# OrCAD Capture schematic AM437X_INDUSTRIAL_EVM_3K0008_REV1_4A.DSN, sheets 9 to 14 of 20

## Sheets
9 Pg03: Processor Power: size C
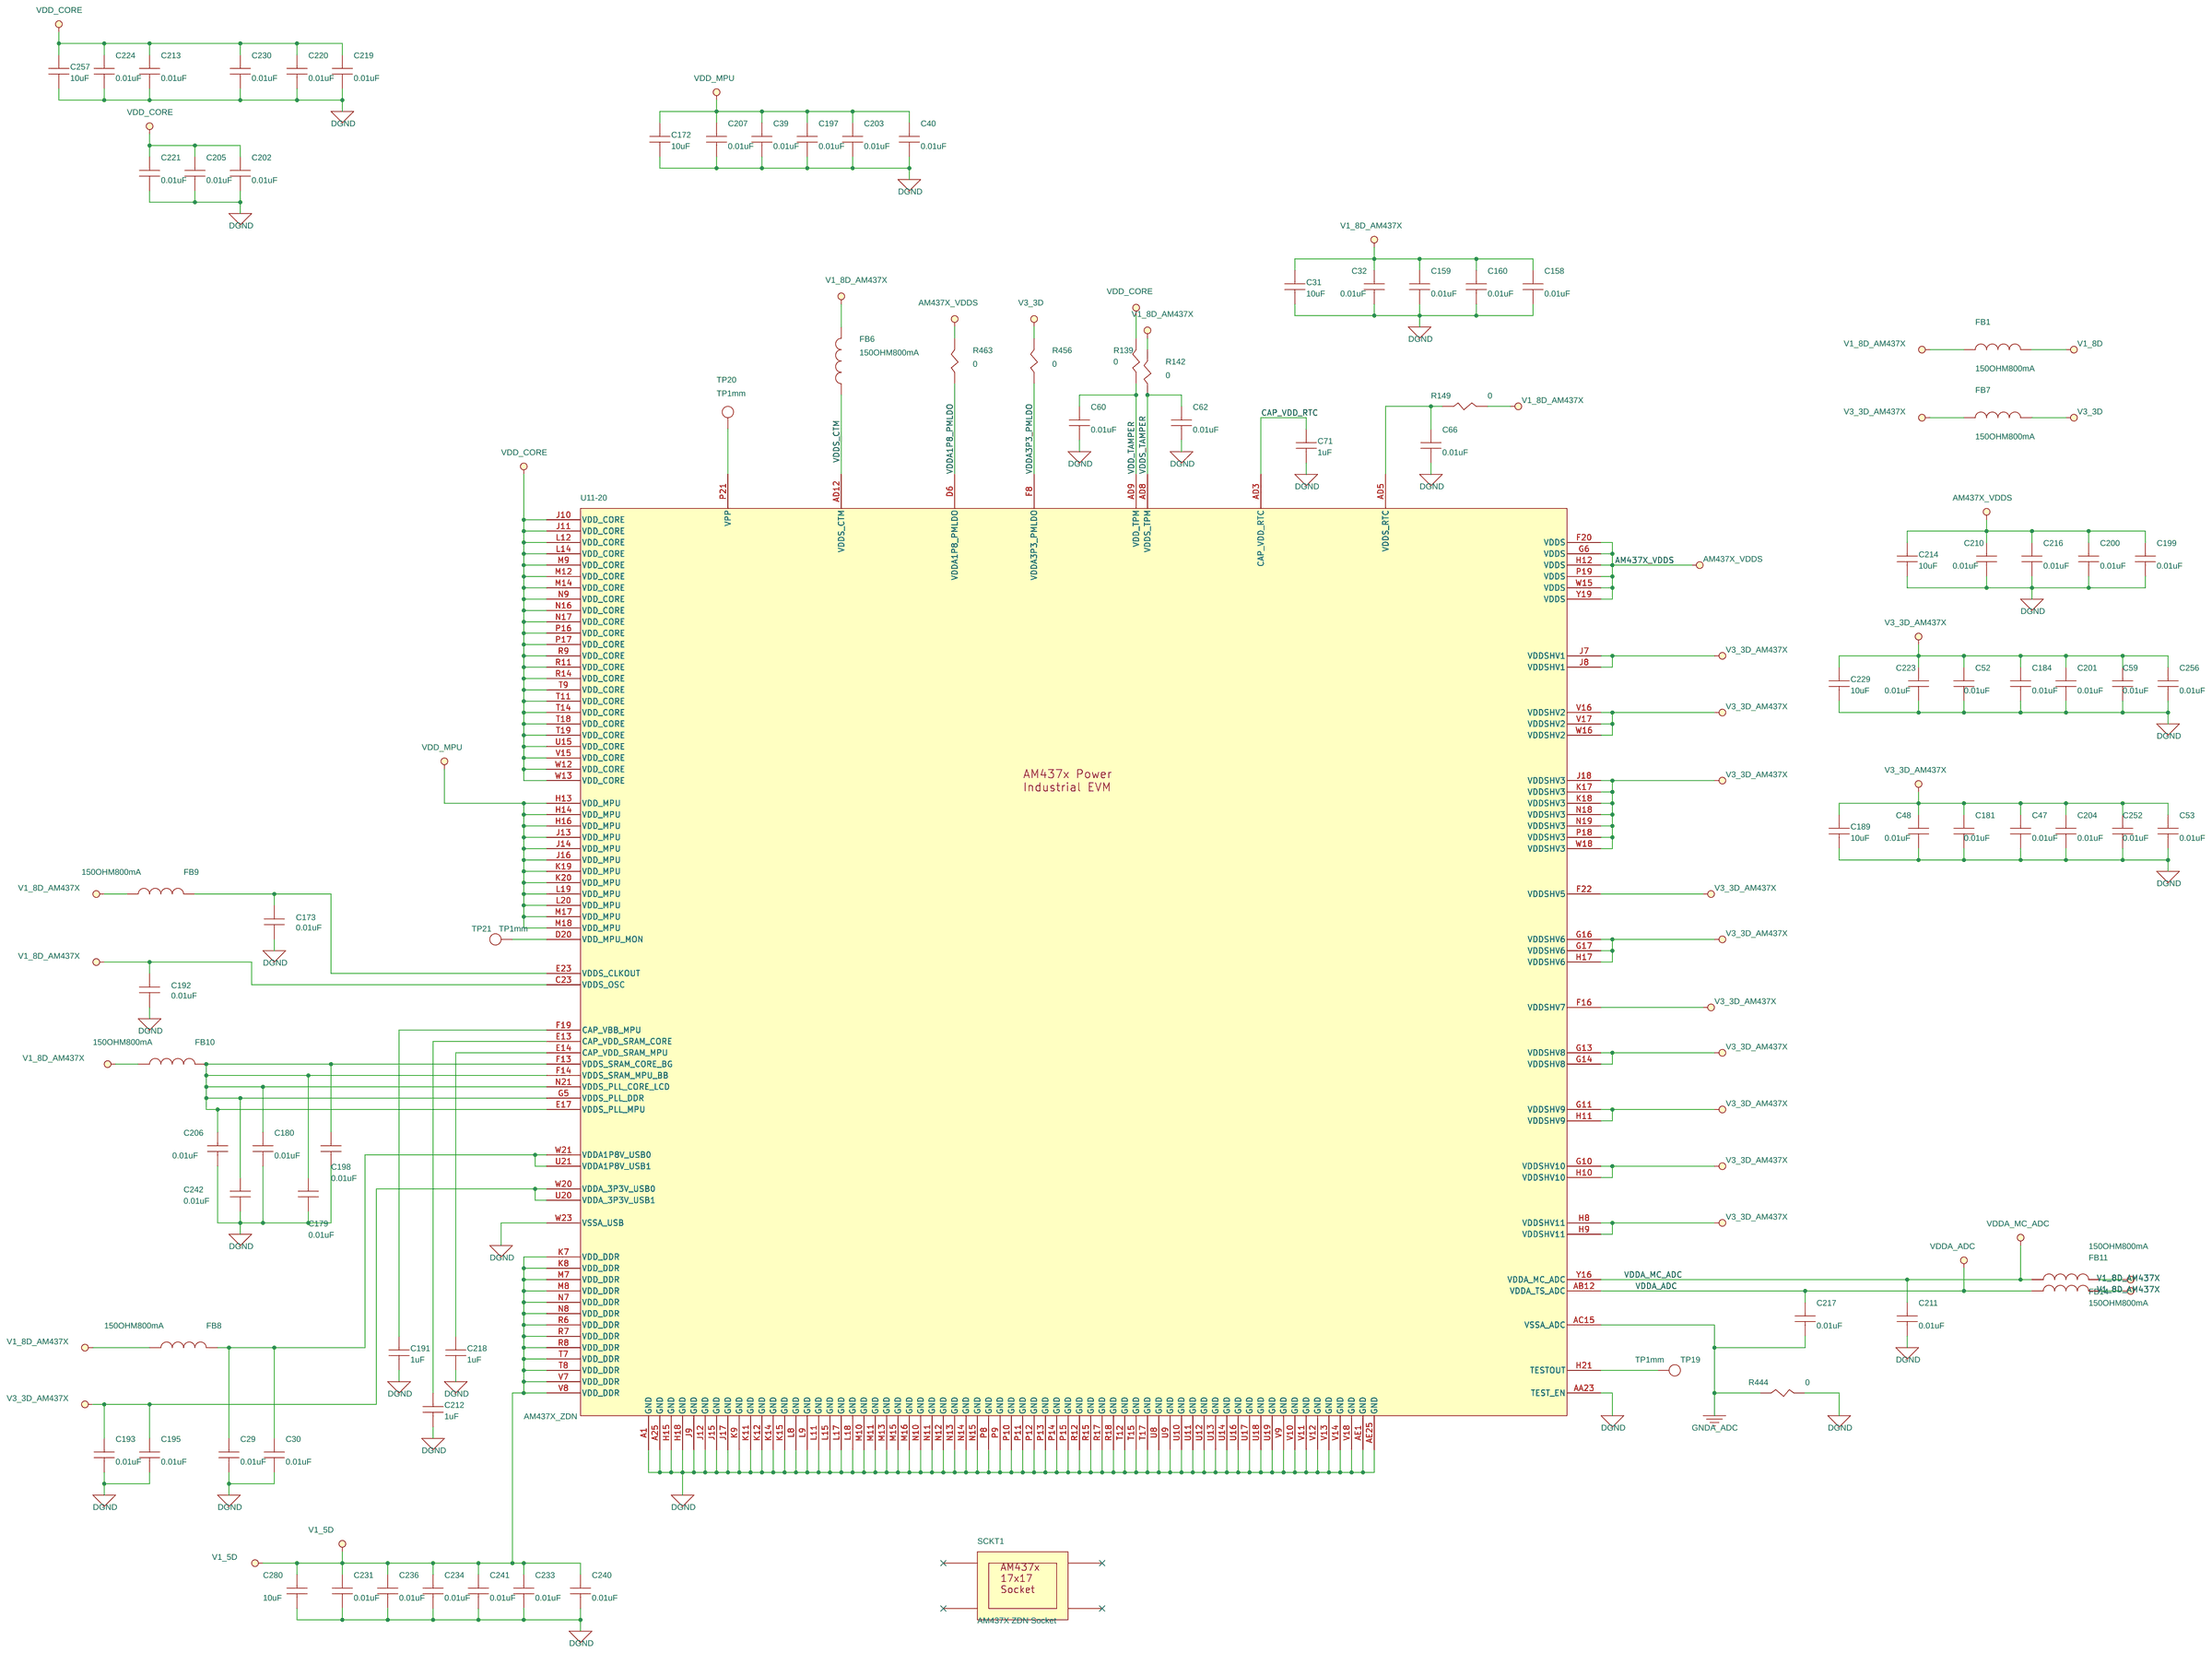
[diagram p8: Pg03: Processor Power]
10 Pg14: Motor Driver: size C
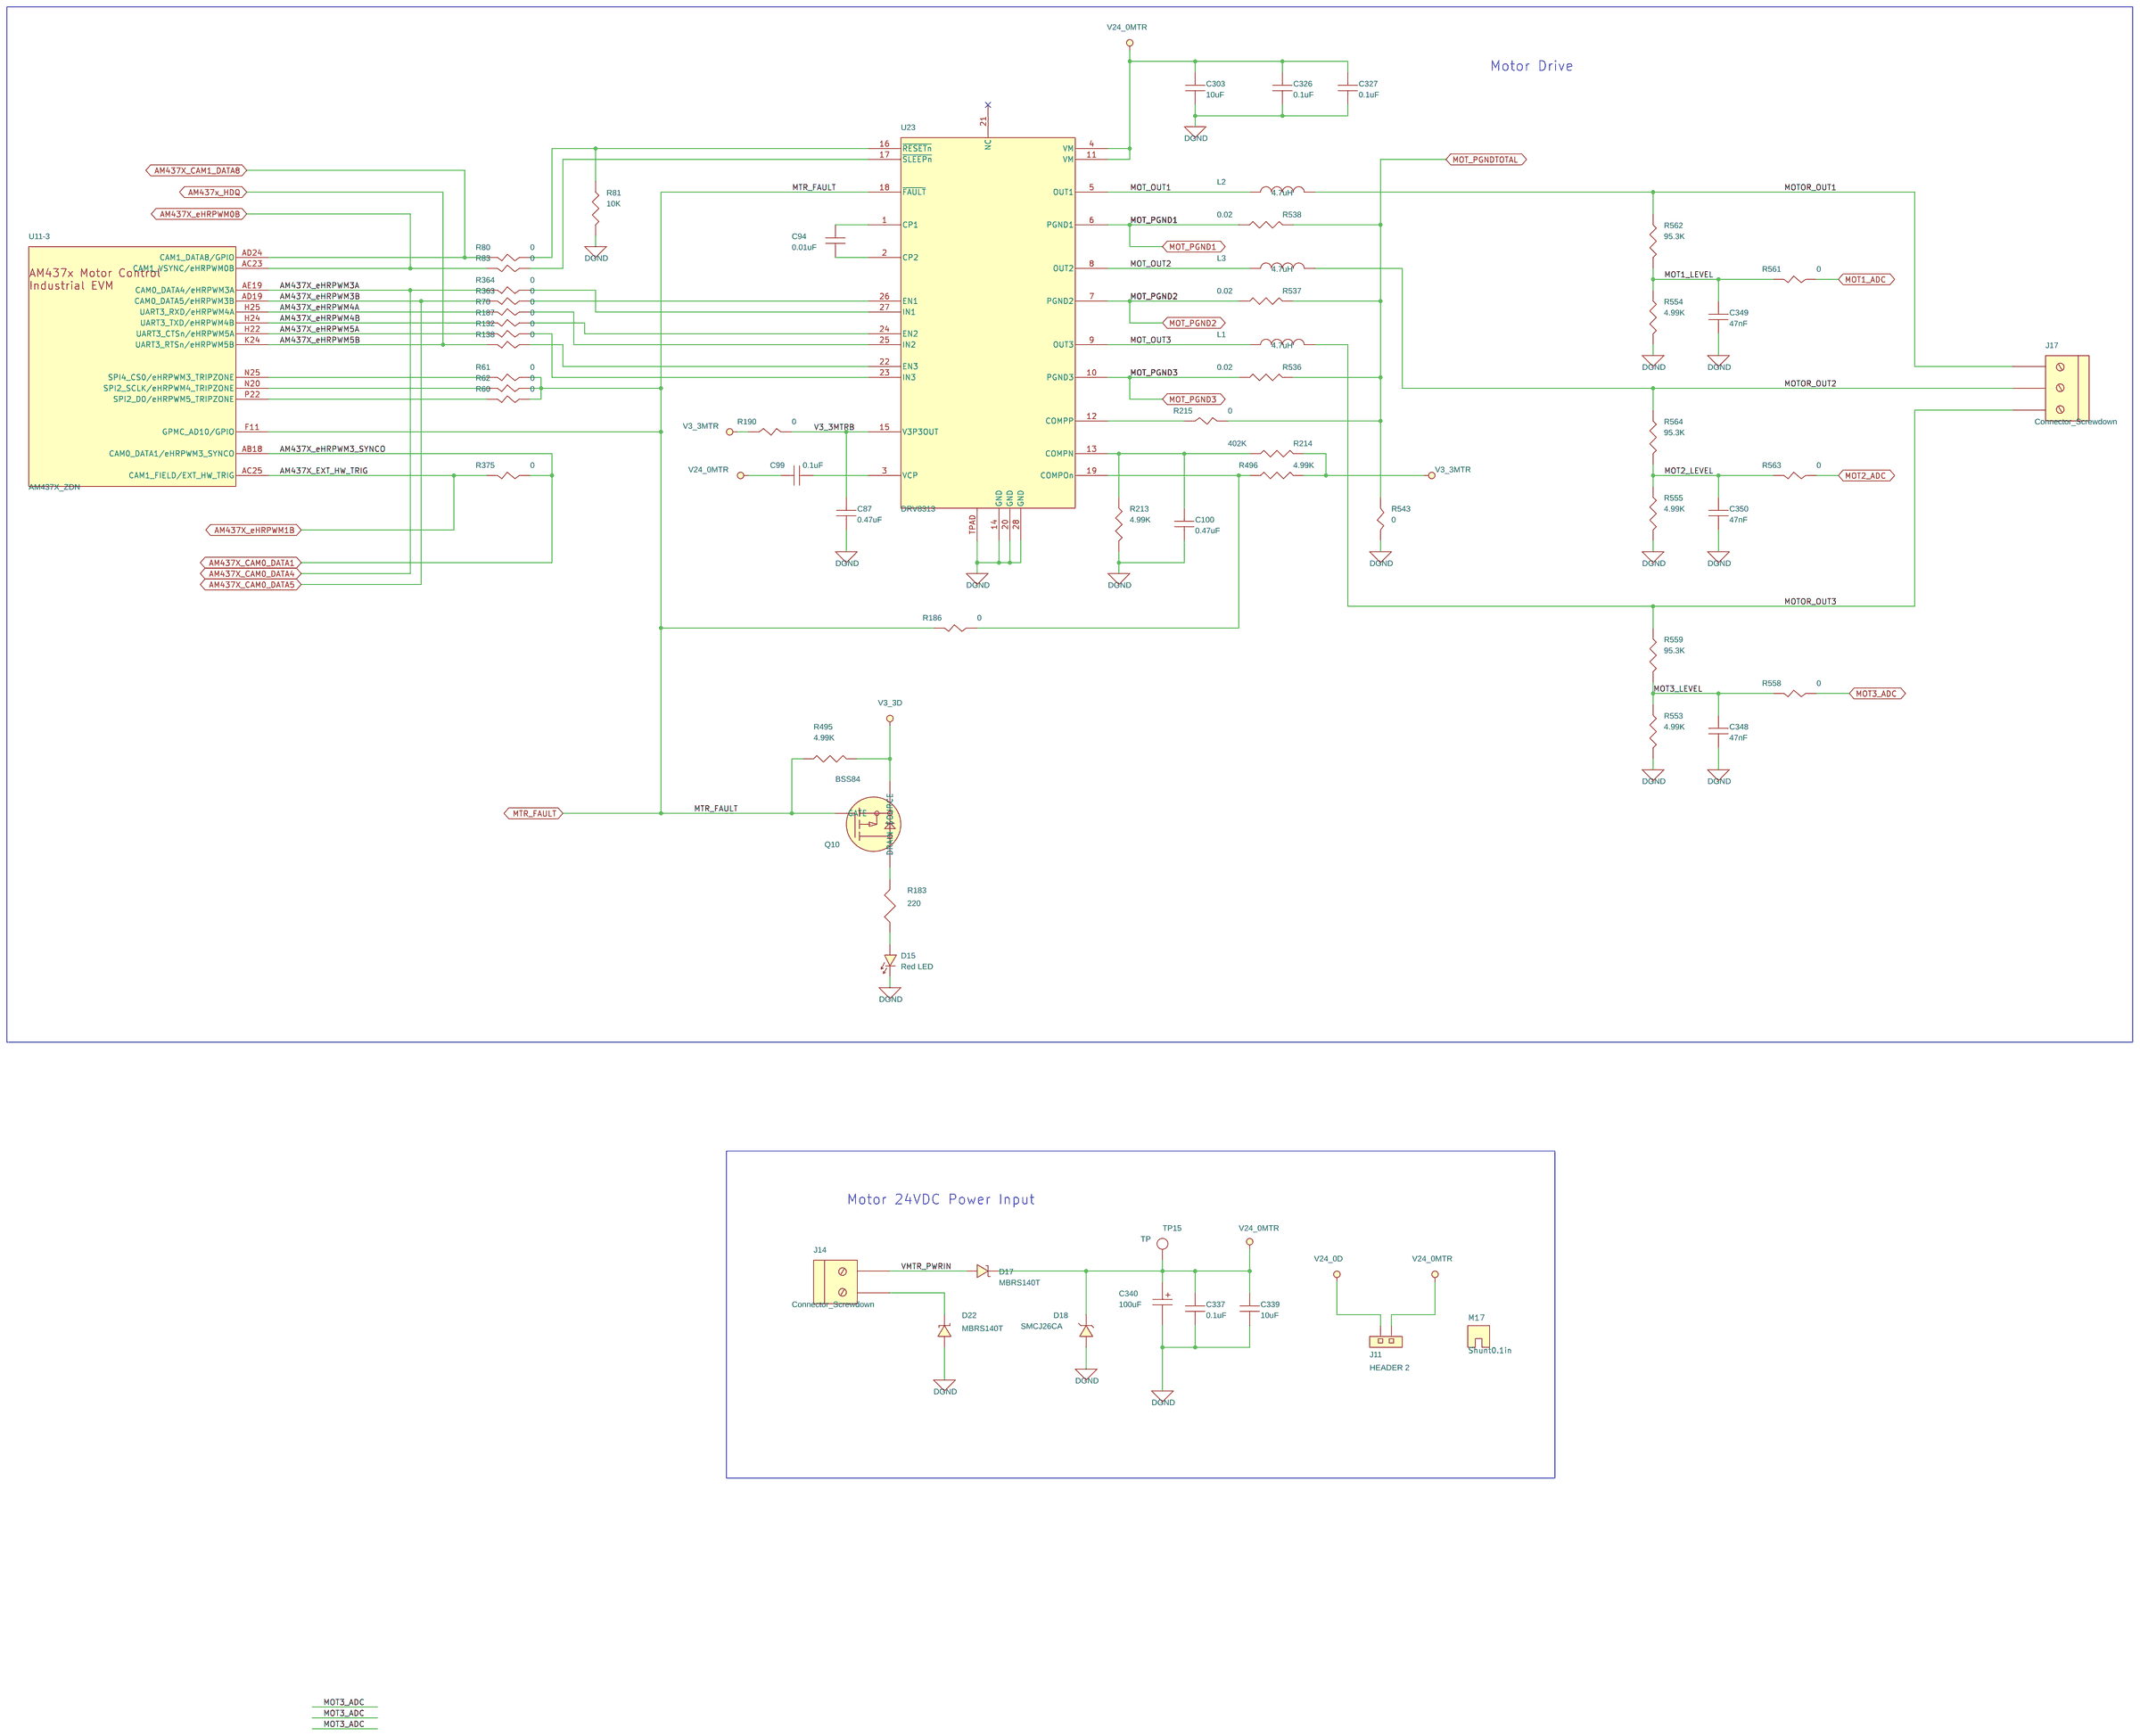
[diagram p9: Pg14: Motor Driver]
11 Pg04: Power Supply: size C
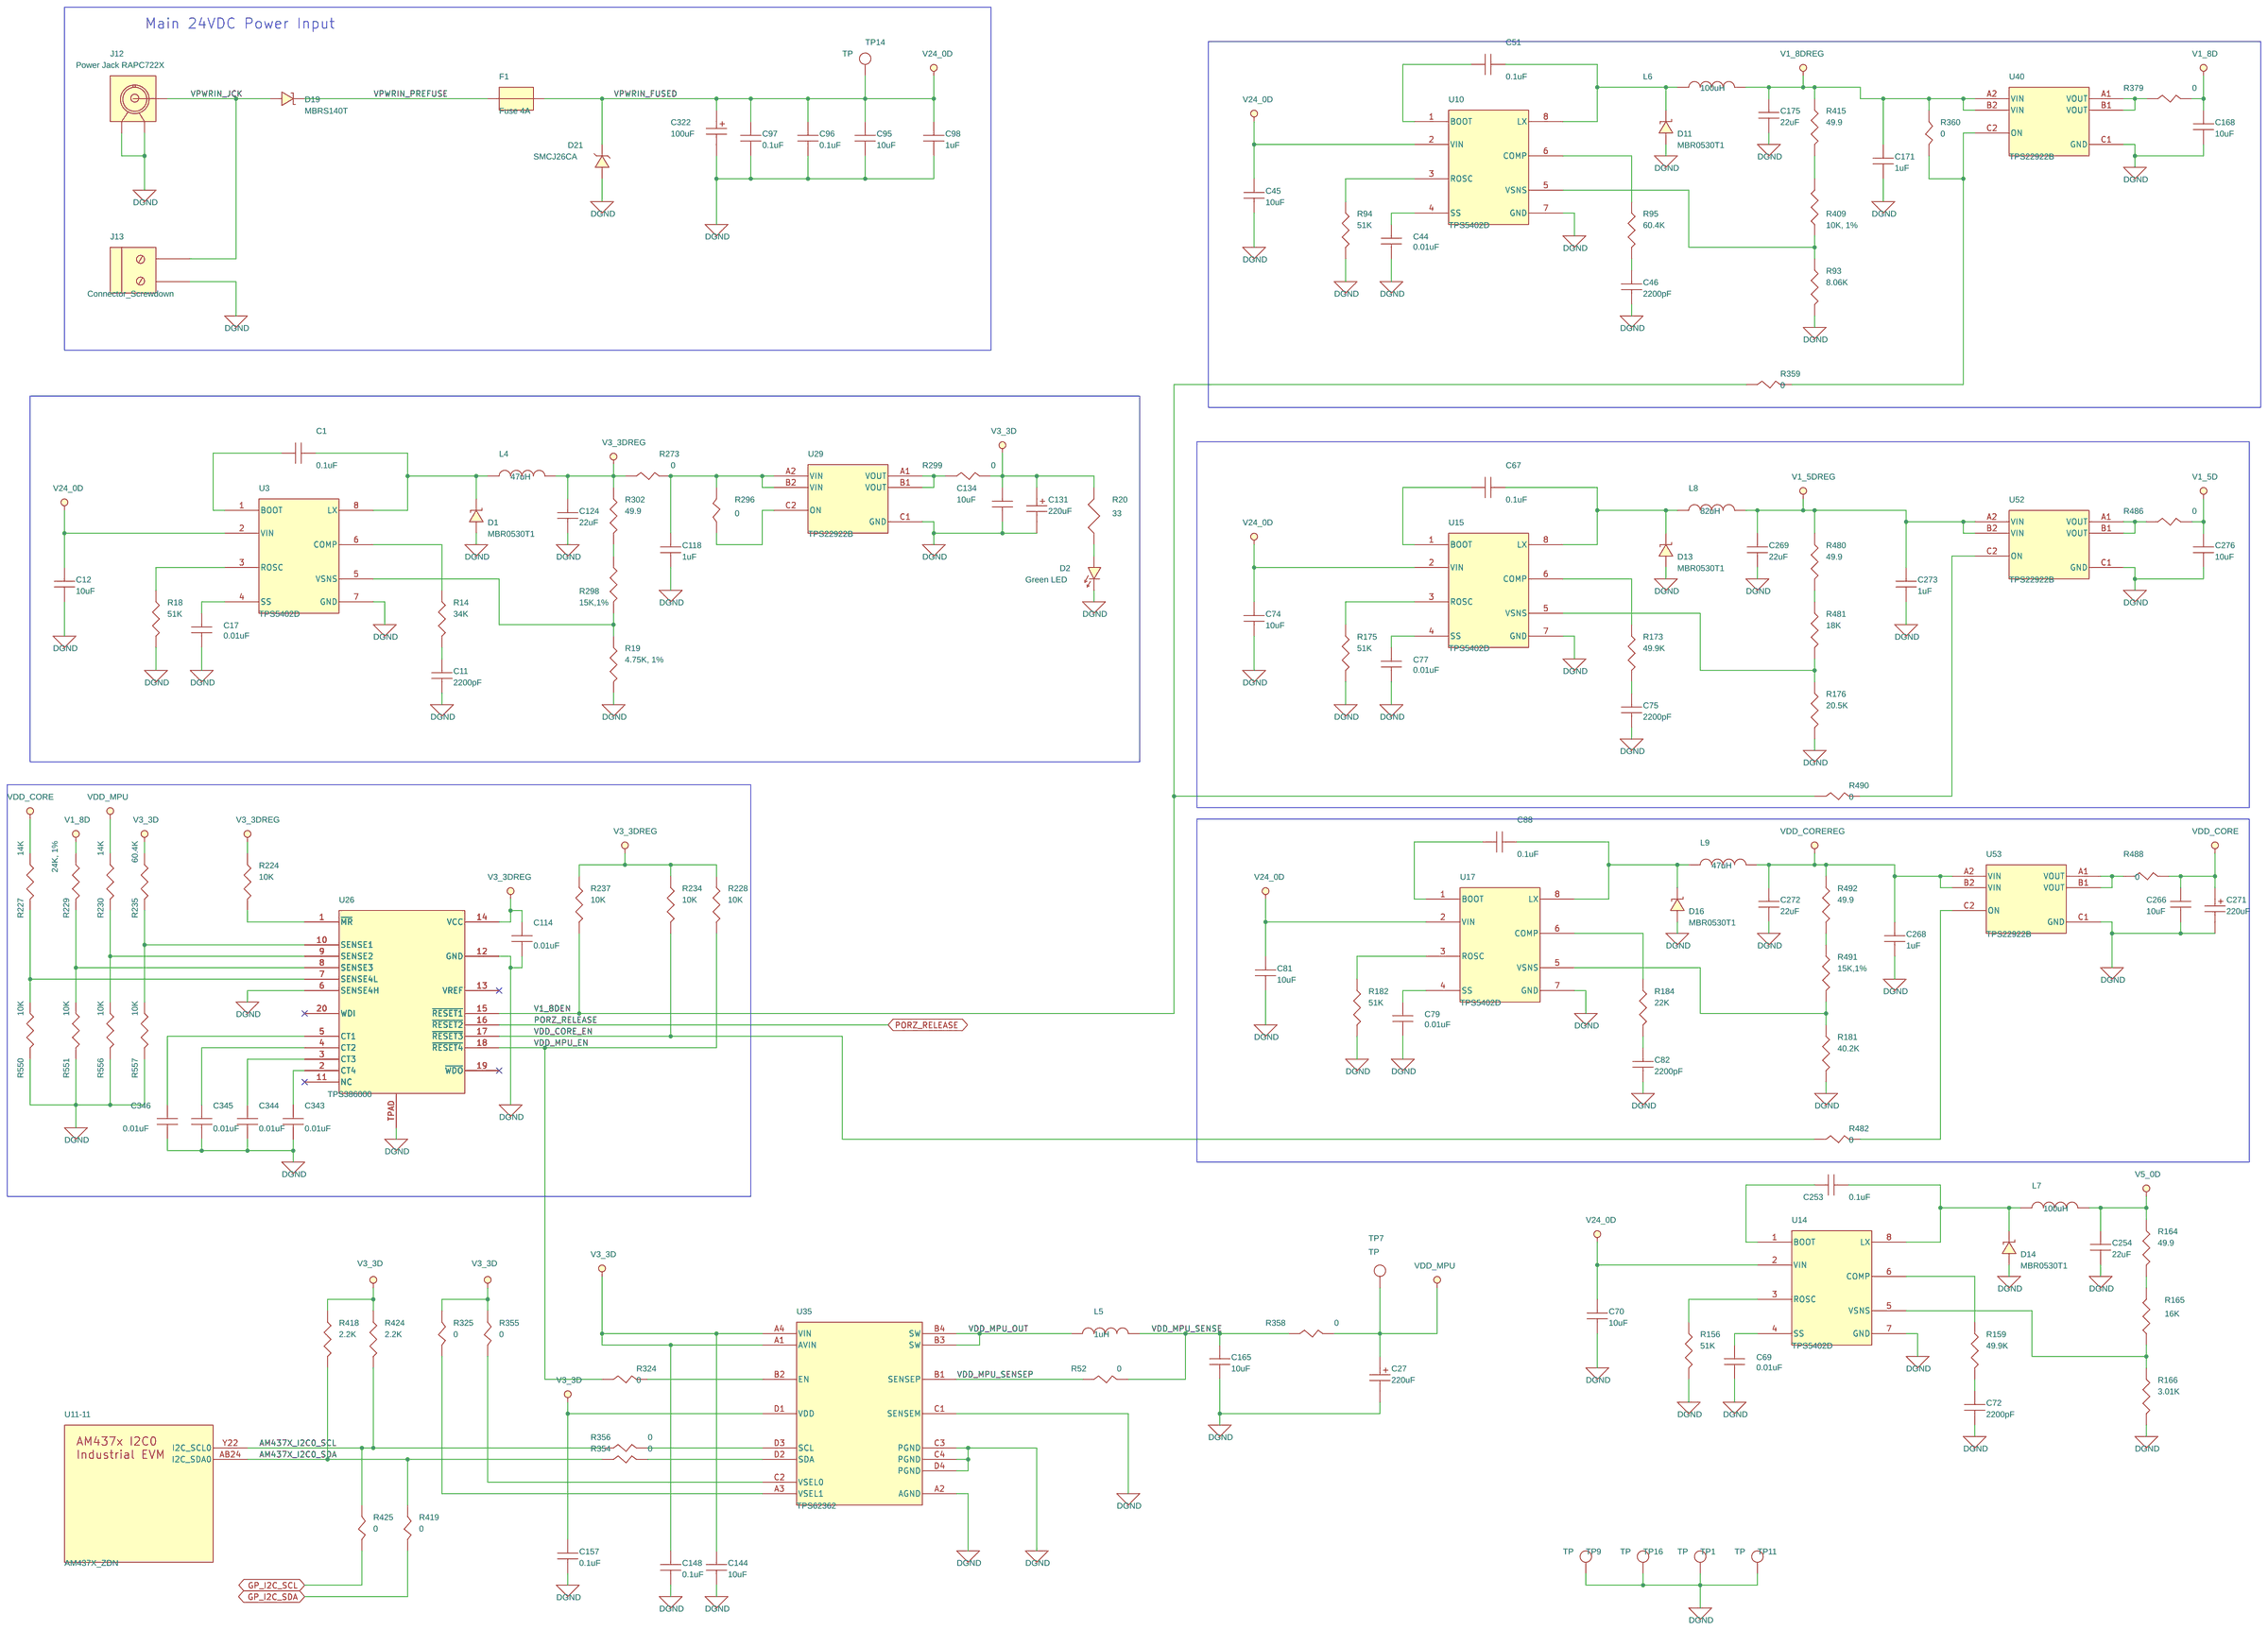
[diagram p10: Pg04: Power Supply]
12 Pg13: Industrial I/O: size C
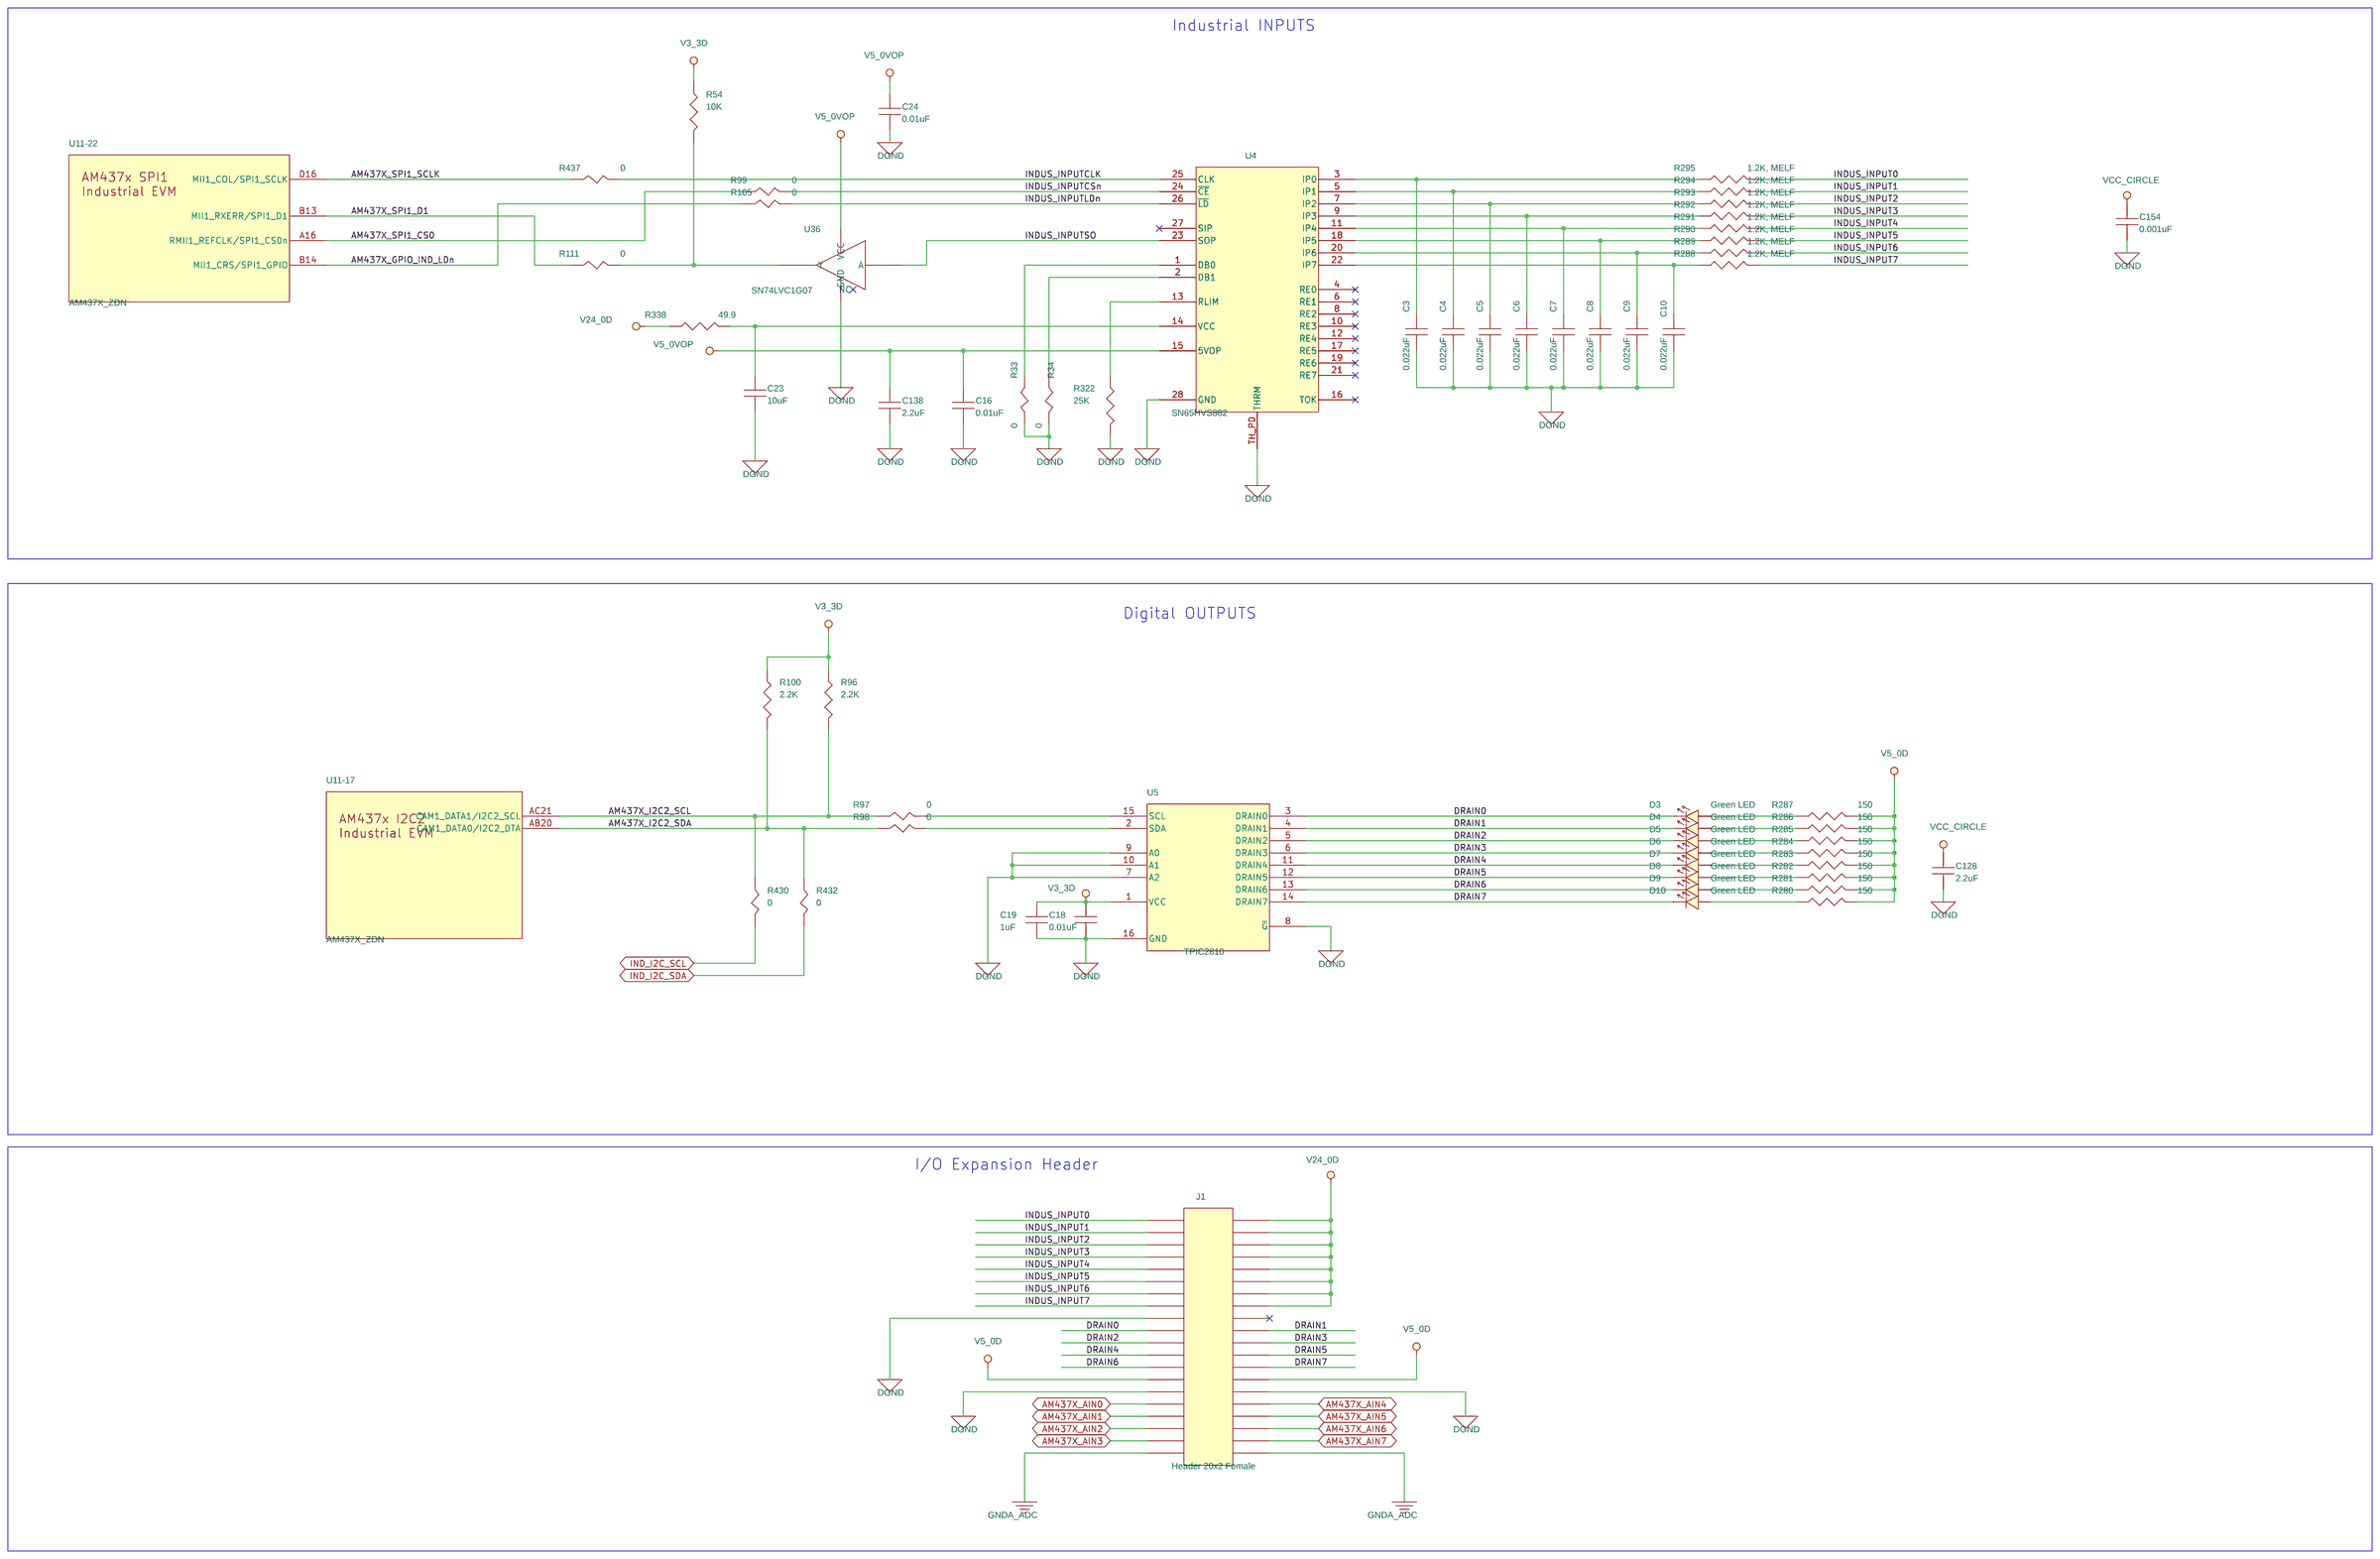
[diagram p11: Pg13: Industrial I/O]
13 Pg11: Gbit Ethernet #1: size C
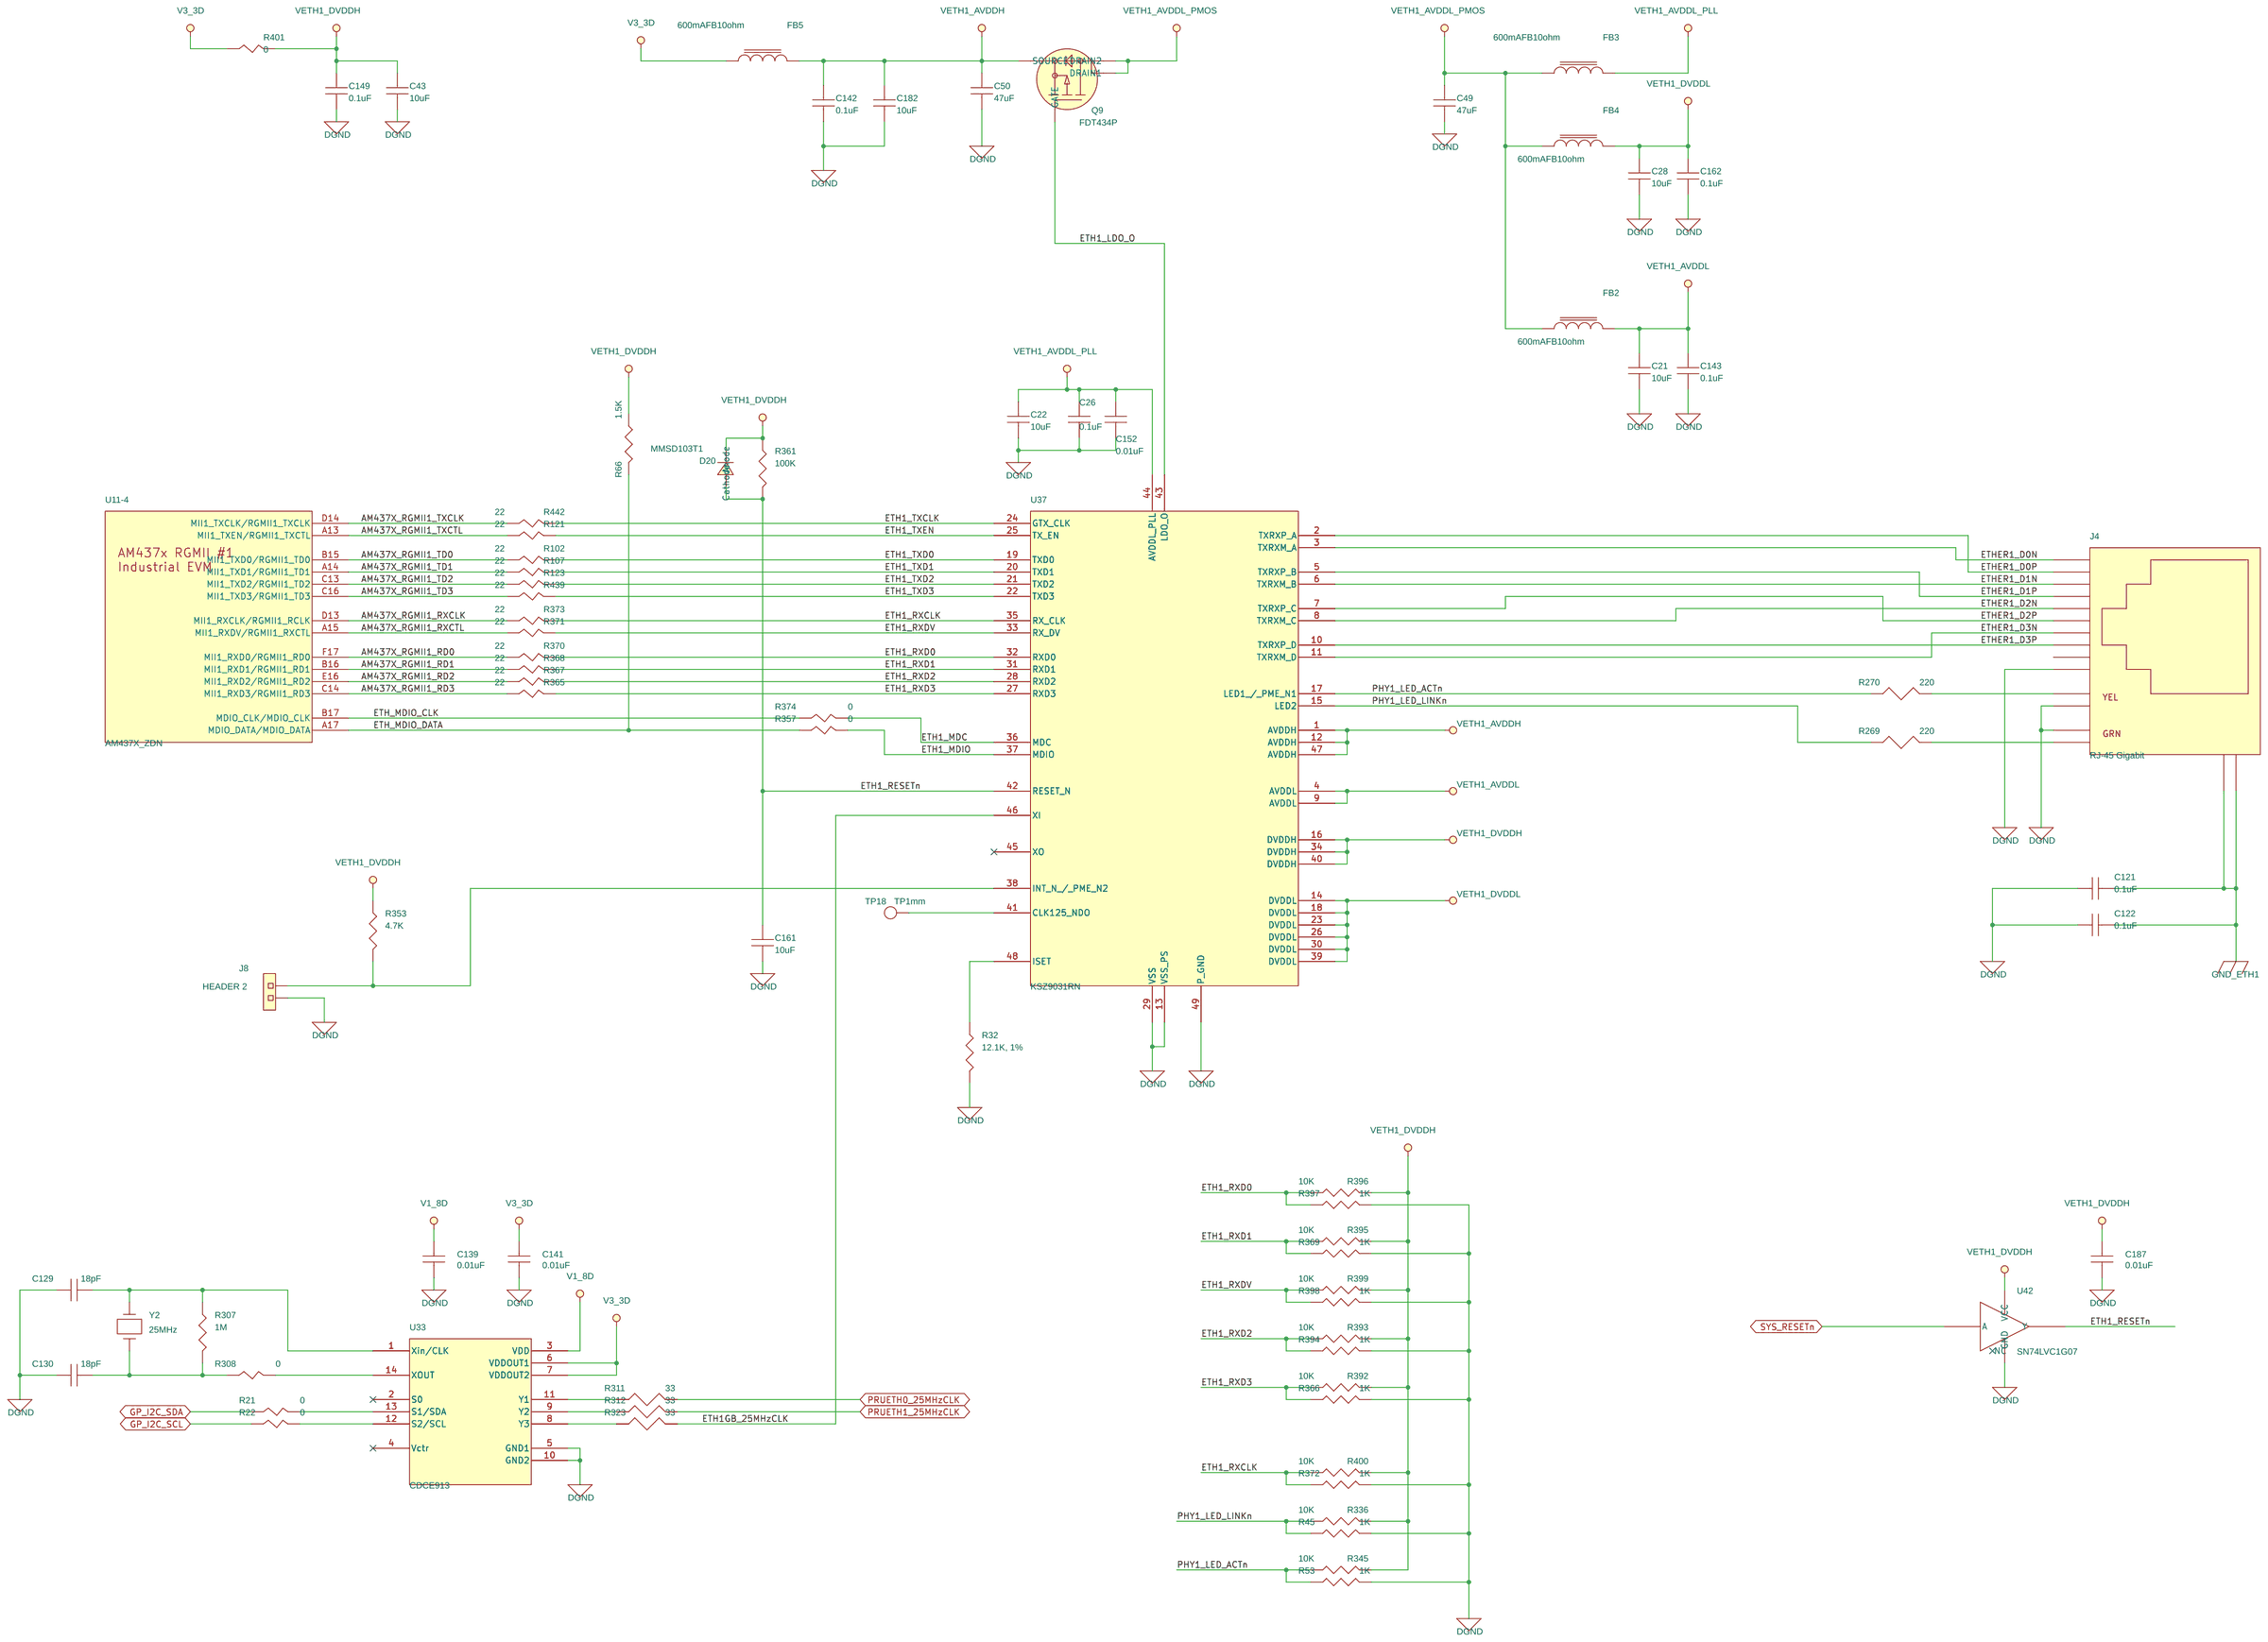
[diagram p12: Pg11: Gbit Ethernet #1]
14 Pg08: ICSS Ethernet 1: size C; note: ARM MPU

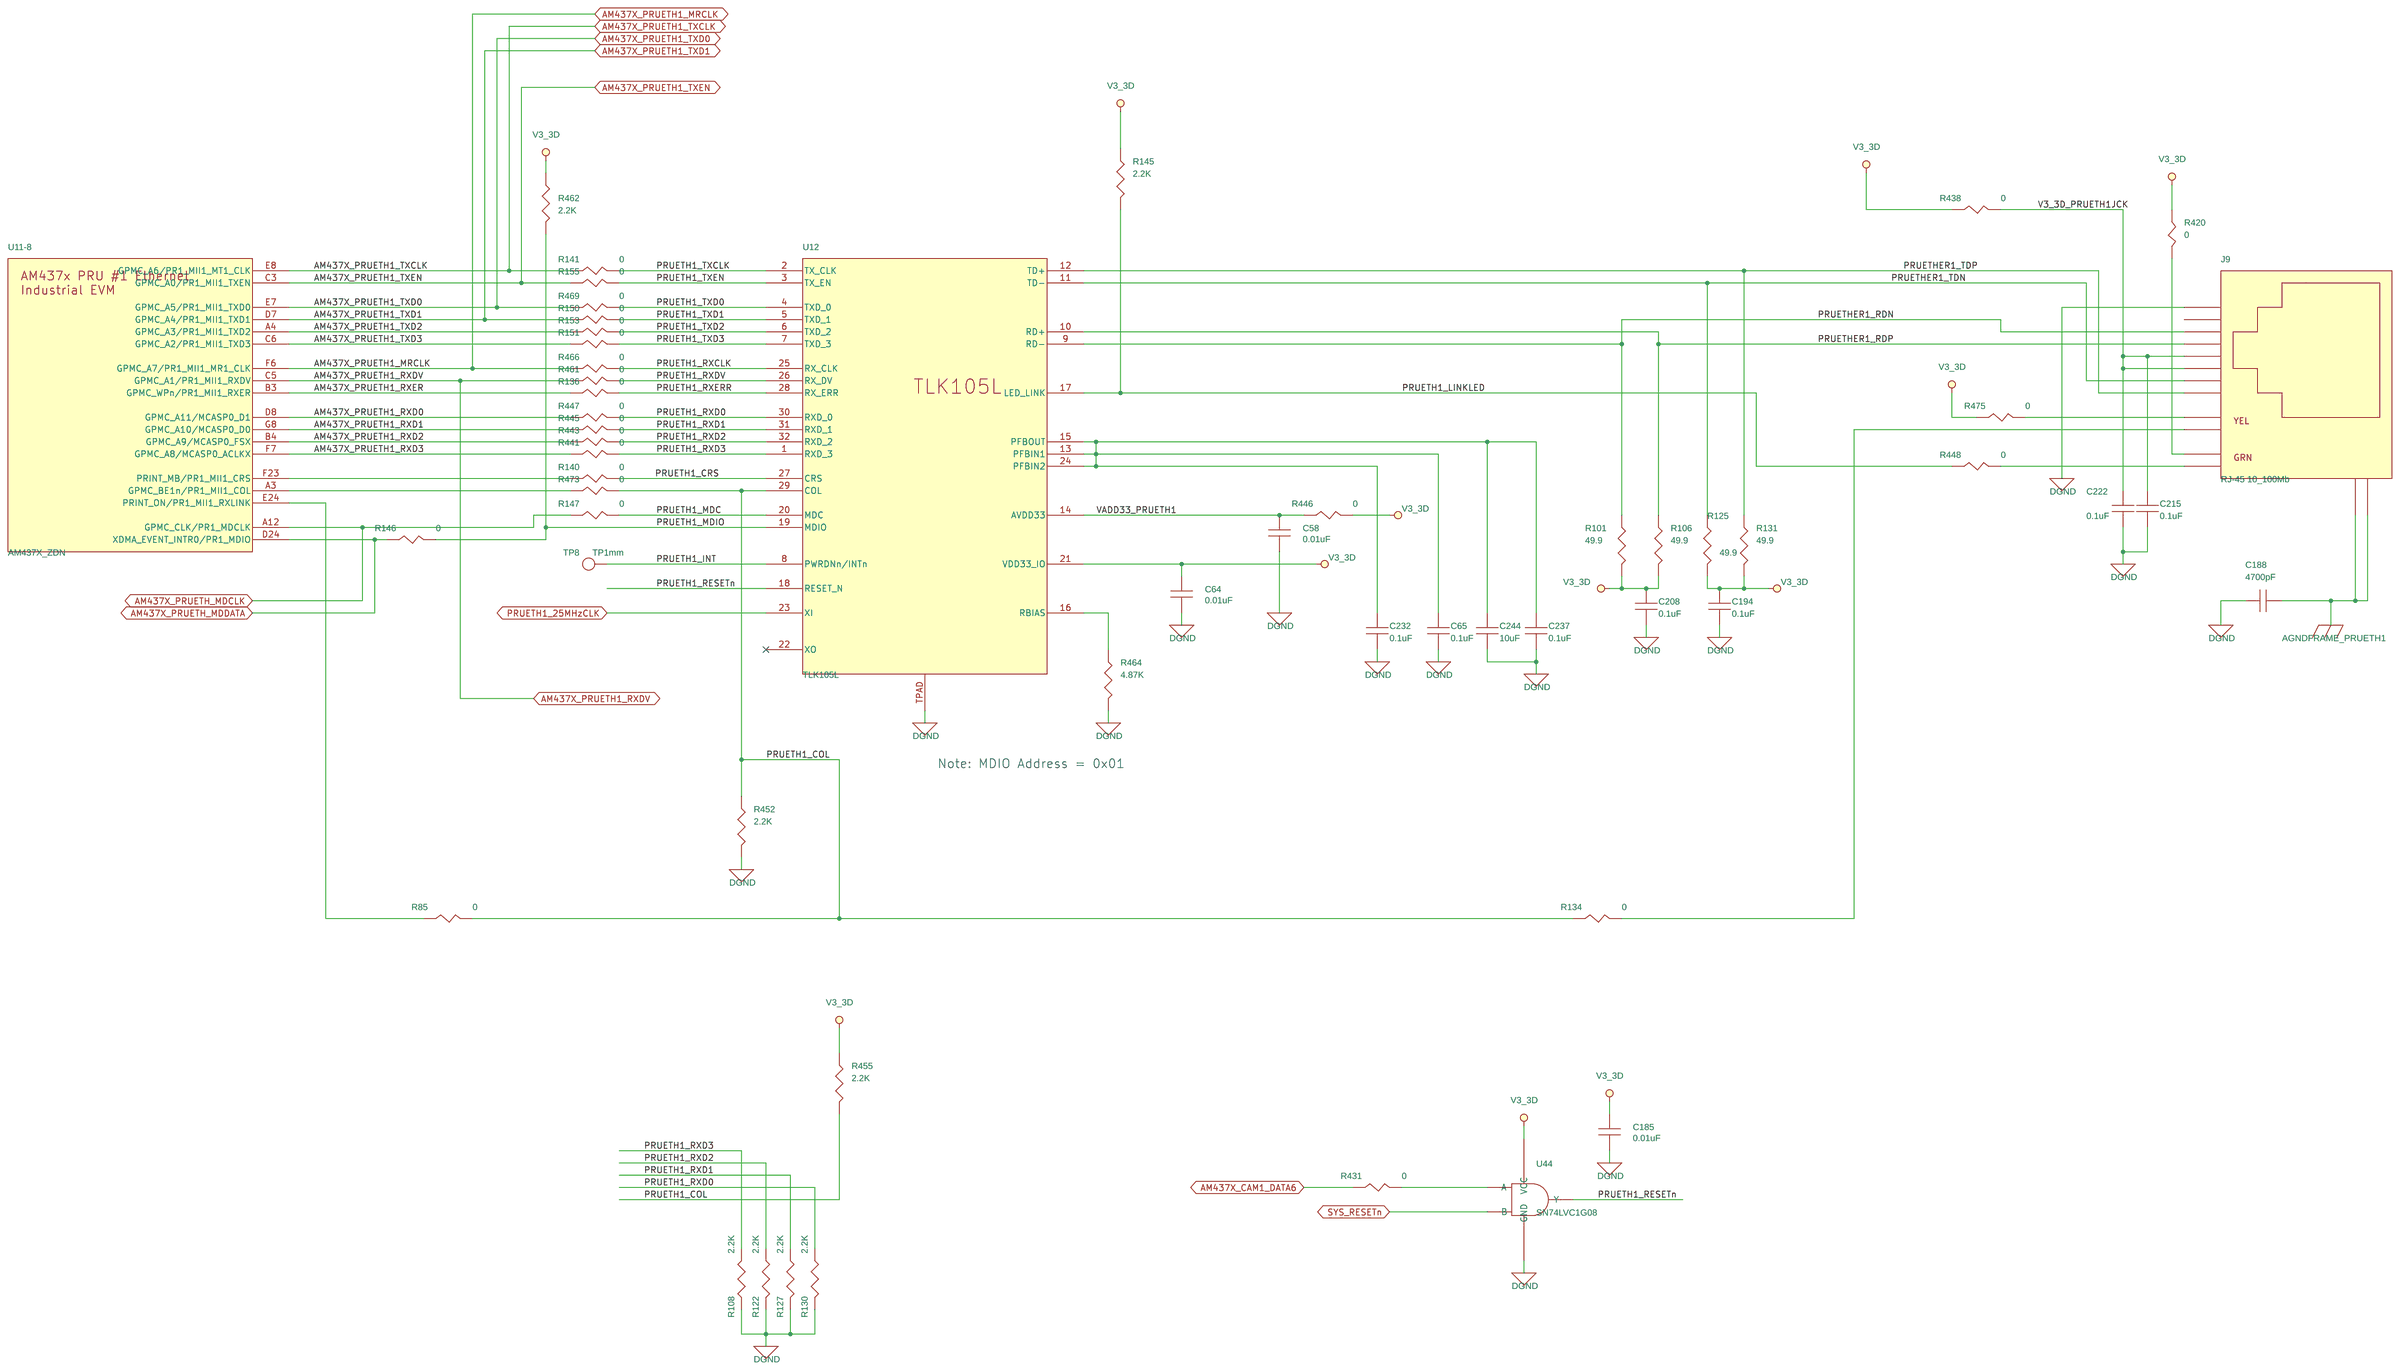
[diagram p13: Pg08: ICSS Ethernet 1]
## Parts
sheet Pg03: Processor Power
C29  0.01uF  [SM-7351-CAP-0402]
C30  0.01uF  [SM-7351-CAP-0402]
C31  10uF  [SM-7351-CAP-0805]
C32  0.01uF  [SM-7351-CAP-0402]
C39  0.01uF  [SM-7351-CAP-0402]
C40  0.01uF  [SM-7351-CAP-0402]
C47  0.01uF  [SM-7351-CAP-0402]
C48  0.01uF  [SM-7351-CAP-0402]
C52  0.01uF  [SM-7351-CAP-0402]
C53  0.01uF  [SM-7351-CAP-0402]
C59  0.01uF  [SM-7351-CAP-0402]
C60  0.01uF  [SM-7351-CAP-0402]
C62  0.01uF  [SM-7351-CAP-0402]
C66  0.01uF  [SM-7351-CAP-0402]
C71  1uF  [SM-7351-CAP-0402]
C158  0.01uF  [SM-7351-CAP-0402]
C159  0.01uF  [SM-7351-CAP-0402]
C160  0.01uF  [SM-7351-CAP-0402]
C172  10uF  [SM-7351-CAP-0805]
C173  0.01uF  [SM-7351-CAP-0402]
C179  0.01uF  [SM-7351-CAP-0402]
C180  0.01uF  [SM-7351-CAP-0402]
C181  0.01uF  [SM-7351-CAP-0402]
C184  0.01uF  [SM-7351-CAP-0402]
C189  10uF  [SM-7351-CAP-0805]
C191  1uF  [SM-7351-CAP-0402]
C192  0.01uF  [SM-7351-CAP-0402]
C193  0.01uF  [SM-7351-CAP-0402]
C195  0.01uF  [SM-7351-CAP-0402]
C197  0.01uF  [SM-7351-CAP-0402]
C198  0.01uF  [SM-7351-CAP-0402]
C199  0.01uF  [SM-7351-CAP-0402]
C200  0.01uF  [SM-7351-CAP-0402]
C201  0.01uF  [SM-7351-CAP-0402]
C202  0.01uF  [SM-7351-CAP-0402]
C203  0.01uF  [SM-7351-CAP-0402]
C204  0.01uF  [SM-7351-CAP-0402]
C205  0.01uF  [SM-7351-CAP-0402]
C206  0.01uF  [SM-7351-CAP-0402]
C207  0.01uF  [SM-7351-CAP-0402]
C210  0.01uF  [SM-7351-CAP-0402]
C211  0.01uF  [SM-7351-CAP-0402]
C212  1uF  [SM-7351-CAP-0402]
C213  0.01uF  [SM-7351-CAP-0402]
C214  10uF  [SM-7351-CAP-0805]
C216  0.01uF  [SM-7351-CAP-0402]
C217  0.01uF  [SM-7351-CAP-0402]
C218  1uF  [SM-7351-CAP-0402]
C219  0.01uF  [SM-7351-CAP-0402]
C220  0.01uF  [SM-7351-CAP-0402]
C221  0.01uF  [SM-7351-CAP-0402]
C223  0.01uF  [SM-7351-CAP-0402]
C224  0.01uF  [SM-7351-CAP-0402]
C229  10uF  [SM-7351-CAP-0805]
C230  0.01uF  [SM-7351-CAP-0402]
C231  0.01uF  [SM-7351-CAP-0402]
C233  0.01uF  [SM-7351-CAP-0402]
C234  0.01uF  [SM-7351-CAP-0402]
C236  0.01uF  [SM-7351-CAP-0402]
C240  0.01uF  [SM-7351-CAP-0402]
C241  0.01uF  [SM-7351-CAP-0402]
C242  0.01uF  [SM-7351-CAP-0402]
C252  0.01uF  [SM-7351-CAP-0402]
C256  0.01uF  [SM-7351-CAP-0402]
C257  10uF  [SM-7351-CAP-0805]
C280  10uF  [SM-7351-CAP-0805]
FB1  150OHM800mA  [sm-7351-ind-0805]
FB6  150OHM800mA  [sm-7351-ind-0805]
FB7  150OHM800mA  [sm-7351-ind-0805]
FB8  150OHM800mA  [sm-7351-ind-0805]
FB9  150OHM800mA  [sm-7351-ind-0805]
FB10  150OHM800mA  [sm-7351-ind-0805]
FB11  150OHM800mA  [sm-7351-ind-0805]
FB14  150OHM800mA  [sm-7351-ind-0805]
R139  0  [SM-7351-RES-0603]
R142  0  [SM-7351-RES-0603]
R149  0  [SM-7351-RES-0603]
R444  0  [SM-7351-RES-0402]
R456  0  [SM-7351-RES-0603]
R463  0  [SM-7351-RES-0603]
SCKT1  AM437X ZDN Socket  [SCKBGA625]
TP19  TP1mm  [tp_smd1mmcircle]
TP20  TP1mm  [tp_smd1mmcircle]
TP21  TP1mm  [tp_smd1mmcircle]
sheet Pg04: Power Supply
C1  0.1uF  [SM-7351-CAP-0402]
C11  2200pF  [SM-7351-CAP-0402]
C12  10uF  [SM-7351-CAP-0805]
C17  0.01uF  [SM-7351-CAP-0402]
C27  220uF  [smd7343-122m]
C44  0.01uF  [SM-7351-CAP-0402]
C45  10uF  [SM-7351-CAP-0805]
C46  2200pF  [SM-7351-CAP-0402]
C51  0.1uF  [SM-7351-CAP-0402]
C67  0.1uF  [SM-7351-CAP-0402]
C69  0.01uF  [SM-7351-CAP-0402]
C70  10uF  [SM-7351-CAP-0805]
C72  2200pF  [SM-7351-CAP-0402]
C74  10uF  [SM-7351-CAP-0805]
C75  2200pF  [SM-7351-CAP-0402]
C77  0.01uF  [SM-7351-CAP-0402]
C79  0.01uF  [SM-7351-CAP-0402]
C81  10uF  [SM-7351-CAP-0805]
C82  2200pF  [SM-7351-CAP-0402]
C88  0.1uF  [SM-7351-CAP-0402]
C95  10uF  [SM-7351-CAP-0805]
C96  0.1uF  [SM-7351-CAP-0402]
C97  0.1uF  [SM-7351-CAP-0402]
C98  1uF  [SM-7351-CAP-0402]
C114  0.01uF  [SM-7351-CAP-0402]
C118  1uF  [SM-7351-CAP-0603]
C124  22uF  [SM-7351-CAP-0805]
C131  220uF  [smd7343-122m]
C134  10uF  [SM-7351-CAP-0805]
C144  10uF  [SM-7351-CAP-0603]
C148  0.1uF  [SM-7351-CAP-0402]
C157  0.1uF  [SM-7351-CAP-0402]
C165  10uF  [SM-7351-CAP-0603]
C168  10uF  [SM-7351-CAP-0805]
C171  1uF  [SM-7351-CAP-0603]
C175  22uF  [SM-7351-CAP-0805]
C253  0.1uF  [SM-7351-CAP-0402]
C254  22uF  [SM-7351-CAP-0805]
C266  10uF  [SM-7351-CAP-0805]
C268  1uF  [SM-7351-CAP-0603]
C269  22uF  [SM-7351-CAP-0805]
C271  220uF  [smd7343-122m]
C272  22uF  [SM-7351-CAP-0805]
C273  1uF  [SM-7351-CAP-0603]
C276  10uF  [SM-7351-CAP-0805]
C322  100uF  [CAP-ALUM-D6XL7]
C343  0.01uF  [SM-7351-CAP-0402]
C344  0.01uF  [SM-7351-CAP-0402]
C345  0.01uF  [SM-7351-CAP-0402]
C346  0.01uF  [SM-7351-CAP-0402]
D1  MBR0530T1  [sod-123]
D2  Green LED  [sm_led_0805]
D11  MBR0530T1  [sod-123]
D13  MBR0530T1  [sod-123]
D14  MBR0530T1  [sod-123]
D16  MBR0530T1  [sod-123]
D19  MBRS140T  [mbrs140t]
D21  SMCJ26CA  [SMCJ26CA]
F1  Fuse 4A  [smdfuseblk]
J12  Power Jack RAPC722X  [RAPC712]
J13  Connector_Screwdown  [conn_osttc02]
L4  47uH  [indmss1038]
L5  1uH  [IND4X4-83M]
L6  100uH  [indmss6132]
L7  100uH  [indmss1038]
L8  82uH  [indmss6122]
L9  47uH  [indmss6132]
R14  34K  [sm-7351-res-0402]
R18  51K  [SM-7351-RES-0402]
R19  4.75K, 1%  [SM-7351-RES-0402]
R20  33  [SM-7351-RES-0402]
R52  0  [SM-7351-RES-0402]
R93  8.06K  [SM-7351-RES-0402]
R94  51K  [SM-7351-RES-0402]
R95  60.4K  [SM-7351-RES-0402]
R156  51K  [SM-7351-RES-0402]
R159  49.9K  [SM-7351-RES-0402]
R164  49.9  [SM-7351-RES-0402]
R165  16K  [SM-7351-RES-0402]
R166  3.01K  [SM-7351-RES-0402]
R173  49.9K  [SM-7351-RES-0402]
R175  51K  [SM-7351-RES-0402]
R176  20.5K  [SM-7351-RES-0402]
R181  40.2K  [SM-7351-RES-0402]
R182  51K  [SM-7351-RES-0402]
R184  22K  [SM-7351-RES-0402]
R224  10K  [SM-7351-RES-0402]
R227  14K  [SM-7351-RES-0402]
R228  10K  [SM-7351-RES-0402]
R229  24K, 1%  [SM-7351-RES-0402]
R230  14K  [SM-7351-RES-0402]
R234  10K  [SM-7351-RES-0402]
R235  60.4K  [SM-7351-RES-0402]
R237  10K  [SM-7351-RES-0402]
R273  0  [SM-7351-RES-0603]
R296  0  [SM-7351-RES-0402]
R298  15K,1%  [SM-7351-RES-0402]
R299  0  [SM-7351-RES-0603]
R302  49.9  [SM-7351-RES-0402]
R324  0  [SM-7351-RES-0402]
R325  0  [SM-7351-RES-0402]
R354  0  [SM-7351-RES-0402]
R355  0  [SM-7351-RES-0402]
R356  0  [SM-7351-RES-0402]
R358  0  [SM-7351-RES-0603]
R359  0  [SM-7351-RES-0402]
R360  0  [SM-7351-RES-0402]
R379  0  [SM-7351-RES-0603]
R409  10K, 1%  [SM-7351-RES-0402]
R415  49.9  [SM-7351-RES-0402]
R418  2.2K  [sm-7351-res-0402]
R419  0  [SM-7351-RES-0402]
R424  2.2K  [sm-7351-res-0402]
R425  0  [SM-7351-RES-0402]
R480  49.9  [SM-7351-RES-0402]
R481  18K  [SM-7351-RES-0402]
R482  0  [SM-7351-RES-0402]
R486  0  [SM-7351-RES-0603]
R488  0  [SM-7351-RES-0603]
R490  0  [SM-7351-RES-0402]
R491  15K,1%  [SM-7351-RES-0402]
R492  49.9  [SM-7351-RES-0402]
R550  10K  [SM-7351-RES-0402]
R551  10K  [SM-7351-RES-0402]
R556  10K  [SM-7351-RES-0402]
R557  10K  [SM-7351-RES-0402]
TP1  TP  [TH_TP_5002]
TP7  TP  [TH_TP_5002]
TP9  TP  [TH_TP_5002]
TP11  TP  [TH_TP_5002]
TP14  TP  [TH_TP_5002]
TP16  TP  [TH_TP_5002]
U3  TPS5402D  [SOIC-8]
U10  TPS5402D  [SOIC-8]
U14  TPS5402D  [SOIC-8]
U15  TPS5402D  [SOIC-8]
U17  TPS5402D  [SOIC-8]
U26  TPS386000  [qfn4x4-20-39m]
U29  TPS22922B  [wcsp1x1-6-20m]
U35  TPS62362  [BGA2x2-16]
U40  TPS22922B  [wcsp1x1-6-20m]
U52  TPS22922B  [wcsp1x1-6-20m]
U53  TPS22922B  [wcsp1x1-6-20m]
sheet Pg08: ICSS Ethernet 1
C58  0.01uF  [SM-7351-CAP-0402]
C64  0.01uF  [SM-7351-CAP-0402]
C65  0.1uF  [SM-7351-CAP-0402]
C185  0.01uF  [SM-7351-CAP-0402]
C188  4700pF  [SM-7351-CAP-0402]
C194  0.1uF  [SM-7351-CAP-0402]
C208  0.1uF  [SM-7351-CAP-0402]
C215  0.1uF  [SM-7351-CAP-0402]
C222  0.1uF  [SM-7351-CAP-0402]
C232  0.1uF  [SM-7351-CAP-0402]
C237  0.1uF  [SM-7351-CAP-0402]
C244  10uF  [SM-7351-CAP-0805]
J9  RJ-45 10_100Mb  [CNRJ45-1X1WLED]
R85  0  [SM-7351-RES-0402]
R101  49.9  [SM-7351-RES-0402]
R106  49.9  [SM-7351-RES-0402]
R108  2.2K  [sm-7351-res-0402]
R122  2.2K  [sm-7351-res-0402]
R125  49.9  [SM-7351-RES-0402]
R127  2.2K  [sm-7351-res-0402]
R130  2.2K  [sm-7351-res-0402]
R131  49.9  [SM-7351-RES-0402]
R134  0  [SM-7351-RES-0402]
R136  0  [SM-7351-RES-0402]
R140  0  [SM-7351-RES-0402]
R141  0  [SM-7351-RES-0402]
R145  2.2K  [sm-7351-res-0402]
R146  0  [SM-7351-RES-0402]
R147  0  [SM-7351-RES-0402]
R150  0  [SM-7351-RES-0402]
R151  0  [SM-7351-RES-0402]
R153  0  [SM-7351-RES-0402]
R155  0  [SM-7351-RES-0402]
R420  0  [SM-7351-RES-0402]
R431  0  [SM-7351-RES-0402]
R438  0  [SM-7351-RES-0402]
R441  0  [SM-7351-RES-0402]
R443  0  [SM-7351-RES-0402]
R445  0  [SM-7351-RES-0402]
R446  0  [SM-7351-RES-0603]
R447  0  [SM-7351-RES-0402]
R448  0  [SM-7351-RES-0603]
R452  2.2K  [sm-7351-res-0402]
R455  2.2K  [sm-7351-res-0402]
R461  0  [SM-7351-RES-0402]
R462  2.2K  [sm-7351-res-0402]
R464  4.87K  [SM-7351-RES-0402]
R466  0  [SM-7351-RES-0402]
R469  0  [SM-7351-RES-0402]
R473  0  [SM-7351-RES-0402]
R475  0  [SM-7351-RES-0402]
TP8  TP1mm  [tp_smd1mmcircle]
U12  TLK105L  [qfn5x5-32-39m]
U44  SN74LVC1G08  [sm-so-sc70-5]
sheet Pg11: Gbit Ethernet #1
C21  10uF  [SM-7351-CAP-0805]
C22  10uF  [SM-7351-CAP-0805]
C26  0.1uF  [SM-7351-CAP-0402]
C28  10uF  [SM-7351-CAP-0805]
C43  10uF  [SM-7351-CAP-0805]
C49  47uF  [SM-7351-CAP-1206]
C50  47uF  [SM-7351-CAP-1206]
C121  0.1uF  [SM-7351-CAP-0402]
C122  0.1uF  [SM-7351-CAP-0402]
C129  18pF  [SM-7351-CAP-0402]
C130  18pF  [SM-7351-CAP-0402]
C139  0.01uF  [SM-7351-CAP-0402]
C141  0.01uF  [SM-7351-CAP-0402]
C142  0.1uF  [SM-7351-CAP-0402]
C143  0.1uF  [SM-7351-CAP-0402]
C149  0.1uF  [SM-7351-CAP-0402]
C152  0.01uF  [SM-7351-CAP-0402]
C161  10uF  [SM-7351-CAP-0805]
C162  0.1uF  [SM-7351-CAP-0402]
C182  10uF  [SM-7351-CAP-0805]
C187  0.01uF  [SM-7351-CAP-0402]
D20  MMSD103T1  [sod-123]
FB2  600mAFB10ohm  [HF70ACB201209]
FB3  600mAFB10ohm  [HF70ACB201209]
FB4  600mAFB10ohm  [HF70ACB201209]
FB5  600mAFB10ohm  [HF70ACB201209]
J4  RJ-45 Gigabit  [CNRJ45-1X1WLED-598M]
J8  HEADER 2  [header_2x1]
Q9  FDT434P  [SOT223-4]
R21  0  [SM-7351-RES-0402]
R22  0  [SM-7351-RES-0402]
R32  12.1K, 1%  [SM-7351-RES-0402]
R45  1K  [SM-7351-RES-0402]
R53  1K  [SM-7351-RES-0402]
R66  1.5K  [SM-7351-RES-0402]
R102  22  [SM-7351-RES-0402]
R107  22  [SM-7351-RES-0402]
R121  22  [SM-7351-RES-0402]
R123  22  [SM-7351-RES-0402]
R269  220  [SM-7351-RES-0402]
R270  220  [SM-7351-RES-0402]
R307  1M  [SM-7351-RES-0402]
R308  0  [SM-7351-RES-0402]
R311  33  [SM-7351-RES-0402]
R312  33  [SM-7351-RES-0402]
R323  33  [SM-7351-RES-0402]
R336  10K  [SM-7351-RES-0402]
R345  10K  [SM-7351-RES-0402]
R353  4.7K  [SM-7351-RES-0402]
R357  0  [SM-7351-RES-0402]
R361  100K  [SM-7351-RES-0402]
R365  22  [SM-7351-RES-0402]
R366  1K  [SM-7351-RES-0402]
R367  22  [SM-7351-RES-0402]
R368  22  [SM-7351-RES-0402]
R369  1K  [SM-7351-RES-0402]
R370  22  [SM-7351-RES-0402]
R371  22  [SM-7351-RES-0402]
R372  1K  [SM-7351-RES-0402]
R373  22  [SM-7351-RES-0402]
R374  0  [SM-7351-RES-0402]
R392  10K  [SM-7351-RES-0402]
R393  10K  [SM-7351-RES-0402]
R394  1K  [SM-7351-RES-0402]
R395  10K  [SM-7351-RES-0402]
R396  10K  [SM-7351-RES-0402]
R397  1K  [SM-7351-RES-0402]
R398  1K  [SM-7351-RES-0402]
R399  10K  [SM-7351-RES-0402]
R400  10K  [SM-7351-RES-0402]
R401  0  [SM-7351-RES-0603]
R439  22  [SM-7351-RES-0402]
R442  22  [SM-7351-RES-0402]
TP18  TP1mm  [tp_smd1mmcircle]
U33  CDCE913  [TSSOP5X4-14-47M]
U37  KSZ9031RN  [qfn7x7-48]
U42  SN74LVC1G07  [u_5_dck]
Y2  25MHz  [SM_OSC_ABM3]
sheet Pg13: Industrial I/O
C3  0.022uF  [SM-7351-CAP-0402]
C4  0.022uF  [SM-7351-CAP-0402]
C5  0.022uF  [SM-7351-CAP-0402]
C6  0.022uF  [SM-7351-CAP-0402]
C7  0.022uF  [SM-7351-CAP-0402]
C8  0.022uF  [SM-7351-CAP-0402]
C9  0.022uF  [SM-7351-CAP-0402]
C10  0.022uF  [SM-7351-CAP-0402]
C16  0.01uF  [SM-7351-CAP-0402]
C18  0.01uF  [SM-7351-CAP-0402]
C19  1uF  [SM-7351-CAP-0402]
C23  10uF  [SM-7351-CAP-1206]
C24  0.01uF  [SM-7351-CAP-0402]
C128  2.2uF  [SM-7351-CAP-0805]
C138  2.2uF  [SM-7351-CAP-0805]
C154  0.001uF  [SM-7351-CAP-0402]
D3  Green LED  [sm_led_0805]
D4  Green LED  [sm_led_0805]
D5  Green LED  [sm_led_0805]
D6  Green LED  [sm_led_0805]
D7  Green LED  [sm_led_0805]
D8  Green LED  [sm_led_0805]
D9  Green LED  [sm_led_0805]
D10  Green LED  [sm_led_0805]
J1  Header 20x2 Female  [HDR2X20-335M]
R33  0  [SM-7351-RES-0402]
R34  0  [SM-7351-RES-0402]
R54  10K  [SM-7351-RES-0402]
R96  2.2K  [sm-7351-res-0402]
R97  0  [SM-7351-RES-0402]
R98  0  [SM-7351-RES-0402]
R99  0  [SM-7351-RES-0402]
R100  2.2K  [sm-7351-res-0402]
R105  0  [SM-7351-RES-0402]
R111  0  [SM-7351-RES-0402]
R280  150  [SM-7351-RES-0402]
R281  150  [SM-7351-RES-0402]
R282  150  [SM-7351-RES-0402]
R283  150  [SM-7351-RES-0402]
R284  150  [SM-7351-RES-0402]
R285  150  [SM-7351-RES-0402]
R286  150  [SM-7351-RES-0402]
R287  150  [SM-7351-RES-0402]
R288  1.2K, MELF  [smd_melf0102]
R289  1.2K, MELF  [smd_melf0102]
R290  1.2K, MELF  [smd_melf0102]
R291  1.2K, MELF  [smd_melf0102]
R292  1.2K, MELF  [smd_melf0102]
R293  1.2K, MELF  [smd_melf0102]
R294  1.2K, MELF  [smd_melf0102]
R295  1.2K, MELF  [smd_melf0102]
R322  25K  [SM-7351-RES-0603]
R338  49.9  [smd_melf0102]
R430  0  [SM-7351-RES-0402]
R432  0  [SM-7351-RES-0402]
R437  0  [SM-7351-RES-0402]
U4  SN65HVS882  [u_28_pwp]
U5  TPIC2810  [u_16_d]
U36  SN74LVC1G07  [u_5_dck]
sheet Pg14: Motor Driver
C87  0.47uF  [SM-7351-CAP-0402]
C94  0.01uF  [SM-7351-CAP-0402]
C99  0.1uF  [SM-7351-CAP-0402]
C100  0.47uF  [SM-7351-CAP-0402]
C303  10uF  [SM-7351-CAP-1206]
C326  0.1uF  [SM-7351-CAP-0402]
C327  0.1uF  [SM-7351-CAP-0402]
C337  0.1uF  [SM-7351-CAP-0402]
C339  10uF  [SM-7351-CAP-0805]
C340  100uF  [CAP-ALUM-D6XL7]
C348  47nF  [SM-7351-CAP-0402]
C349  47nF  [SM-7351-CAP-0402]
C350  47nF  [SM-7351-CAP-0402]
D15  Red LED  [sm_led_0805]
D17  MBRS140T  [mbrs140t]
D18  SMCJ26CA  [SMCJ26CA]
D22  MBRS140T  [mbrs140t]
J11  HEADER 2  [header_2x1]
J14  Connector_Screwdown  [conn_osttc02]
J17  Connector_Screwdown  [CNOSTTC03]
L1  4.7uH  [smd_slf7055t]
L2  4.7uH  [smd_slf7055t]
L3  4.7uH  [smd_slf7055t]
M17  Shunt0.1in  [DNP]
Q10  BSS84  [SOT23-3]
R60  0  [SM-7351-RES-0402]
R61  0  [SM-7351-RES-0402]
R62  0  [SM-7351-RES-0402]
R70  0  [SM-7351-RES-0402]
R80  0  [SM-7351-RES-0402]
R81  10K  [SM-7351-RES-0402]
R83  0  [SM-7351-RES-0402]
R132  0  [SM-7351-RES-0402]
R138  0  [SM-7351-RES-0402]
R183  220  [SM-7351-RES-0402]
R186  0  [SM-7351-RES-0402]
R187  0  [SM-7351-RES-0402]
R190  0  [SM-7351-RES-0603]
R213  4.99K  [SM-7351-RES-0402]
R214  402K  [SM-7351-RES-0402]
R215  0  [SM-7351-RES-0603]
R363  0  [SM-7351-RES-0402]
R364  0  [SM-7351-RES-0402]
R375  0  [SM-7351-RES-0402]
R495  4.99K  [SM-7351-RES-0402]
R496  4.99K  [SM-7351-RES-0402]
R536  0.02  [SM-7351-RES-1206]
R537  0.02  [SM-7351-RES-1206]
R538  0.02  [SM-7351-RES-1206]
R543  0  [SM-7351-RES-1210]
R553  4.99K  [SM-7351-RES-0402]
R554  4.99K  [SM-7351-RES-0402]
R555  4.99K  [SM-7351-RES-0402]
R558  0  [SM-7351-RES-0402]
R559  95.3K  [SM-7351-RES-0402]
R561  0  [SM-7351-RES-0402]
R562  95.3K  [SM-7351-RES-0402]
R563  0  [SM-7351-RES-0402]
R564  95.3K  [SM-7351-RES-0402]
TP15  TP  [TH_TP_5002]
U23  DRV8313  [htssop-28p-47m]
sheet Pg19: Expansion Connector
U11  AM437X_ZDN  [AM437X_ZDN]  (sections -1,-10,-11,-12,-13,-14,-15,-16,-17,-18,-19,-2,-20,-21,-22,-23,-24,-25,-3,-4,-5,-6,-7,-8,-9)

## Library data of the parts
C16-C18 C24 C29 C30 C32 C39 C40 C44 C47 C48 C52 C53 C58-C60 C62 C64 C66 C69 C77 C79 C94 C114 C139 C141 C152 C158-C160 C173 C179-C181 C184 C185 C187 C192 C193 C195 C197-C207 C210 C211 C213 C216 C217 C219-C221 C223 C224 C230 C231 C233 C234 C236 C240-C242 C252 C256 C343-C346 = 1C_0.01uFCapacitor16V10%0402
C21 C22 C28 C31 C43 C134 C161 C168 C172 C182 C189 C214 C229 C244 C257 C266 C276 C280 = 1C_10uFCapacitor16V10%0805
C19 C71 C191 C212 C218 = 1C_1uFCapacitor10V10%0402
FB1 FB6-FB11 FB14 = 1L_FerBead_180ohm200mA
R139 R142 R149 R190 R215 R273 R299 R358 R379 R401 R446 R448 R456 R463 R486 R488 = 1R_ZeroOhmResistor1_16W0603
R21 R22 R52 R60-R62 R70 R80 R83 R85 R97-R99 R105 R111 R132 R134 R136 R138 R140 R141 R146 R147 R150 R151 R153 R155 R186 R187 R296 R308 R324 R325 R354-R357 R359 R360 R363 R364 R374 R375 R419 R420 R425 R430-R432 R437 R438 R441 R443-R445 R447 R461 R466 R469 R473 R475 R482 R490 R558 R561 R563 = 1R_ZeroOhmResistor1_16W0402
SCKT1 = AM437X_ZDN_Processor_Socket
TP8 TP18-TP21 = 2H_Testpoint_SMD1mmCircle
C1 C51 C67 C88 C96 C97 C99 C121 C122 C253 C326 C327 C337 = 1C_0.1uFCapacitor50V10%0402
C11 C46 C72 C75 C82 = 1C_2200pFCapacitor50V10%SMD0402
C12 C45 C70 C74 C81 C95 C339 = 1C_10uFCapacitor35V10%0805
C27 C131 C271 = 1C_220uFCapacitor16V10%Tantalum
C98 C118 C171 C268 C273 = 1C_1uFCapacitor50V10%0603
C124 C175 C254 C269 C272 = 1C_22uFCapacitor16V10%0805
C144 C165 = 1C_10uFCapacitor6.3V20%0603
C26 C65 C142 C143 C148 C149 C157 C162 C194 C208 C215 C222 C232 C237 = 1C_0.1uFCapacitor16V10%0402
C322 C340 = 1C_100uFCapacitor35V20%ElecPoly
D1 D11 D13 D14 D16 = 1E_Diode_500mA30V
D2-D10 = 1F_LED_Green
D17 D19 D22 = 1E_Diode_MBRS140T3
D18 D21 = 1E_Diode_SMCJ26CA
F1 = 1P_Fuse_4A
J12 = 2J_Conn_PwrJack_RAPC722
J13 J14 = 2C_Conn_LeadScrewDown_2pin
L4 = 1L_47uHInductor20%1.6Asmd
L5 = 1L_1uHInductor20%4.5Asmd
L6 = 1L_100uHInductor20%450mAsmd
L7 = 1L_100uHInductor20%1.02Asmd
L8 = 1L_82uHInductor20%370mAsmd
L9 = 1L_47uHInductor20%720mAsmd
R14 = 1R_34KOhmResistor1_10W1%0402
R18 R94 R156 R175 R182 = 1R_51Kohm1_16W1%smd0402
R19 = 1R_4.75KohmResistor1_16W1%0402
R20 R311 R312 R323 = 1R_33ohmResistor1_16W5%0402
R93 = 1R_8.06Kohm1_16W1%smd0402
R95 R235 = 1R_60.4Kohm1_16W1%smd0402
R159 R173 = 1R_49.9KOhmResistor1_16W0402
R101 R106 R125 R131 R164 R302 R415 R480 R492 = 1R_49.9OhmResistor1_16W0402
R165 = 1R_16KOhmResistor1_16W1%0402
R166 = 1R_3.01KohmResistor1_16W1%0402
R176 = 1R_20.5Kohm1_16W1%smd0402
R181 = 1R_40.2Kohm1_16W1%smd0402
R184 = 1R_22Kohm1_16W1%SMD0402
R54 R81 R224 R228 R234 R237 R336 R345 R392 R393 R395 R396 R399 R400 R550 R551 R556 R557 = 1R_10KOhmResistor1_16W0402
R227 R230 = 1R_14KOhmResistor1_16W0402
R229 = 1R_24Kohm1_16W1%smd0402
R298 R491 = 1R_15Kohm1_16W1%smd0402
R409 = 1R_10KOhmResistor1_10W1%0402
R96 R100 R108 R122 R127 R130 R145 R418 R424 R452 R455 R462 = 1R_2.2KOhmResistor1_16W0402
R481 = 1R_18KohmResistor1_10W1%smd0402
TP1 TP7 TP9 TP11 TP14-TP16 = 2H_TestPointThroughHole
U3 U10 U14 U15 U17 = 1A_TPS5402
U26 = 1A_TPS386000
U29 U40 U52 U53 = 1A_TPS22922B
U35 = 1A_TPS62362
C188 = 1C_4700pFCapacitor50V10%0402
J9 = 2J_ConnectorRJ45_10_100MbAMDIX
R464 = 1R_4.87Kohm1_16W1%smd0402
U12 = 1A_TLK105L
U44 = SN74LVC1G08DCKT_SC70
C49 C50 = 1C_47uFCapacitor16V20%1206
C129 C130 = 1C_18pFCapacitor16V10%0402
D20 = Diode200mA250V
FB2-FB5 = 1L_FerriteBead_600mA10ohm
J4 = 2J_ConnectorRJ45_Gigabit
J8 J11 = 2H_Header_2x1
Q9 = 1Q_MOSFET_PChan_FDT434P
R32 = 1R_12.1KohmResistor1_16W1%0402
R45 R53 R366 R369 R372 R394 R397 R398 = 1R_1KOhmResistor1_16W0402
R66 = 1R_1.5KohmResistor1_16W5%0402
R102 R107 R121 R123 R365 R367 R368 R370 R371 R373 R439 R442 = 1R_22OhmResistor1_16W1%0402
R183 R269 R270 = 1R_220ohm1_10W1%smd0402
R307 = 1MOhmResistor1_16W0402
R353 = 1R_4.7KOhmResistor1_16W0402
R361 = 1R_100KOhmResistor1_16W0402
U33 = 1A_CDCE913
U37 = 1A_KSZ9031RNX
U36 U42 = 1A_SN74LVC1G07
Y2 = 1Y_Crystal25MHzABM3
C3-C10 = 1C_0.022uFCapacitor35Vsmd0402
C23 C303 = 1C_10uFCapacitor50V10%1206
C128 C138 = 1C_2.2uF16V10%SMD0805
C154 = 1C_0.001uFCapacitor50V5%0402
J1 = Header20x2_0.1in_Female
R33 R34 = ZeroOhmResistor1_16W0402
R280-R287 = 1R_150ohm1_16W1%SMD0402
R288-R295 = 1R_1.2Kohm1_3W1%SMDMELF0102
R322 = 1R_25Kohm1_10W0.1%smd0603
R338 = 49.9ohm1_3W1%SMDMELF0102
U4 = SN65HVS882
U5 = TPIC2810
C87 C100 = 1C_0.47uFCapacitor16V10%0402
C348-C350 = 1C_47nFCapacitor25V10%smd0402
D15 = 1F_LED_Red
J17 = 2C_Conn_LeadScrewDown_3pin
L1-L3 = 1L_4.7uHInductor30%3.1Asmd
M17 = 2H_Shunt0.1in
Q10 = 1Q_MOSFET_PChan_BSS84
R213 R495 R496 R553-R555 = 1R_4.99KOhmResistor1_16W0402
R214 = 1R_402Kohm1_16W1%smd0402
R536-R538 = 1R_0.02ohm1W1%smd1206
R543 = 1R_ZeroOhmResistor1_2W1210
R559 R562 R564 = 95.3KOhmResistor1_16W0402
U23 = 1A_DRV8313
U11 = am437x_ZDN_Industrial_EVM

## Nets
AGNDFRAME_PRUETH1: C188.2 J9.SHLD1 J9.SHLD2
DGND: C3.2 C4.2 C5.2 C6.2 C7.2 C8.2 C9.2 C10.2 C11.2 C12.2 C16.2 C17.2 C18.2 C19.2 C21.2 C22.2 C23.2 C24.2 C26.2 C27.2(NEG) C28.2 C29.2 C30.2 C31.2 C32.2 C39.2 C40.2 C43.2 C44.2 C45.2 C46.2 C47.2 C48.2 C49.2 C50.2 C52.2 C53.2 C58.2 C59.2 C60.2 C62.2 C64.2 C65.2 C66.2 C69.2 C70.2 C71.2 C72.2 C74.2 C75.2 C77.2 C79.2 C81.2 C82.2 C87.2 C95.2 C96.2 C97.2 C98.2 C100.2 C114.2 C118.2 C121.1 C122.1 C124.2 C128.2 C129.1 C130.1 C131.2(NEG) C134.2 C138.2 C139.2 C141.2 C142.2 C143.2 C144.2 C148.2 C149.2 C152.2 C154.2 C157.2 C158.2 C159.2 C160.2 C161.2 C162.2 C165.2 C168.2 C171.2 C172.2 C173.2 C175.2 C179.2 C180.2 C181.2 C182.2 C184.2 C185.2 C187.2 C188.1 C189.2 C191.2 C192.2 C193.2 C194.2 C195.2 C197.2 C198.2 C199.2 C200.2 C201.2 C202.2 C203.2 C204.2 C205.2 C206.2 C207.2 C208.2 C210.2 C211.2 C212.2 C213.2 C214.2 C215.2 C216.2 C218.2 C219.2 C220.2 C221.2 C222.2 C223.2 C224.2 C229.2 C230.2 C231.2 C232.2 C233.2 C234.2 C236.2 C237.2 C240.2 C241.2 C242.2 C244.2 C252.2 C254.2 C256.2 C257.2 C266.2 C268.2 C269.2 C271.2(NEG) C272.2 C273.2 C276.2 C280.2 C303.2 C322.2(NEG) C326.2 C327.2 C337.2 C339.2 C340.2(NEG) C343.2 C344.2 C345.2 C346.2 C348.2 C349.2 C350.2 D1.2(ANODE) D2.1(Cathode) D11.2(ANODE) D13.2(ANODE) D14.2(ANODE) D15.1(Cathode) D16.2(ANODE) D18.2(ANODE) D21.2(ANODE) D22.2(ANODE) J1.17 J1.29 J1.30 J4.1 J4.12 J4.13 J8.2 J9.8 J12.2 J12.3 J13.2 R18.1(P1) R19.2 R32.2 R33.1(P1) R34.1(P1) R45.1(P1) R53.1(P1) R81.1(P1) R93.2 R94.1(P1) R108.1(P1) R122.1(P1) R127.1(P1) R130.1(P1) R156.1(P1) R166.1(P1) R175.1(P1) R176.1(P1) R181.1(P1) R182.1(P1) R213.1(P1) R322.1(P1) R366.1(P1) R369.1(P1) R372.1(P1) R394.1(P1) R397.1(P1) R398.1(P1) R444.1(P1) R452.1(P1) R464.1(P1) R543.1(P1) R550.1(P1) R551.1(P1) R553.1(P1) R554.1(P1) R555.1(P1) R556.1(P1) R557.1(P1) TP1.1 TP9.1 TP11.1 TP16.1 U3.7(GND) U4.28(GND) U4.TH_PD(THRM) U5.7(A2) U5.8(~{G}) U5.9(A0) U5.10(A1) U5.16(GND) U10.7(GND) U11.A1(GND) U11.A25(GND) U11.AA23(TEST_EN) U11.AE1(GND) U11.AE25(GND) U11.H15(GND) U11.H18(GND) U11.J9(GND) U11.J12(GND) U11.J15(GND) U11.J17(GND) U11.K9(GND) U11.K11(GND) U11.K12(GND) U11.K14(GND) U11.K15(GND) U11.L8(GND) U11.L9(GND) U11.L11(GND) U11.L15(GND) U11.L17(GND) U11.L18(GND) U11.M10(GND) U11.M11(GND) U11.M13(GND) U11.M15(GND) U11.M16(GND) U11.N10(GND) U11.N11(GND) U11.N12(GND) U11.N13(GND) U11.N14(GND) U11.N15(GND) U11.P8(GND) U11.P9(GND) U11.P10(GND) U11.P11(GND) U11.P12(GND) U11.P13(GND) U11.P14(GND) U11.P15(GND) U11.R12(GND) U11.R15(GND) U11.R17(GND) U11.R18(GND) U11.T12(GND) U11.T15(GND) U11.T17(GND) U11.U8(GND) U11.U9(GND) U11.U10(GND) U11.U11(GND) U11.U12(GND) U11.U13(GND) U11.U14(GND) U11.U16(GND) U11.U17(GND) U11.U18(GND) U11.U19(GND) U11.V9(GND) U11.V10(GND) U11.V11(GND) U11.V12(GND) U11.V13(GND) U11.V14(GND) U11.V18(GND) U11.W23(VSSA_USB) U12.TPAD U14.7(GND) U15.7(GND) U17.7(GND) U23.14(GND) U23.20(GND) U23.28(GND) U23.TPAD U26.6(SENSE4H) U26.12(GND) U26.TPAD U29.C1(GND) U33.5(GND1) U33.10(GND2) U35.A2(AGND) U35.C1(SENSEM) U35.C3(PGND) U35.C4(PGND) U35.D4(PGND) U36.3(GND) U37.13(VSS_PS) U37.29(VSS) U37.49(P_GND) U40.C1(GND) U42.3(GND) U44.3(GND) U52.C1(GND) U53.C1(GND) ; also on sheet 1 2 3 4 5 6 8 15 16 17 18 19 20
GND_ETH1: C121.2 C122.2 J4.SHLD1 J4.SHLD2
GNDA_ADC: C217.2 J1.39 J1.40 R444.2(P2) U11.AC15(VSSA_ADC) ; also on sheet 1
V1_5D: C231.1 C233.1 C234.1 C236.1 C240.1 C241.1 C276.1 C280.1 R486.1(P1) U11.K7(VDD_DDR) U11.K8(VDD_DDR) U11.M7(VDD_DDR) U11.M8(VDD_DDR) U11.N7(VDD_DDR) U11.N8(VDD_DDR) U11.R6(VDD_DDR) U11.R7(VDD_DDR) U11.R8(VDD_DDR) U11.T7(VDD_DDR) U11.T8(VDD_DDR) U11.V7(VDD_DDR) U11.V8(VDD_DDR) ; also on sheet 8
V1_5DREG: C269.1 C273.1 L8.2 R480.2(P2) U52.A2(VIN) U52.B2(VIN)
V1_8D: C139.1 C168.1 FB1.2 R229.2(P2) R379.1(P1) U33.3(VDD) ; also on sheet 1 2 4
V1_8D_AM437X: C31.1 C32.1 C158.1 C159.1 C160.1 C192.1 FB1.1 FB6.2 FB8.1 FB9.1 FB10.1 FB11.2 FB14.2 R142.2(P2) R149.2(P2) U11.C23(VDDS_OSC)
V1_8DEN: R237.1(P1) R359.2(P2) R490.2(P2) U26.15(~{RESET1})
V1_8DREG: C171.1 C175.1 L6.2 R360.2(P2) R415.2(P2) U40.A2(VIN) U40.B2(VIN)
V3_3D: C18.1 C19.1 C64.1 C131.1(POS) C134.1 C141.1 C144.1 C148.1 C157.1 C185.1 C194.1 C208.1 FB5.1 FB7.2 Q10.S(SOURCE) R20.2 R54.2(P2) R96.2(P2) R100.2(P2) R101.1(P1) R106.1(P1) R125.1(P1) R131.1(P1) R145.2(P2) R235.1 R299.1(P1) R325.2(P2) R355.2(P2) R401.2(P2) R418.2(P2) R420.2(P2) R424.2(P2) R438.2(P2) R446.1(P1) R455.2(P2) R456.2(P2) R462.2(P2) R475.2(P2) R495.1(P1) U5.1(VCC) U12.21(VDD33_IO) U33.6(VDDOUT1) U33.7(VDDOUT2) U35.A1(AVIN) U35.A4(VIN) U35.D1(VDD) U44.5(VCC) ; also on sheet 2 3 4 5 6 8 15 16 17 18 19 20
V3_3D_AM437X: C47.1 C48.1 C52.1 C53.1 C59.1 C181.1 C184.1 C189.1 C193.1 C195.1 C201.1 C204.1 C223.1 C229.1 C252.1 C256.1 FB7.1 U11.F16(VDDSHV7) U11.F22(VDDSHV5) U11.G10(VDDSHV10) U11.G11(VDDSHV9) U11.G13(VDDSHV8) U11.G14(VDDSHV8) U11.G16(VDDSHV6) U11.G17(VDDSHV6) U11.H8(VDDSHV11) U11.H9(VDDSHV11) U11.H10(VDDSHV10) U11.H11(VDDSHV9) U11.H17(VDDSHV6) U11.J7(VDDSHV1) U11.J8(VDDSHV1) U11.J18(VDDSHV3) U11.K17(VDDSHV3) U11.K18(VDDSHV3) U11.N18(VDDSHV3) U11.N19(VDDSHV3) U11.P18(VDDSHV3) U11.U20(VDDA_3P3V_USB1) U11.V16(VDDSHV2) U11.V17(VDDSHV2) U11.W16(VDDSHV2) U11.W18(VDDSHV3) U11.W20(VDDA_3P3V_USB0)
V3_3D_PRUETH1JCK: C215.1 C222.1 J9.3 J9.4 R438.1(P1)
V3_3DREG: C114.1 C124.1 L4.2 R224.2(P2) R228.2(P2) R234.2(P2) R237.2(P2) R273.2(P2) R302.2(P2) U26.14(VCC) ; also on sheet 18
V3_3MTR: R190.2(P2) R214.2 R496.1(P1) ; also on sheet 1
V3_3MTRB: C87.1 R190.1(P1) U23.15(V3P3OUT)
V5_0D: C128.1 C254.1 J1.27 J1.28 L7.2 R164.2(P2) R280.1(P1) R281.1(P1) R282.1(P1) R283.1(P1) R284.1(P1) R285.1(P1) R286.1(P1) R287.1(P1) ; also on sheet 1 17 20
V5_0VOP: C16.1 C24.1 C138.1 U4.15(5VOP) U36.5(VCC)
V24_0D: C12.1 C45.1 C70.1 C74.1 C81.1 C95.1 C96.1 C97.1 C98.1 C154.1 C322.1(POS) D21.1(CATHODE) F1.2 J1.2 J1.4 J1.6 J1.8 J1.10 J1.12 J1.14 J1.16 J11.1 R338.2(P2) TP14.1 U3.2(VIN) U10.2(VIN) U14.2(VIN) U15.2(VIN) U17.2(VIN)
V24_0MTR: C99.1 C303.1 C326.1 C327.1 C337.1 C339.1 C340.1(POS) D17.1(CATHODE) D18.1(CATHODE) J11.2 TP15.1 U23.4(VM) U23.11(VM) ; also on sheet 1 20
VDD_CORE: C202.1 C205.1 C213.1 C219.1 C220.1 C221.1 C224.1 C230.1 C257.1 C266.1 C271.1(POS) R139.2(P2) R227.2(P2) R488.1(P1) U11.J10(VDD_CORE) U11.J11(VDD_CORE) U11.L12(VDD_CORE) U11.L14(VDD_CORE) U11.M9(VDD_CORE) U11.M12(VDD_CORE) U11.M14(VDD_CORE) U11.N9(VDD_CORE) U11.N16(VDD_CORE) U11.N17(VDD_CORE) U11.P16(VDD_CORE) U11.P17(VDD_CORE) U11.R9(VDD_CORE) U11.R11(VDD_CORE) U11.R14(VDD_CORE) U11.T9(VDD_CORE) U11.T11(VDD_CORE) U11.T14(VDD_CORE) U11.T18(VDD_CORE) U11.T19(VDD_CORE) U11.U15(VDD_CORE) U11.V15(VDD_CORE) U11.W12(VDD_CORE) U11.W13(VDD_CORE)
VDD_CORE_EN: R234.1(P1) R482.2(P2) U26.17(~{RESET3})
VDD_COREREG: C268.1 C272.1 L9.2 R492.2(P2) U53.A2(VIN) U53.B2(VIN)
VDD_MPU: C27.1(POS) C39.1 C40.1 C172.1 C197.1 C203.1 C207.1 R230.2(P2) R358.1(P1) TP7.1 U11.H13(VDD_MPU) U11.H14(VDD_MPU) U11.H16(VDD_MPU) U11.J13(VDD_MPU) U11.J14(VDD_MPU) U11.J16(VDD_MPU) U11.K19(VDD_MPU) U11.K20(VDD_MPU) U11.L19(VDD_MPU) U11.L20(VDD_MPU) U11.M17(VDD_MPU) U11.M18(VDD_MPU)
VDD_MPU_EN: R228.1(P1) R324.2(P2) U26.18(~{RESET4})
VDD_MPU_OUT: L5.1 U35.B3(SW) U35.B4(SW)
VDD_MPU_SENSE: C165.1 L5.2 R52.1(P1) R358.2(P2)
VDD_MPU_SENSEP: R52.2(P2) U35.B1(SENSEP)
VDD_TAMPER: C60.1 R139.1(P1) U11.AD9(VDD_TPM)
VDDA1P8_PMLDO: R463.1(P1) U11.D6(VDDA1P8_PMLDO)
VDDA3P3_PMLDO: R456.1(P1) U11.F8(VDDA3P3_PMLDO)
VDDA_ADC: C217.1 FB14.1 U11.AB12(VDDA_TS_ADC)
VDDA_MC_ADC: C211.1 FB11.1 U11.Y16(VDDA_MC_ADC)
VDDS_CTM: FB6.1 U11.AD12(VDDS_CTM)
VDDS_TAMPER: C62.1 R142.1(P1) U11.AD8(VDDS_TPM)
AM437X_AIN0: J1.31 ; also on sheet 1
AM437X_AIN1: J1.33 ; also on sheet 1
AM437X_AIN2: J1.35 ; also on sheet 1
AM437X_AIN3: J1.37 ; also on sheet 1
AM437X_AIN4: J1.32 ; also on sheet 1
AM437X_AIN5: J1.34 ; also on sheet 1
AM437X_AIN6: J1.36 ; also on sheet 1
AM437X_AIN7: J1.38 ; also on sheet 1
AM437X_CAM0_DATA1: R375.2(P2) U11.AB18(CAM0_DATA1/eHRPWM3_SYNCO) ; also on sheet 2 17
AM437X_CAM0_DATA4: R364.1(P1) U11.AE19(CAM0_DATA4/eHRPWM3A) ; also on sheet 2
AM437X_CAM0_DATA5: R363.1(P1) U11.AD19(CAM0_DATA5/eHRPWM3B) ; also on sheet 2
AM437X_CAM1_DATA6: R431.2(P2) ; also on sheet 15 17
AM437X_CAM1_DATA8: R80.1(P1) U11.AD24(CAM1_DATA8/GPIO) ; also on sheet 17
AM437X_eHRPWM0B: R83.1(P1) U11.AC23(CAM1_VSYNC/eHRPWM0B) ; also on sheet 17
AM437X_eHRPWM1B: R375.1(P1) U11.AC25(CAM1_FIELD/EXT_HW_TRIG) ; also on sheet 17
AM437X_eHRPWM4A: R70.1(P1) U11.H25(UART3_RXD/eHRPWM4A)
AM437X_eHRPWM4B: R187.1(P1) U11.H24(UART3_TXD/eHRPWM4B)
AM437X_eHRPWM5A: R132.1(P1) U11.H22(UART3_CTSn/eHRPWM5A)
AM437X_GPIO_IND_LDn: R105.2(P2) U11.B14(MII1_CRS/SPI1_GPIO)
AM437x_HDQ: R138.1(P1) U11.K24(UART3_RTSn/eHRPWM5B) ; also on sheet 17
AM437X_I2C0_SCL: R356.2(P2) R424.1(P1) R425.2(P2) U11.Y22(I2C_SCL0)
AM437X_I2C0_SDA: R354.2(P2) R418.1(P1) R419.2(P2) U11.AB24(I2C_SDA0)
AM437X_I2C2_SCL: R96.1(P1) R97.2(P2) R430.2(P2) U11.AC21(CAM1_DATA1/I2C2_SCL)
AM437X_I2C2_SDA: R98.2(P2) R100.1(P1) R432.2(P2) U11.AB20(CAM1_DATA0/I2C2_DTA)
AM437X_PRUETH1_MRCLK: R466.2(P2) U11.F6(GPMC_A7/PR1_MII1_MR1_CLK) ; also on sheet 17
AM437X_PRUETH1_RXD0: R447.2(P2) U11.D8(GPMC_A11/MCASP0_D1)
AM437X_PRUETH1_RXD1: R445.2(P2) U11.G8(GPMC_A10/MCASP0_D0)
AM437X_PRUETH1_RXD2: R443.2(P2) U11.B4(GPMC_A9/MCASP0_FSX)
AM437X_PRUETH1_RXD3: R441.2(P2) U11.F7(GPMC_A8/MCASP0_ACLKX)
AM437X_PRUETH1_RXDV: R461.2(P2) U11.C5(GPMC_A1/PR1_MII1_RXDV) ; also on sheet 15
AM437X_PRUETH1_RXER: R136.2(P2) U11.B3(GPMC_WPn/PR1_MII1_RXER)
AM437X_PRUETH1_TXCLK: R141.2(P2) U11.E8(GPMC_A6/PR1_MII1_MT1_CLK) ; also on sheet 17
AM437X_PRUETH1_TXD0: R469.2(P2) U11.E7(GPMC_A5/PR1_MII1_TXD0) ; also on sheet 17
AM437X_PRUETH1_TXD1: R150.2(P2) U11.D7(GPMC_A4/PR1_MII1_TXD1) ; also on sheet 17
AM437X_PRUETH1_TXD2: R153.2(P2) U11.A4(GPMC_A3/PR1_MII1_TXD2)
AM437X_PRUETH1_TXD3: R151.2(P2) U11.C6(GPMC_A2/PR1_MII1_TXD3)
AM437X_PRUETH1_TXEN: R155.2(P2) U11.C3(GPMC_A0/PR1_MII1_TXEN) ; also on sheet 15
AM437X_PRUETH_MDCLK: R147.2(P2) U11.A12(GPMC_CLK/PR1_MDCLK) ; also on sheet 15
AM437X_PRUETH_MDDATA: R146.2(P2) U11.D24(XDMA_EVENT_INTR0/PR1_MDIO) ; also on sheet 15
AM437X_RGMII1_RD0: R370.2(P2) U11.F17(MII1_RXD0/RGMII1_RD0)
AM437X_RGMII1_RD1: R368.2(P2) U11.B16(MII1_RXD1/RGMII1_RD1)
AM437X_RGMII1_RD2: R367.2(P2) U11.E16(MII1_RXD2/RGMII1_RD2)
AM437X_RGMII1_RD3: R365.2(P2) U11.C14(MII1_RXD3/RGMII1_RD3)
AM437X_RGMII1_RXCLK: R373.2(P2) U11.D13(MII1_RXCLK/RGMII1_RCLK)
AM437X_RGMII1_RXCTL: R371.2(P2) U11.A15(MII1_RXDV/RGMII1_RXCTL)
AM437X_RGMII1_TD0: R102.2(P2) U11.B15(MII1_TXD0/RGMII1_TD0)
AM437X_RGMII1_TD1: R107.2(P2) U11.A14(MII1_TXD1/RGMII1_TD1)
AM437X_RGMII1_TD2: R123.2(P2) U11.C13(MII1_TXD2/RGMII1_TD2)
AM437X_RGMII1_TD3: R439.2(P2) U11.C16(MII1_TXD3/RGMII1_TD3)
AM437X_RGMII1_TXCLK: R442.2(P2) U11.D14(MII1_TXCLK/RGMII1_TXCLK)
AM437X_RGMII1_TXCTL: R121.2(P2) U11.A13(MII1_TXEN/RGMII1_TXCTL)
AM437X_SPI1_CS0: R99.2(P2) U11.A16(RMII1_REFCLK/SPI1_CS0n)
AM437X_SPI1_D1: R111.2(P2) U11.B13(MII1_RXERR/SPI1_D1)
AM437X_SPI1_SCLK: R437.2(P2) U11.D16(MII1_COL/SPI1_SCLK)
AM437X_VDDS: C199.1 C200.1 C210.1 C214.1 C216.1 R463.2(P2) U11.F20(VDDS) U11.G6(VDDS) U11.H12(VDDS) U11.P19(VDDS) U11.W15(VDDS) U11.Y19(VDDS)
CAP_VDD_RTC: C71.1 U11.AD3(CAP_VDD_RTC)
DRAIN0: D3.1(Cathode) J1.19 U5.3(DRAIN0)
DRAIN1: D4.1(Cathode) J1.20 U5.4(DRAIN1)
DRAIN2: D5.1(Cathode) J1.21 U5.5(DRAIN2)
DRAIN3: D6.1(Cathode) J1.22 U5.6(DRAIN3)
DRAIN4: D7.1(Cathode) J1.23 U5.11(DRAIN4)
DRAIN5: D8.1(Cathode) J1.24 U5.12(DRAIN5)
DRAIN6: D9.1(Cathode) J1.25 U5.13(DRAIN6)
DRAIN7: D10.1(Cathode) J1.26 U5.14(DRAIN7)
ETH1_LDO_O: Q9.G(GATE) U37.43(LDO_O)
ETH1_MDC: R374.1(P1) U37.36(MDC)
ETH1_MDIO: R357.1(P1) U37.37(MDIO)
ETH1_RESETn: C161.1 D20.2(Anode) R361.1(P1) U37.42(RESET_N) U42.4(Y)
ETH1_RXCLK: R372.2(P2) R373.1(P1) R400.2(P2) U37.35(RX_CLK)
ETH1_RXD0: R370.1(P1) R396.2(P2) R397.2(P2) U37.32(RXD0)
ETH1_RXD1: R368.1(P1) R369.2(P2) R395.2(P2) U37.31(RXD1)
ETH1_RXD2: R367.1(P1) R393.2(P2) R394.2(P2) U37.28(RXD2)
ETH1_RXD3: R365.1(P1) R366.2(P2) R392.2(P2) U37.27(RXD3)
ETH1_RXDV: R371.1(P1) R398.2(P2) R399.2(P2) U37.33(RX_DV)
ETH1_TXCLK: R442.1(P1) U37.24(GTX_CLK)
ETH1_TXD0: R102.1(P1) U37.19(TXD0)
ETH1_TXD1: R107.1(P1) U37.20(TXD1)
ETH1_TXD2: R123.1(P1) U37.21(TXD2)
ETH1_TXD3: R439.1(P1) U37.22(TXD3)
ETH1_TXEN: R121.1(P1) U37.25(TX_EN)
ETH1GB_25MHzCLK: R323.2 U37.46(XI)
ETH_MDIO_CLK: R374.2(P2) U11.B17(MDIO_CLK/MDIO_CLK)
ETH_MDIO_DATA: R66.1(P1) R357.2(P2) U11.A17(MDIO_DATA/MDIO_DATA)
ETHER1_D0N: J4.10 U37.3(TXRXM_A)
ETHER1_D0P: J4.9 U37.2(TXRXP_A)
ETHER1_D1N: J4.8 U37.6(TXRXM_B)
ETHER1_D1P: J4.7 U37.5(TXRXP_B)
ETHER1_D2N: J4.6 U37.8(TXRXM_C)
ETHER1_D2P: J4.5 U37.7(TXRXP_C)
ETHER1_D3N: J4.4 U37.11(TXRXM_D)
ETHER1_D3P: J4.3 U37.10(TXRXP_D)
GP_I2C_SCL: R22.2(P2) R425.1(P1) ; also on sheet 2 6
GP_I2C_SDA: R21.2(P2) R419.1(P1) ; also on sheet 2 6
IND_I2C_SCL: R430.1(P1) ; also on sheet 17
IND_I2C_SDA: R432.1(P1) ; also on sheet 17
INDUS_INPUT0: J1.1 R295.1(P1)
INDUS_INPUT1: J1.3 R294.1(P1)
INDUS_INPUT2: J1.5 R293.1(P1)
INDUS_INPUT3: J1.7 R292.1(P1)
INDUS_INPUT4: J1.9 R291.1(P1)
INDUS_INPUT5: J1.11 R290.1(P1)
INDUS_INPUT6: J1.13 R289.1(P1)
INDUS_INPUT7: J1.15 R288.1(P1)
INDUS_INPUTCLK: R437.1(P1) U4.25(CLK)
INDUS_INPUTCSn: R99.1(P1) U4.24(~{CE})
INDUS_INPUTLDn: R105.1(P1) U4.26(~{LD})
INDUS_INPUTSO: U4.23(SOP) U36.2(A)
MOT1_ADC: R561.2(P2) ; also on sheet 1
MOT1_LEVEL: C349.1 R554.2(P2) R561.1(P1) R562.1(P1)
MOT2_ADC: R563.2(P2) ; also on sheet 1
MOT2_LEVEL: C350.1 R555.2(P2) R563.1(P1) R564.1(P1)
MOT3_ADC: R558.2(P2) ; also on sheet 1
MOT3_LEVEL: C348.1 R553.2(P2) R558.1(P1) R559.1(P1)
MOT_OUT1: L2.1 U23.5(OUT1)
MOT_OUT2: L3.1 U23.8(OUT2)
MOT_OUT3: L1.1 U23.9(OUT3)
MOT_PGND1: R538.1 U23.6(PGND1) ; also on sheet 1
MOT_PGND2: R537.1 U23.7(PGND2) ; also on sheet 1
MOT_PGND3: R536.1 U23.10(PGND3) ; also on sheet 1
MOT_PGNDTOTAL: R215.1(P1) R536.2 R537.2 R538.2 R543.2(P2) ; also on sheet 1
MOTOR_OUT1: J17.1 L2.2 R562.2(P2)
MOTOR_OUT2: J17.2 L3.2 R564.2(P2)
MOTOR_OUT3: J17.3 L1.2 R559.2(P2)
MTR_FAULT: Q10.G(GATE) R60.2(P2) R61.2(P2) R62.2(P2) R186.1(P1) R495.2(P2) U11.F11(GPMC_AD10/GPIO) U23.18(~{FAULT}) ; also on sheet 17
PHY1_LED_ACTn: R53.2(P2) R270.1 R345.2(P2) U37.17(LED1_/_PME_N1)
PHY1_LED_LINKn: R45.2(P2) R269.1 R336.2(P2) U37.15(LED2)
PORZ_RELEASE: U26.16(~{RESET2}) ; also on sheet 18
PRUETH0_25MHzCLK: R311.2 ; also on sheet 15
PRUETH1_25MHzCLK: R312.2 U12.23(XI)
PRUETH1_COL: R85.1(P1) R134.2(P2) R452.2(P2) R455.1(P1) R473.1(P1) U12.29(COL)
PRUETH1_CRS: R140.1(P1) U12.27(CRS)
PRUETH1_INT: TP8.1 U12.8(PWRDNn/INTn)
PRUETH1_LINKLED: R145.1(P1) R448.2(P2) U12.17(LED_LINK)
PRUETH1_MDC: R147.1(P1) U12.20(MDC)
PRUETH1_MDIO: R146.1(P1) R462.1(P1) U12.19(MDIO)
PRUETH1_RESETn: U12.18(RESET_N) U44.4(Y)
PRUETH1_RXCLK: R466.1(P1) U12.25(RX_CLK)
PRUETH1_RXD0: R130.2(P2) R447.1(P1) U12.30(RXD_0)
PRUETH1_RXD1: R127.2(P2) R445.1(P1) U12.31(RXD_1)
PRUETH1_RXD2: R122.2(P2) R443.1(P1) U12.32(RXD_2)
PRUETH1_RXD3: R108.2(P2) R441.1(P1) U12.1(RXD_3)
PRUETH1_RXDV: R461.1(P1) U12.26(RX_DV)
PRUETH1_RXERR: R136.1(P1) U12.28(RX_ERR)
PRUETH1_TXCLK: R141.1(P1) U12.2(TX_CLK)
PRUETH1_TXD0: R469.1(P1) U12.4(TXD_0)
PRUETH1_TXD1: R150.1(P1) U12.5(TXD_1)
PRUETH1_TXD2: R153.1(P1) U12.6(TXD_2)
PRUETH1_TXD3: R151.1(P1) U12.7(TXD_3)
PRUETH1_TXEN: R155.1(P1) U12.3(TX_EN)
PRUETHER1_RDN: J9.6 R101.2(P2) U12.9(RD-)
PRUETHER1_RDP: J9.5 R106.2(P2) U12.10(RD+)
PRUETHER1_TDN: J9.2 R125.2(P2) U12.11(TD-)
PRUETHER1_TDP: J9.1 R131.2(P2) U12.12(TD+)
SYS_RESETn: U42.2(A) U44.2(B) ; also on sheet 6 15 17 18 19
VADD33_PRUETH1: C58.1 R446.2(P2) U12.14(AVDD33)
VETH1_AVDDH: C50.1 C142.1 C182.1 FB5.2 Q9.S(SOURCE) U37.1(AVDDH) U37.12(AVDDH) U37.47(AVDDH)
VETH1_AVDDL: C21.1 C143.1 FB2.2 U37.4(AVDDL) U37.9(AVDDL)
VETH1_AVDDL_PLL: C22.1 C26.1 C152.1 FB3.2 U37.44(AVDDL_PLL)
VETH1_AVDDL_PMOS: C49.1 FB2.1 FB3.1 FB4.1 Q9.D1(DRAIN1) Q9.D2(DRAIN2)
VETH1_DVDDH: C43.1 C149.1 C187.1 D20.1(Cathode) R66.2(P2) R336.1(P1) R345.1(P1) R353.2(P2) R361.2(P2) R392.1(P1) R393.1(P1) R395.1(P1) R396.1(P1) R399.1(P1) R400.1(P1) R401.1(P1) U37.16(DVDDH) U37.34(DVDDH) U37.40(DVDDH) U42.5(VCC)
VETH1_DVDDL: C28.1 C162.1 FB4.2 U37.14(DVDDL) U37.18(DVDDL) U37.23(DVDDL) U37.26(DVDDL) U37.30(DVDDL) U37.39(DVDDL)
VMTR_PWRIN: D17.2(ANODE) J14.1
VPWRIN_JCK: D19.2(ANODE) J12.1 J13.1
VPWRIN_PREFUSE: D19.1(CATHODE) F1.1
N12081710: J8.1 R353.1(P1) U37.38(INT_N_/_PME_N2)
N12123192: J4.11 R270.2
N12123204: J4.14 R269.2
N12138943: R32.1 U37.48(ISET)
N12139138: TP18.1 U37.41(CLK125_NDO)
N12225140: J9.11 R420.1(P1)
N12225158: C65.1 C232.1 C237.1 C244.1 U12.13(PFBIN1) U12.15(PFBOUT) U12.24(PFBIN2)
N12225278: J9.10 R134.1(P1)
N12225708: R473.2(P2) U11.A3(GPMC_BE1n/PR1_MII1_COL)
N12225872: R85.2(P2) U11.E24(PRINT_ON/PR1_MII1_RXLINK)
N12226470: J9.9 R475.1(P1)
N12226600: R431.1(P1) U44.1(A)
N14814629: C212.1 U11.E13(CAP_VDD_SRAM_CORE)
N14814645: C218.1 U11.E14(CAP_VDD_SRAM_MPU)
N14814653: C191.1 U11.F19(CAP_VBB_MPU)
N14814919: C29.1 C30.1 FB8.2 U11.U21(VDDA1P8V_USB1) U11.W21(VDDA1P8V_USB0)
N15910922: R140.2(P2) U11.F23(PRINT_MB/PR1_MII1_CRS)
N15911835: R464.2(P2) U12.16(RBIAS)
N15980233: C94.1 U23.1(CP1)
N15980235: C94.2 U23.2(CP2)
N15980277: C100.1 R213.2(P2) R214.1 U23.13(COMPN)
N15980287: R186.2(P2) R496.2(P2) U23.19(COMPOn)
N15980309: R215.2(P2) U23.12(COMPP)
N15980493: D15.2(Anode) R183.1
N15980497: Q10.D(DRAIN) R183.2
N15980559: R83.2(P2) U23.17(~{SLEEPn})
N16086432: R324.1(P1) U35.B2(EN)
N16086456: R356.1(P1) U35.D3(SCL)
N16086460: R354.1(P1) U35.D2(SDA)
N16086926: R325.1(P1) U35.A3(VSEL1)
N16086934: R355.1(P1) U35.C2(VSEL0)
N16087451: C1.1 U3.1(BOOT)
N16087466: C1.2 D1.1(CATHODE) L4.1 U3.8(LX)
N16087487: R18.2(P2) U3.3(ROSC)
N16087773: C17.1 U3.4(SS)
N16088130: R14.2(P2) U3.6(COMP)
N16088430: R19.1 R298.1(P1) U3.5(VSNS)
N16251668: R97.1(P1) U5.15(SCL)
N16251678: R98.1(P1) U5.2(SDA)
N16279225: C179.1 C180.1 C198.1 C206.1 C242.1 FB10.2 U11.E17(VDDS_PLL_MPU) U11.F13(VDDS_SRAM_CORE_BG) U11.F14(VDDS_SRAM_MPU_BB) U11.G5(VDDS_PLL_DDR) U11.N21(VDDS_PLL_CORE_LCD)
N16281493: TP19.1 U11.H21(TESTOUT)
N16283418: C11.1 R14.1(P1)
N16286128: C51.2 D11.1(CATHODE) L6.1 U10.8(LX)
N16286350: C51.1 U10.1(BOOT)
N16286370: R94.2(P2) U10.3(ROSC)
N16286398: C44.1 U10.4(SS)
N16286420: R95.1 U10.6(COMP)
N16286444: R93.1 R409.1 U10.5(VSNS)
N16286506: C46.1 R95.2
N16287061: C67.2 D13.1(CATHODE) L8.1 U15.8(LX)
N16287283: C67.1 U15.1(BOOT)
N16287303: R175.2(P2) U15.3(ROSC)
N16287331: C77.1 U15.4(SS)
N16287353: R173.2(P2) U15.6(COMP)
N16287439: C75.1 R173.1(P1)
N16288012: C88.2 D16.1(CATHODE) L9.1 U17.8(LX)
N16288234: C88.1 U17.1(BOOT)
N16288254: R182.2(P2) U17.3(ROSC)
N16288282: C79.1 U17.4(SS)
N16288304: R184.2(P2) U17.6(COMP)
N16288328: R181.2(P2) R491.1(P1) U17.5(VSNS)
N16288390: C82.1 R184.1(P1)
N16700927: J9.12 R448.1(P1)
N16738182: R176.2(P2) R481.1(P1) U15.5(VSNS)
N16738683: R486.2(P2) U52.A1(VOUT) U52.B1(VOUT)
N16738880: R490.1(P1) U52.C2(ON)
N16739248: R488.2(P2) U53.A1(VOUT) U53.B1(VOUT)
N16739276: R482.1(P1) U53.C2(ON)
N16740119: R379.2(P2) U40.A1(VOUT) U40.B1(VOUT)
N16740147: R359.1(P1) R360.1(P1) U40.C2(ON)
N16740391: R224.1(P1) U26.1(~{MR})
N16743008: C343.1 U26.2(CT4)
N16743015: C344.1 U26.3(CT3)
N16743022: C345.1 U26.4(CT2)
N16743029: C346.1 U26.5(CT1)
N16744367: R230.1(P1) R556.2(P2) U26.9(SENSE2)
N16744371: R229.1(P1) R551.2(P2) U26.8(SENSE3)
N16744375: R227.1(P1) R550.2(P2) U26.7(SENSE4L)
N16744379: R235.2 R557.2(P2) U26.10(SENSE1)
N16782266: C173.1 FB9.2 U11.E23(VDDS_CLKOUT)
N16839102: C23.1 R338.1(P1) U4.14(VCC)
N16839202: R322.2(P2) U4.13(RLIM)
N16839209: R34.2(P2) U4.2(DB1)
N16839216: R33.2(P2) U4.1(DB0)
N16844891: D4.2(Anode) R286.2(P2)
N16844892: D9.2(Anode) R281.2(P2)
N16844893: D10.2(Anode) R280.2(P2)
N16844894: D7.2(Anode) R283.2(P2)
N16844899: D8.2(Anode) R282.2(P2)
N16844909: D3.2(Anode) R287.2(P2)
N16844924: D6.2(Anode) R284.2(P2)
N16844930: D5.2(Anode) R285.2(P2)
N16898152: R298.2(P2) R302.1(P1)
N16899204: R409.2 R415.1(P1)
N16899853: R480.1(P1) R481.2(P2)
N16900690: R491.2(P2) R492.1(P1)
N17007255: R54.1(P1) R111.1(P1) U36.4(Y)
N17015946: D22.1(CATHODE) J14.2
N17049952: C253.2 D14.1(CATHODE) L7.1 U14.8(LX)
N17050053: R165.1 R166.2(P2) U14.5(VSNS)
N17050067: R164.1(P1) R165.2
N17050085: C253.1 U14.1(BOOT)
N17050095: R156.2(P2) U14.3(ROSC)
N17050109: C69.1 U14.4(SS)
N17050128: R159.2(P2) U14.6(COMP)
N17050161: C72.1 R159.1(P1)
N17134629: R299.2(P2) U29.A1(VOUT) U29.B1(VOUT)
N17135096: C118.1 R273.1(P1) R296.1(P1) U29.A2(VIN) U29.B2(VIN)
N17135910: R296.2(P2) U29.C2(ON)
N17156111: C129.2 R307.2(P2) U33.1(Xin/CLK) Y2.2
N17156113: C130.2 R307.1(P1) R308.2(P2) Y2.1
N17156222: R308.1(P1) U33.14(XOUT)
N17156522: R311.1 U33.11(Y1)
N17156525: R312.1 U33.9(Y2)
N17156528: R323.1 U33.8(Y3)
N17156983: R22.1(P1) U33.12(S2/SCL)
N17156986: R21.1(P1) U33.13(S1/SDA)
N17183635: R364.2(P2) U23.27(IN1)
N17183685: R70.2(P2) U23.25(IN2)
N17184172: R80.2(P2) R81.2(P2) U23.16(~{RESETn})
N17340888: TP21.1 U11.D20(VDD_MPU_MON)
N17722224: D2.2(Anode) R20.1
N17839489: R187.2(P2) U23.24(EN2)
N17852592: R132.2(P2) U23.23(IN3)
N17852603: R138.2(P2) U23.22(EN3)
N17942790: TP20.1 U11.P21(VPP)
N17944182: C66.1 R149.1(P1) U11.AD5(VDDS_RTC)
N18051330: R62.1(P1) U11.N20(SPI2_SCLK/eHRPWM4_TRIPZONE)
N18051447: R61.1(P1) U11.N25(SPI4_CS0/eHRPWM3_TRIPZONE)
N18051467: R60.1(P1) U11.P22(SPI2_D0/eHRPWM5_TRIPZONE)
N18167698: C99.2 U23.3(VCP)
N18182281: R363.2(P2) U23.26(EN1)
N21620210: C3.1 R295.2(P2) U4.3(IP0)
N21620213: C4.1 R294.2(P2) U4.5(IP1)
N21620216: C5.1 R293.2(P2) U4.7(IP2)
N21620219: C6.1 R292.2(P2) U4.9(IP3)
N21620222: C7.1 R291.2(P2) U4.11(IP4)
N21620225: C8.1 R290.2(P2) U4.18(IP5)
N21620228: C9.1 R289.2(P2) U4.20(IP6)
N21620231: C10.1 R288.2(P2) U4.22(IP7)

Not connected (* = marked no-connect by the designer): J1 18*; J4 2; J9 7; SCKT1 MCH1* MCH2* MCH3* MCH4*; U4 4(RE0)* 6(RE1)* 8(RE2)* 10(RE3)* 12(RE4)* 16(TOK)* 17(RE5)* 19(RE6)* 21(RE7)* 27(SIP)*; U12 22(XO)*; U23 21(NC)*; U26 11(NC)* 13(VREF)* 19(~{WDO})* 20(WDI)*; U33 2(S0)* 4(Vctr)*; U36 1(NC)*; U37 45(XO)*; U42 1(NC)*

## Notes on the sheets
sheet 10
- Motor Drive
- Motor 24VDC Power Input
sheet 11
- Main 24VDC Power Input
sheet 12
- Industrial INPUTS
- Digital OUTPUTS
- I/O Expansion Header
sheet 14
- Note: MDIO Address = 0x01
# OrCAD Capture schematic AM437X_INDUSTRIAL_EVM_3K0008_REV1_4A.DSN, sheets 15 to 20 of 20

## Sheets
15 Pg07: ICSS Ethernet 0: size C; note: ARM MPU
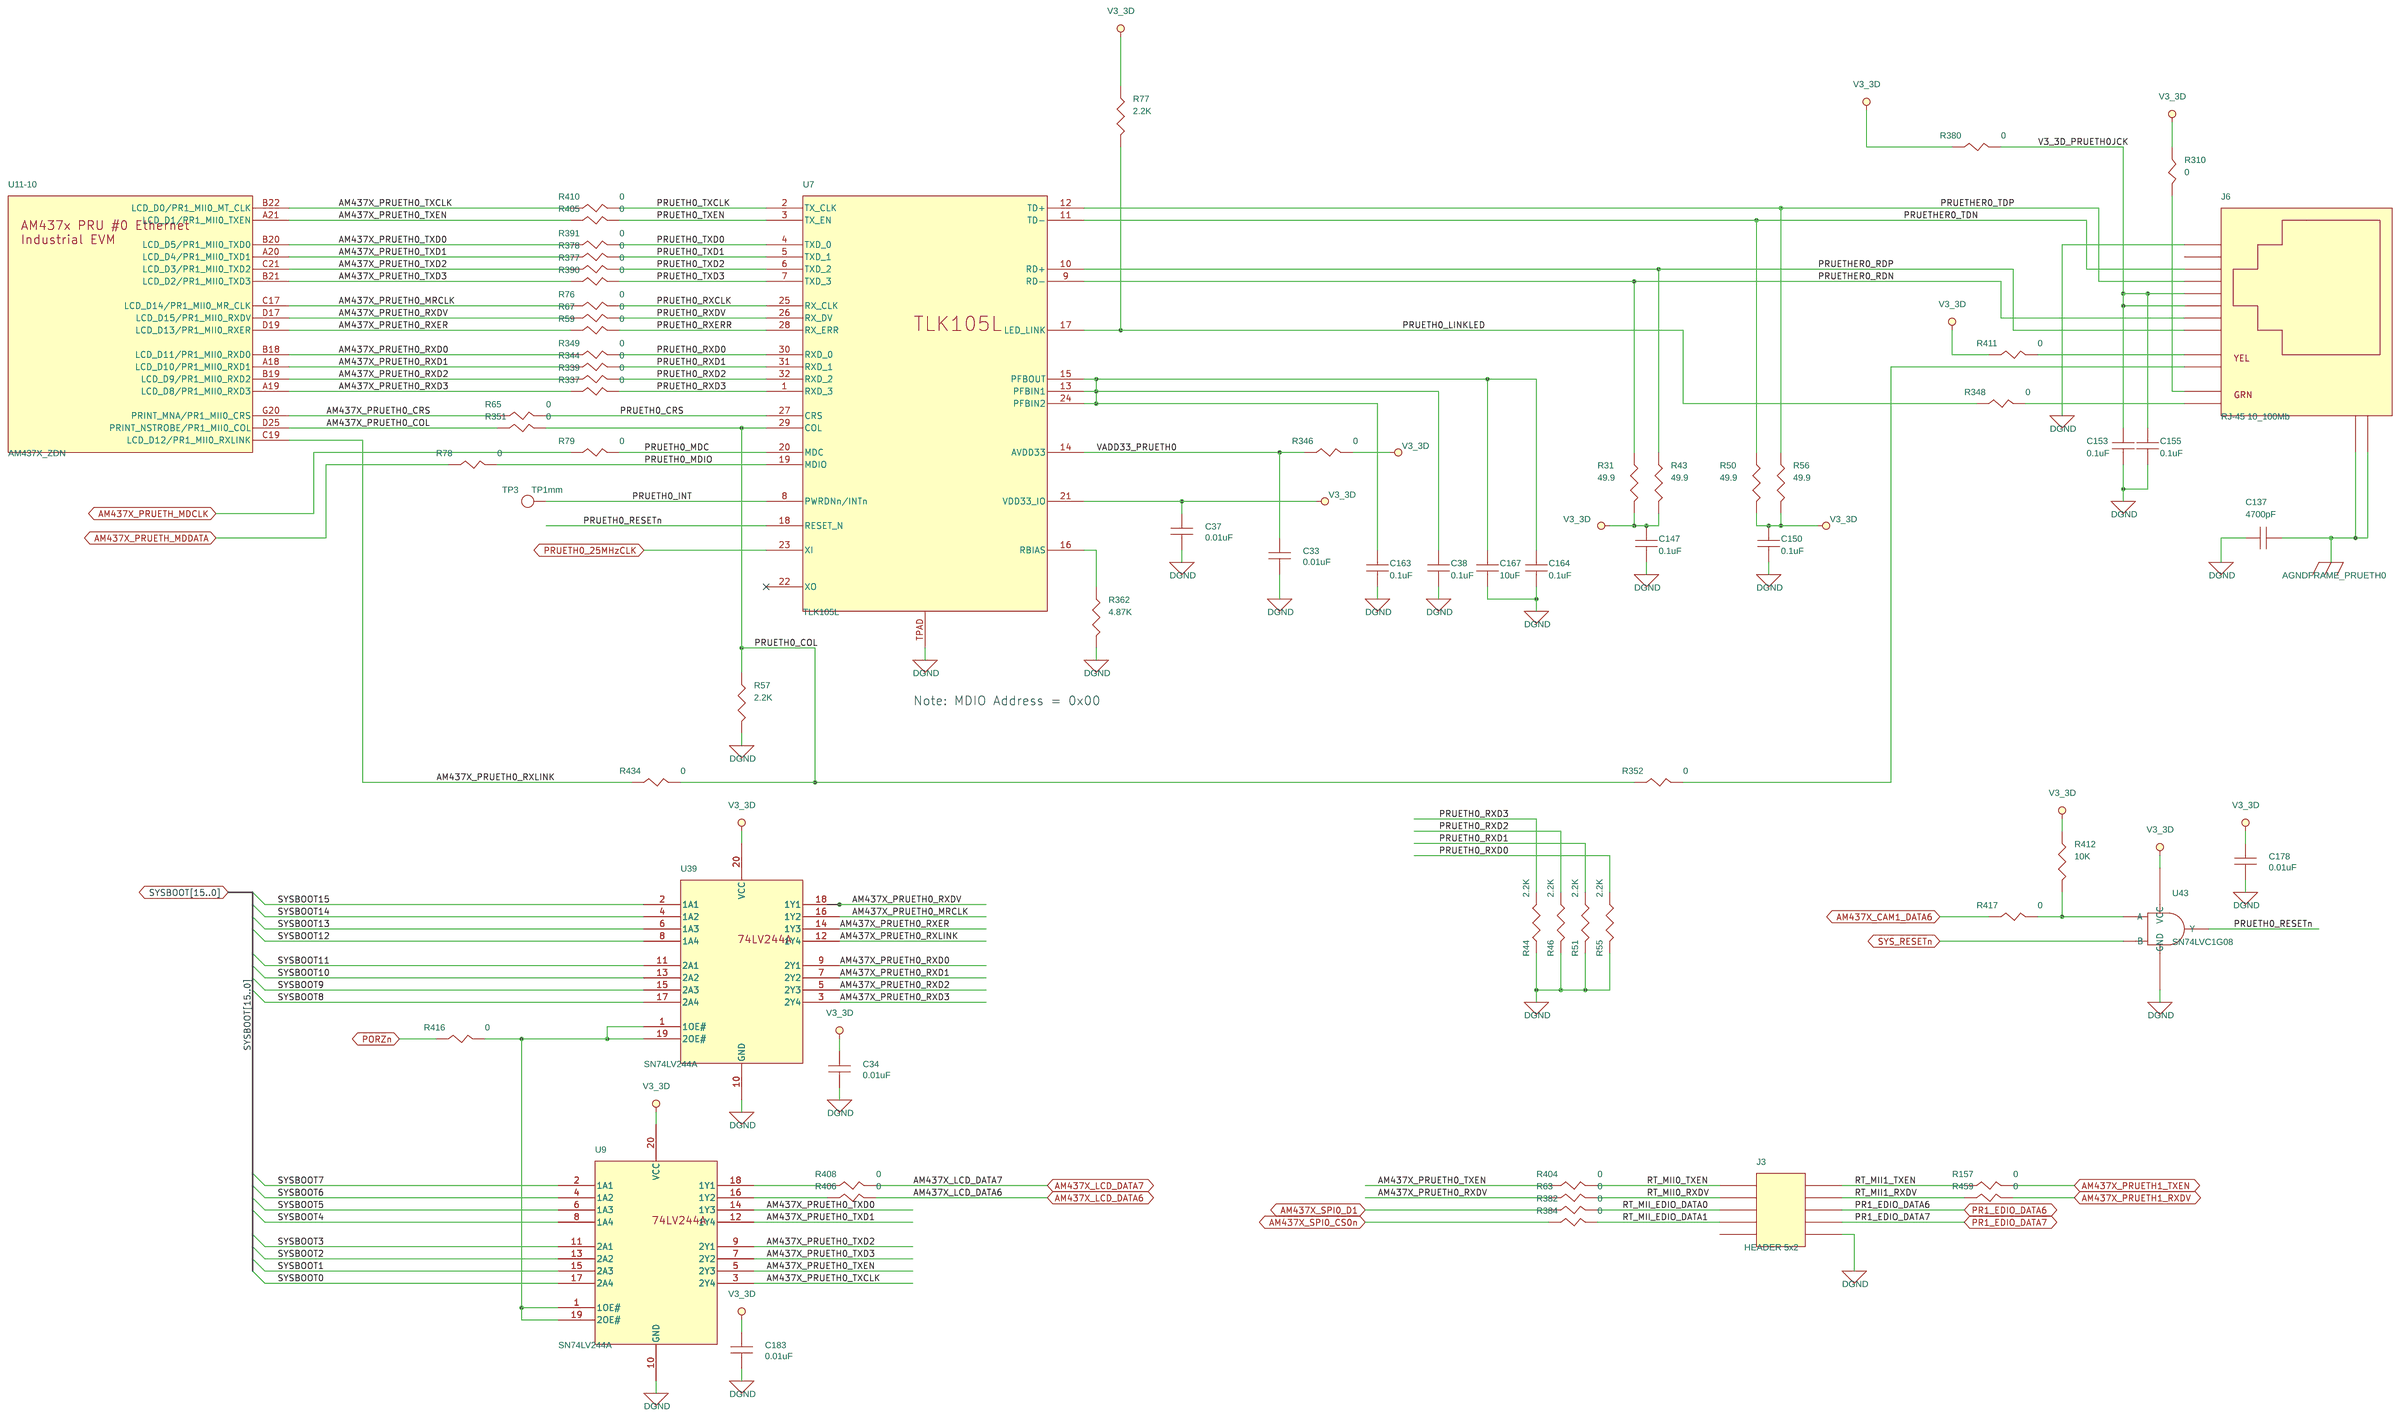
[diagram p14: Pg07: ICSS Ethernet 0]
16 Pg10: SDMMC0 Interface: size C
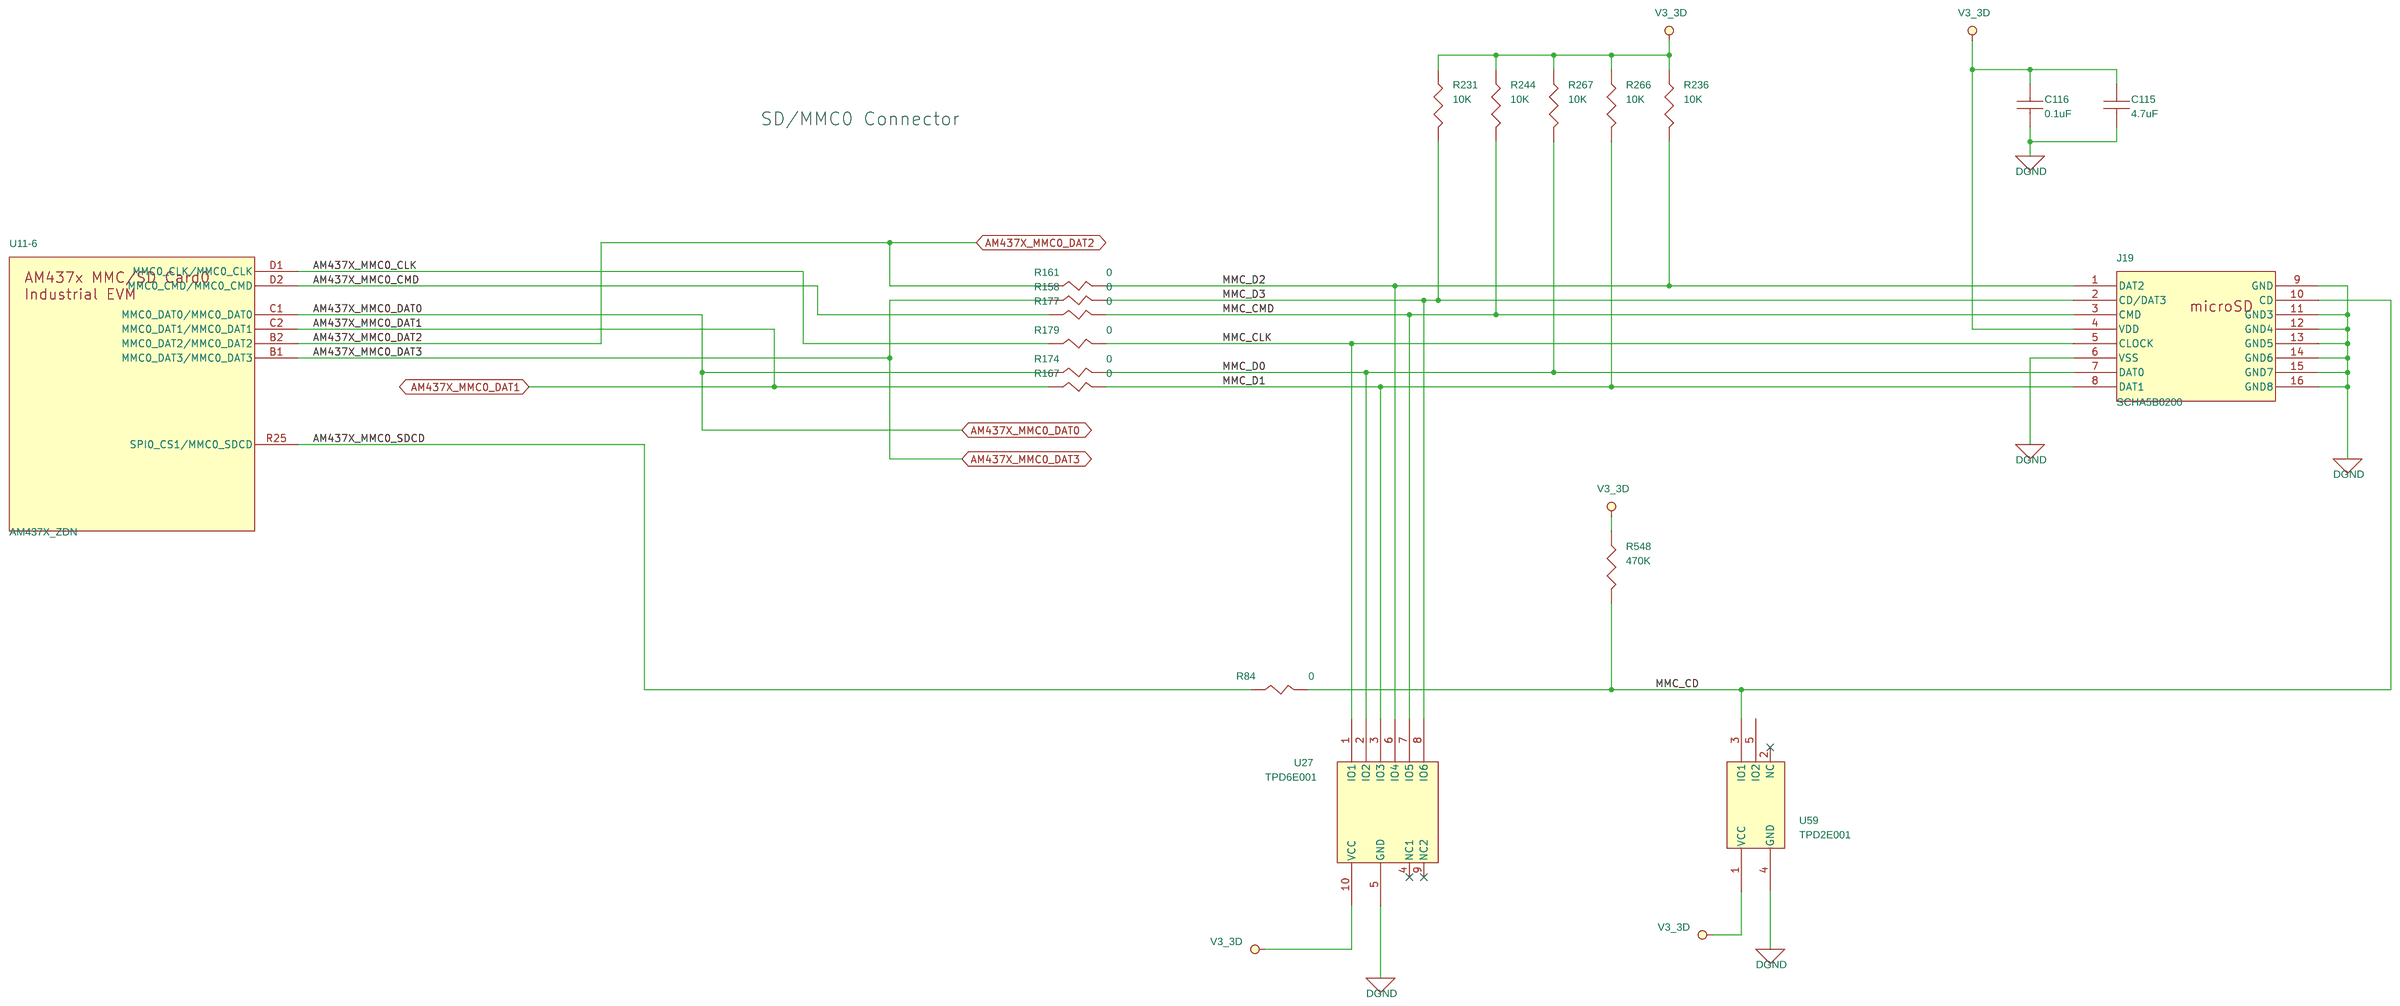
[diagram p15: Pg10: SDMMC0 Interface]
17 Pg19: Expansion Connector: size C
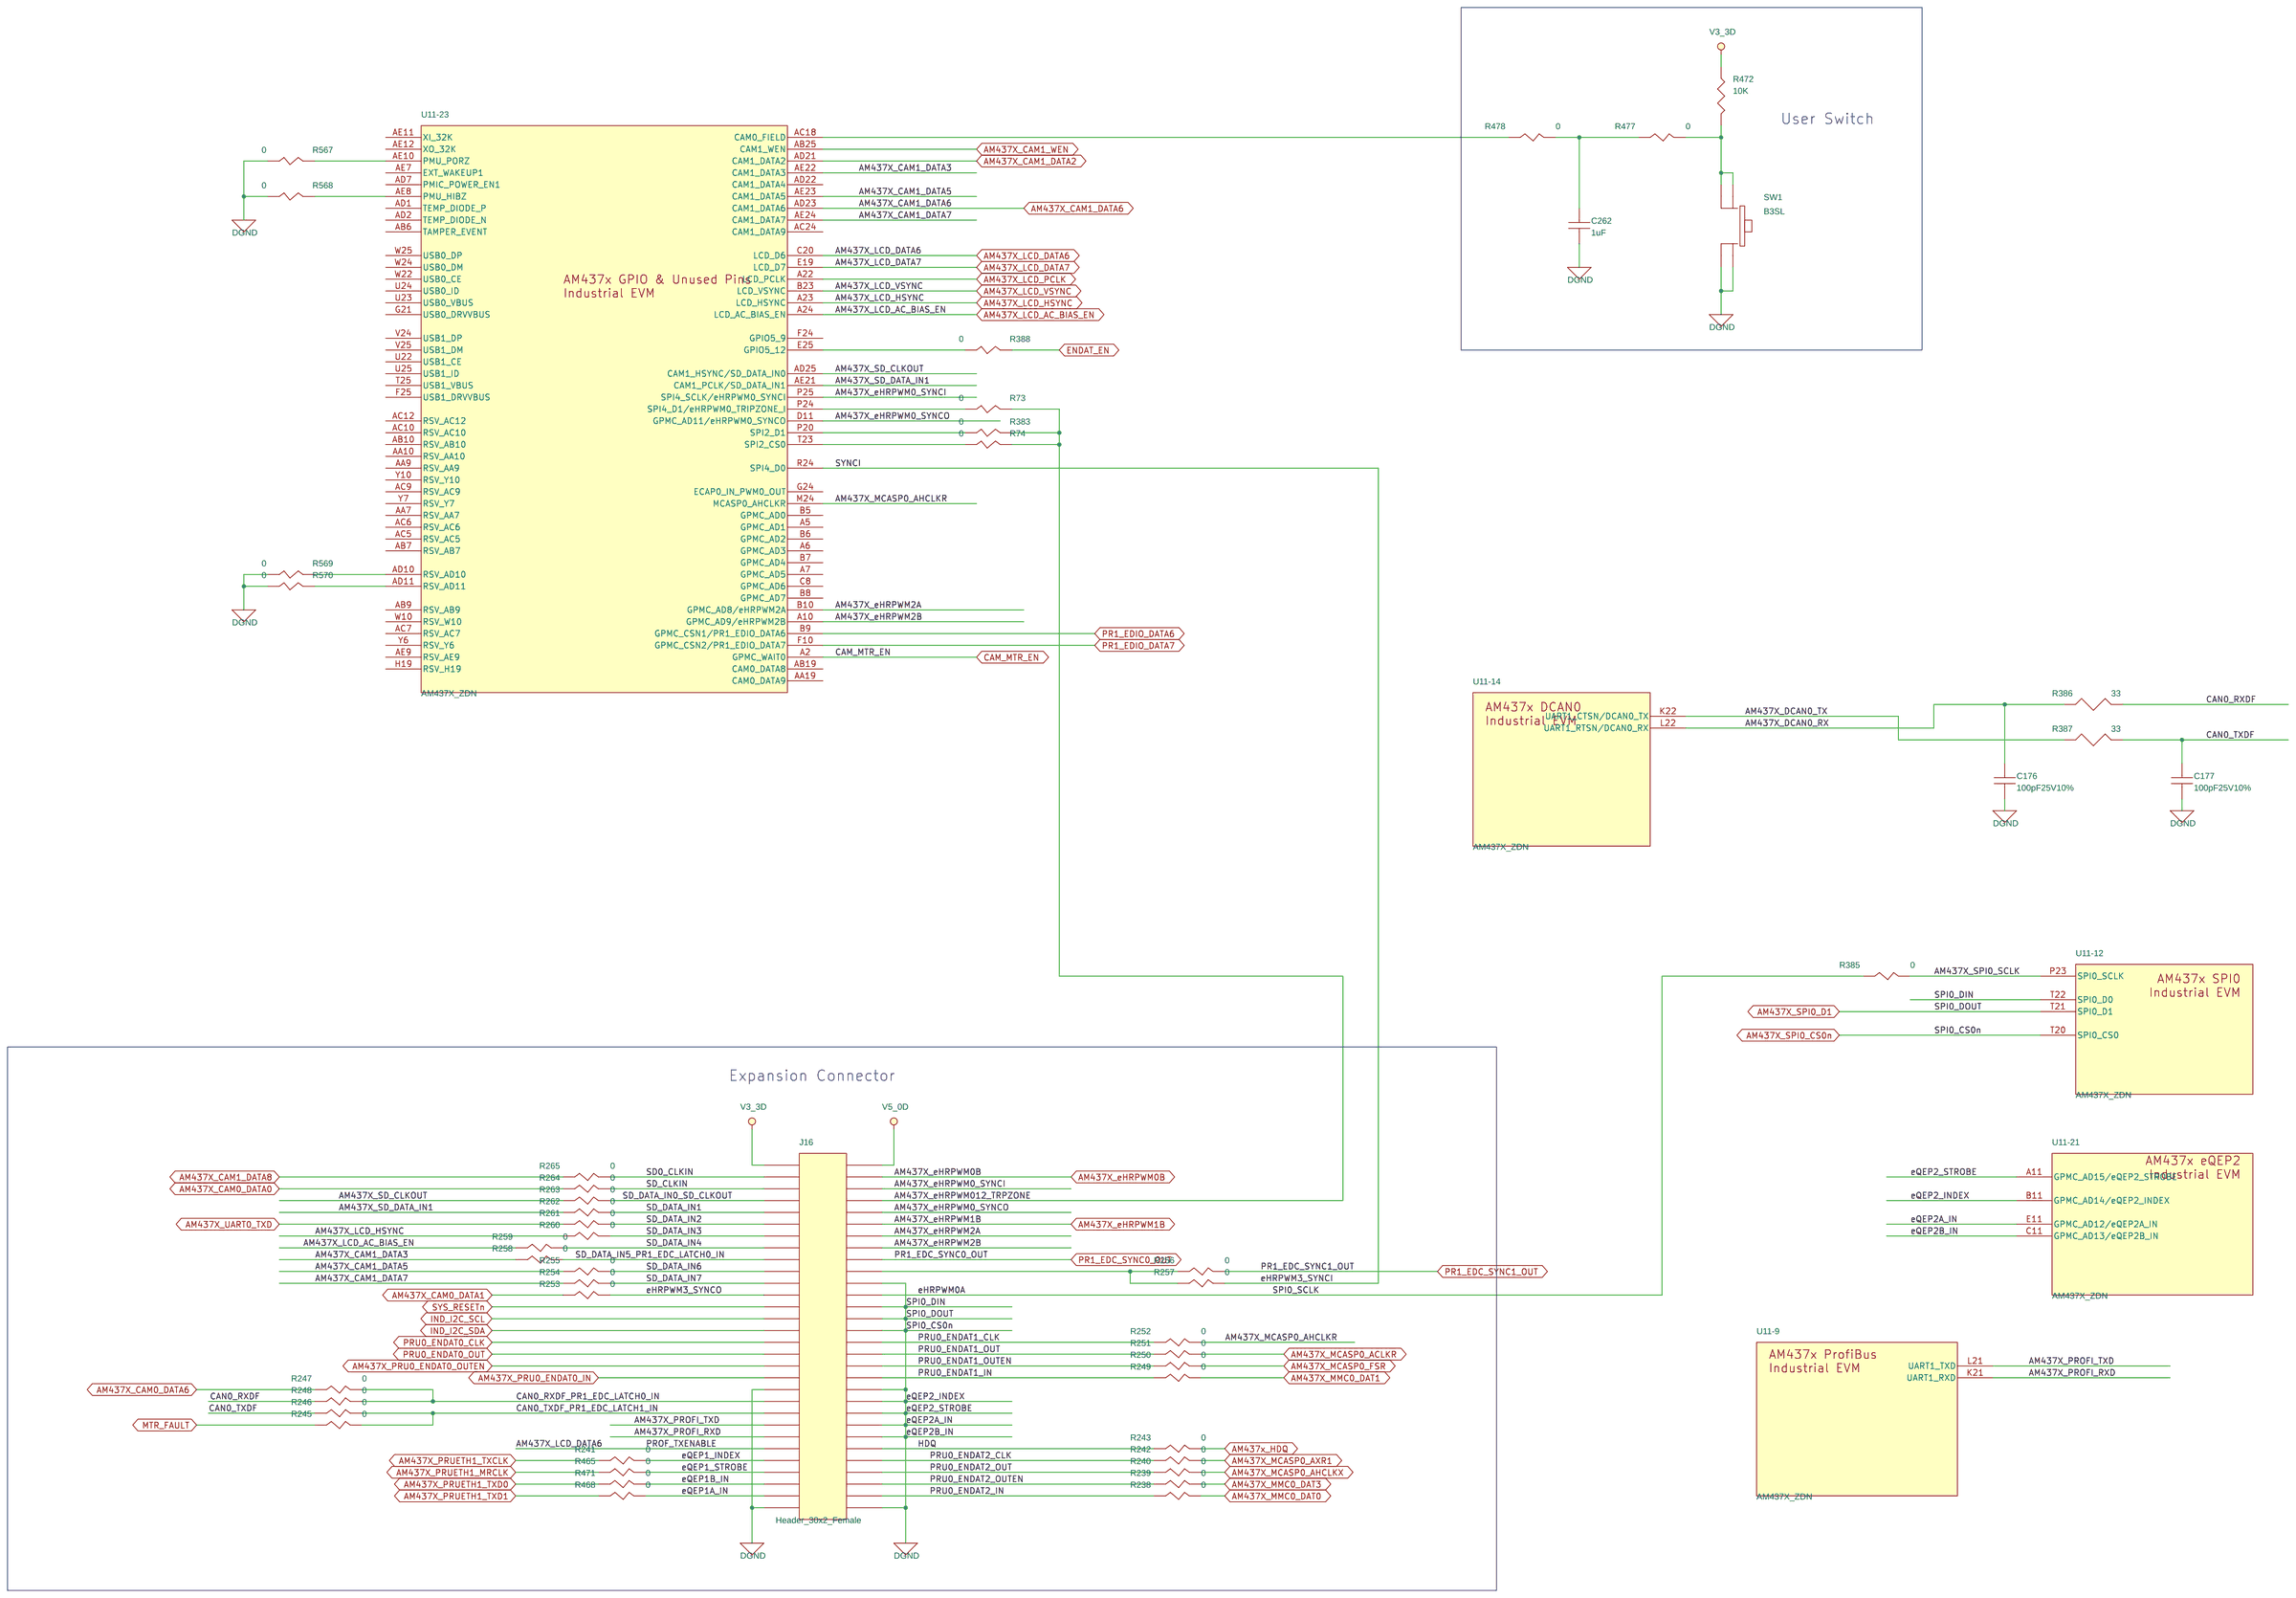
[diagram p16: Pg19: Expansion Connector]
18 Pg02: Processor subsystem: size C
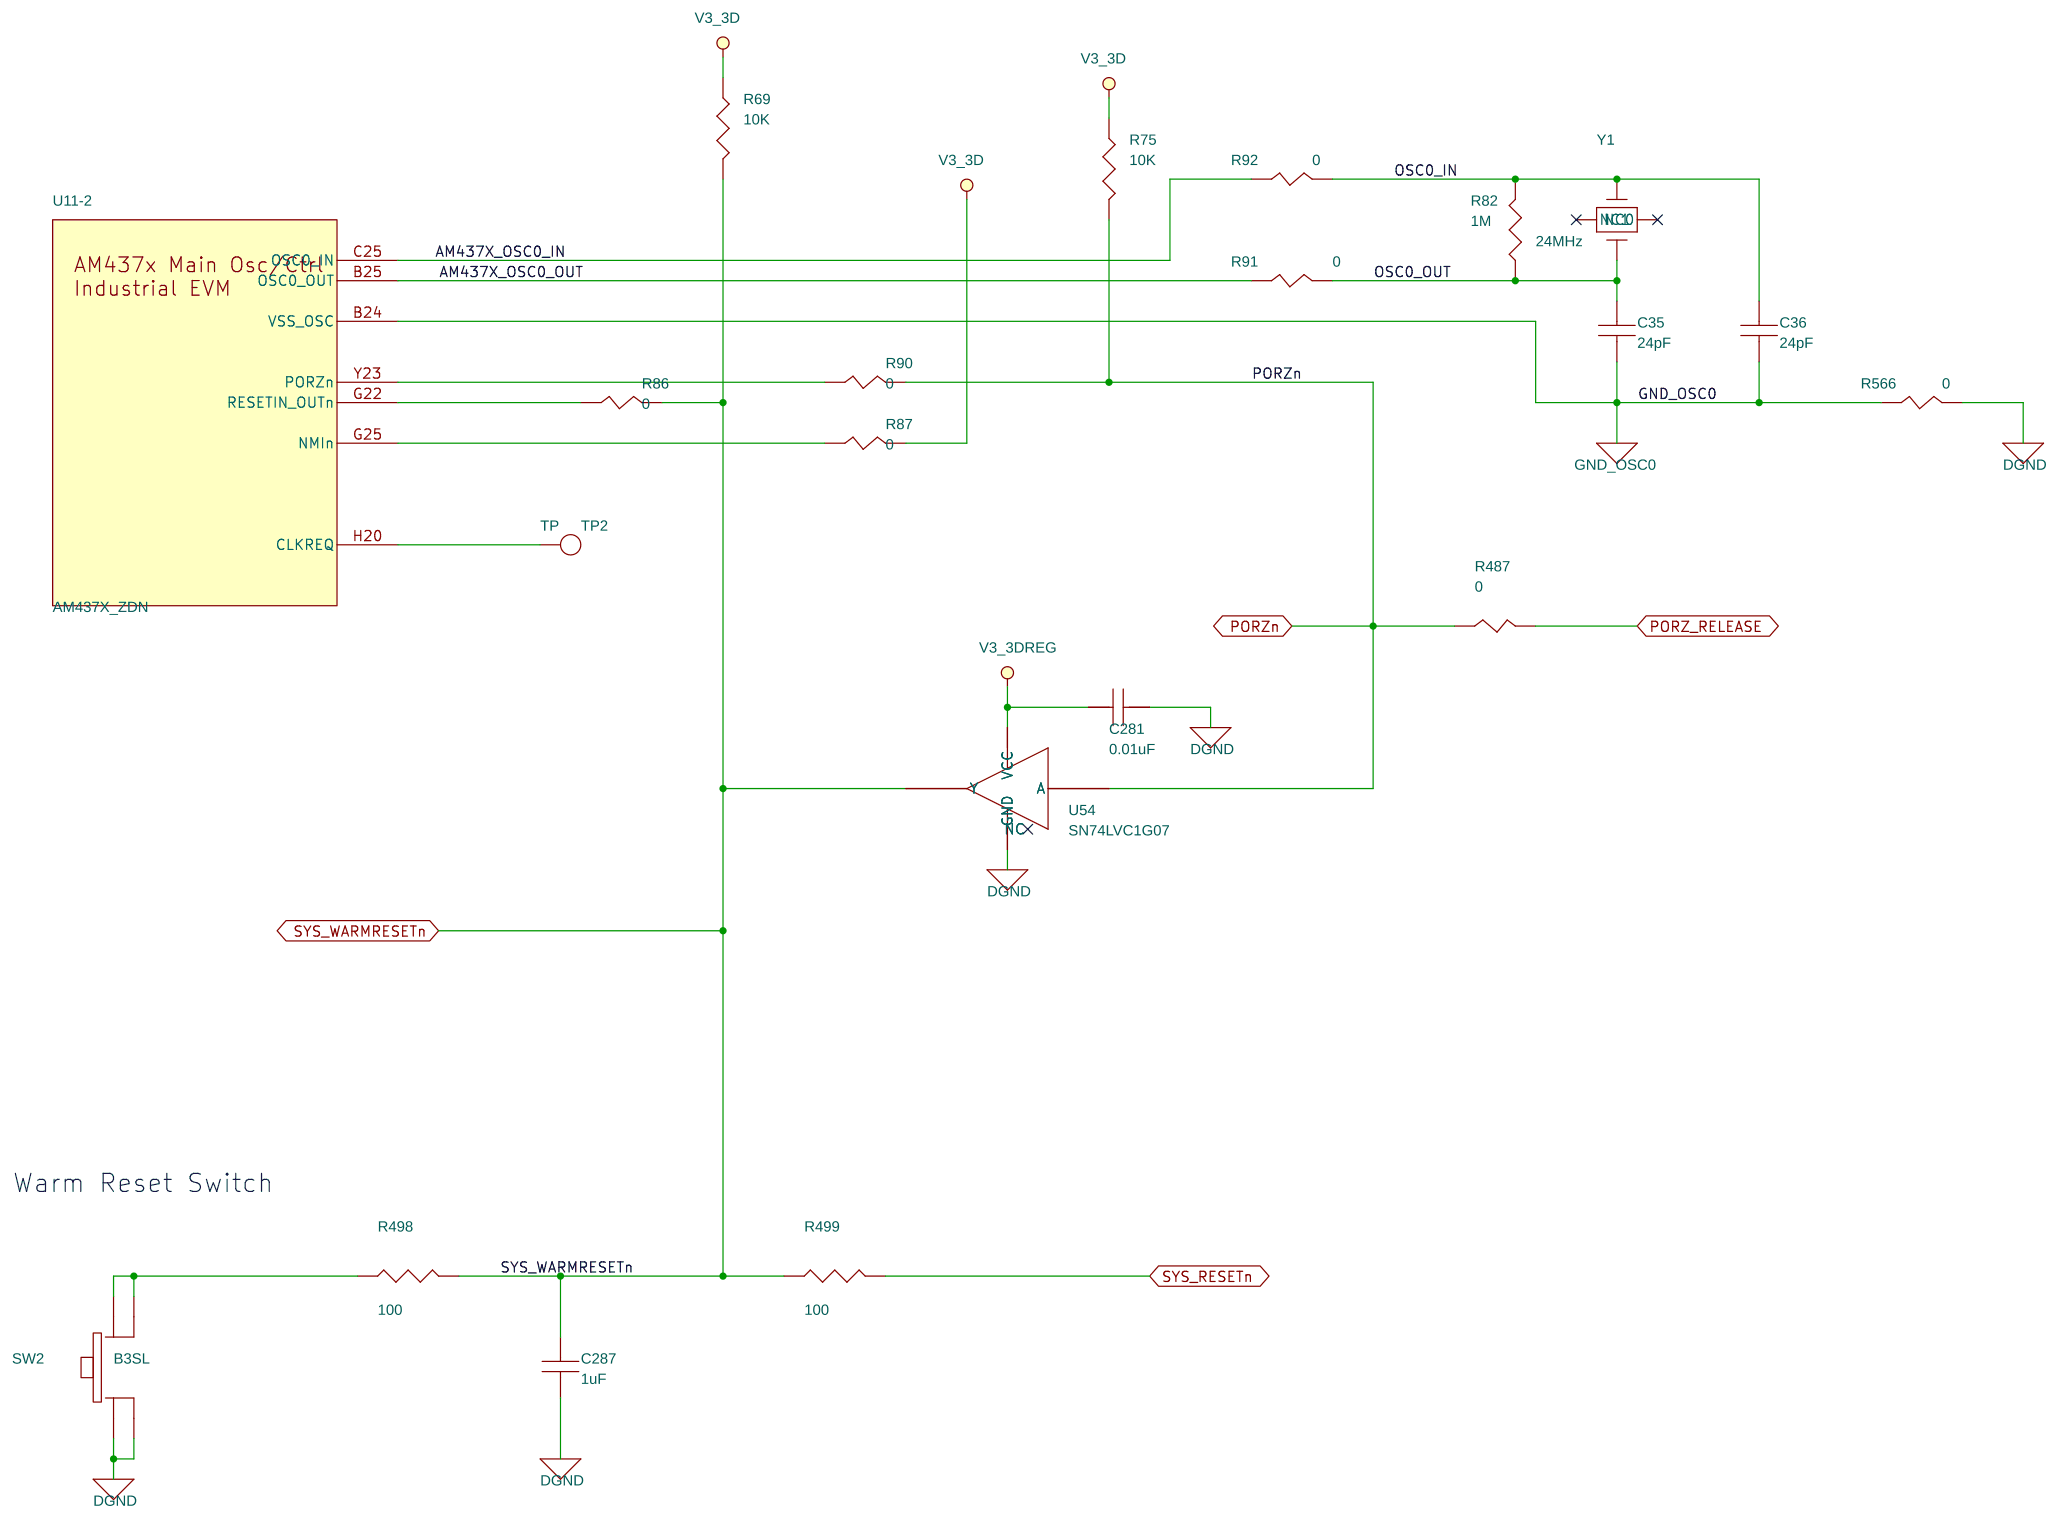
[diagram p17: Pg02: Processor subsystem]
19 Pg05: QSPI NOR Flash Memory: size C
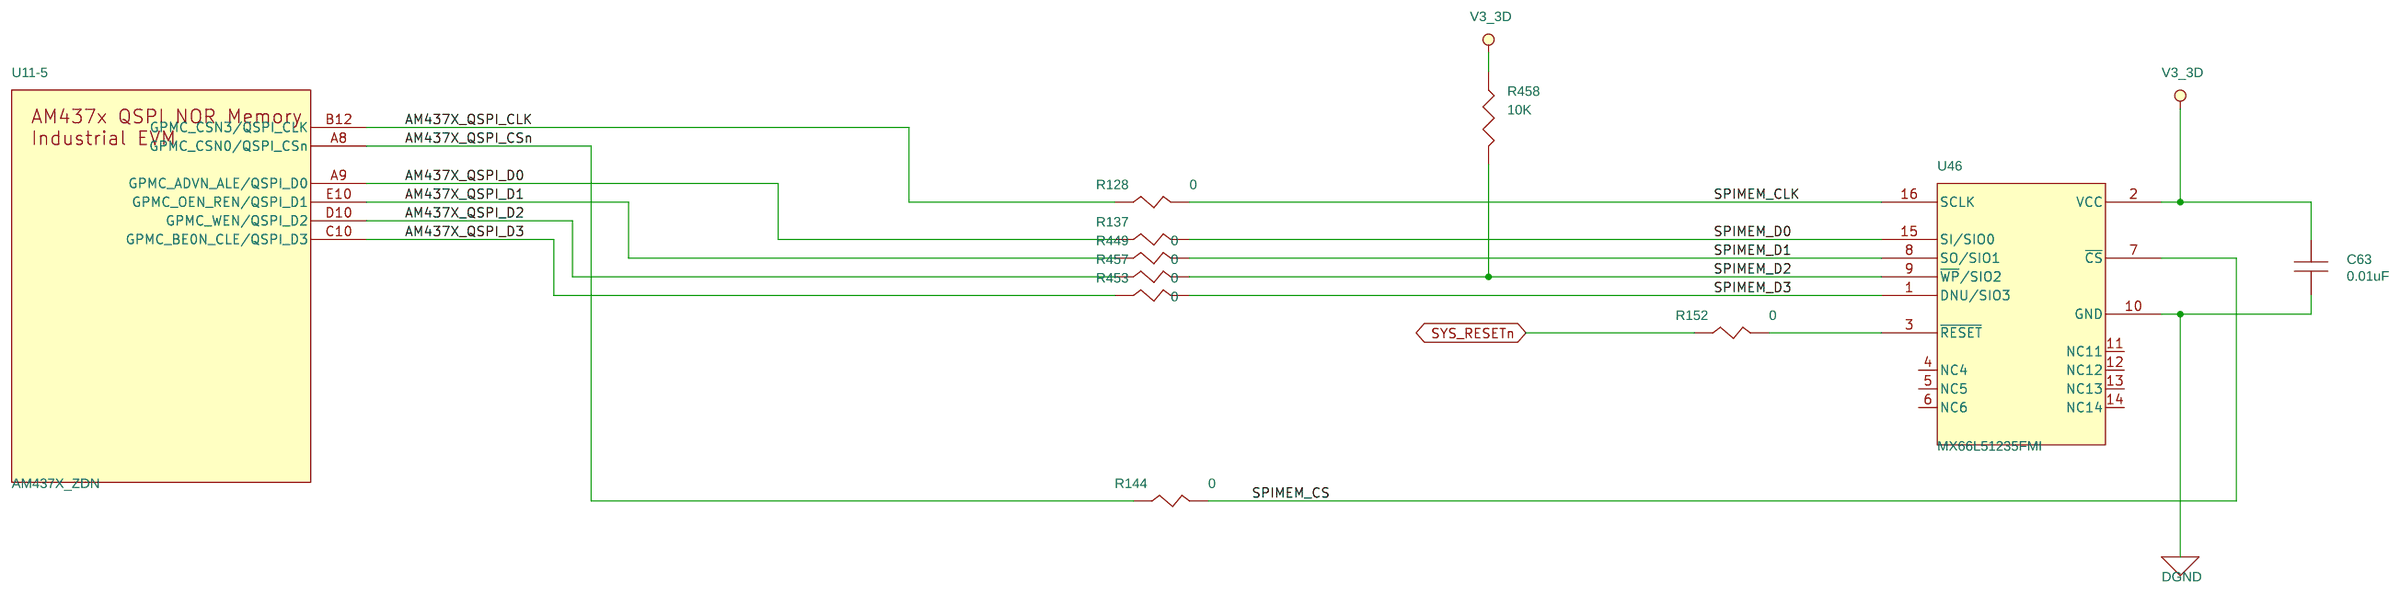
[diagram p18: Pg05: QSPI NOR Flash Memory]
20 Pg16: Motor Position Encoding: size C

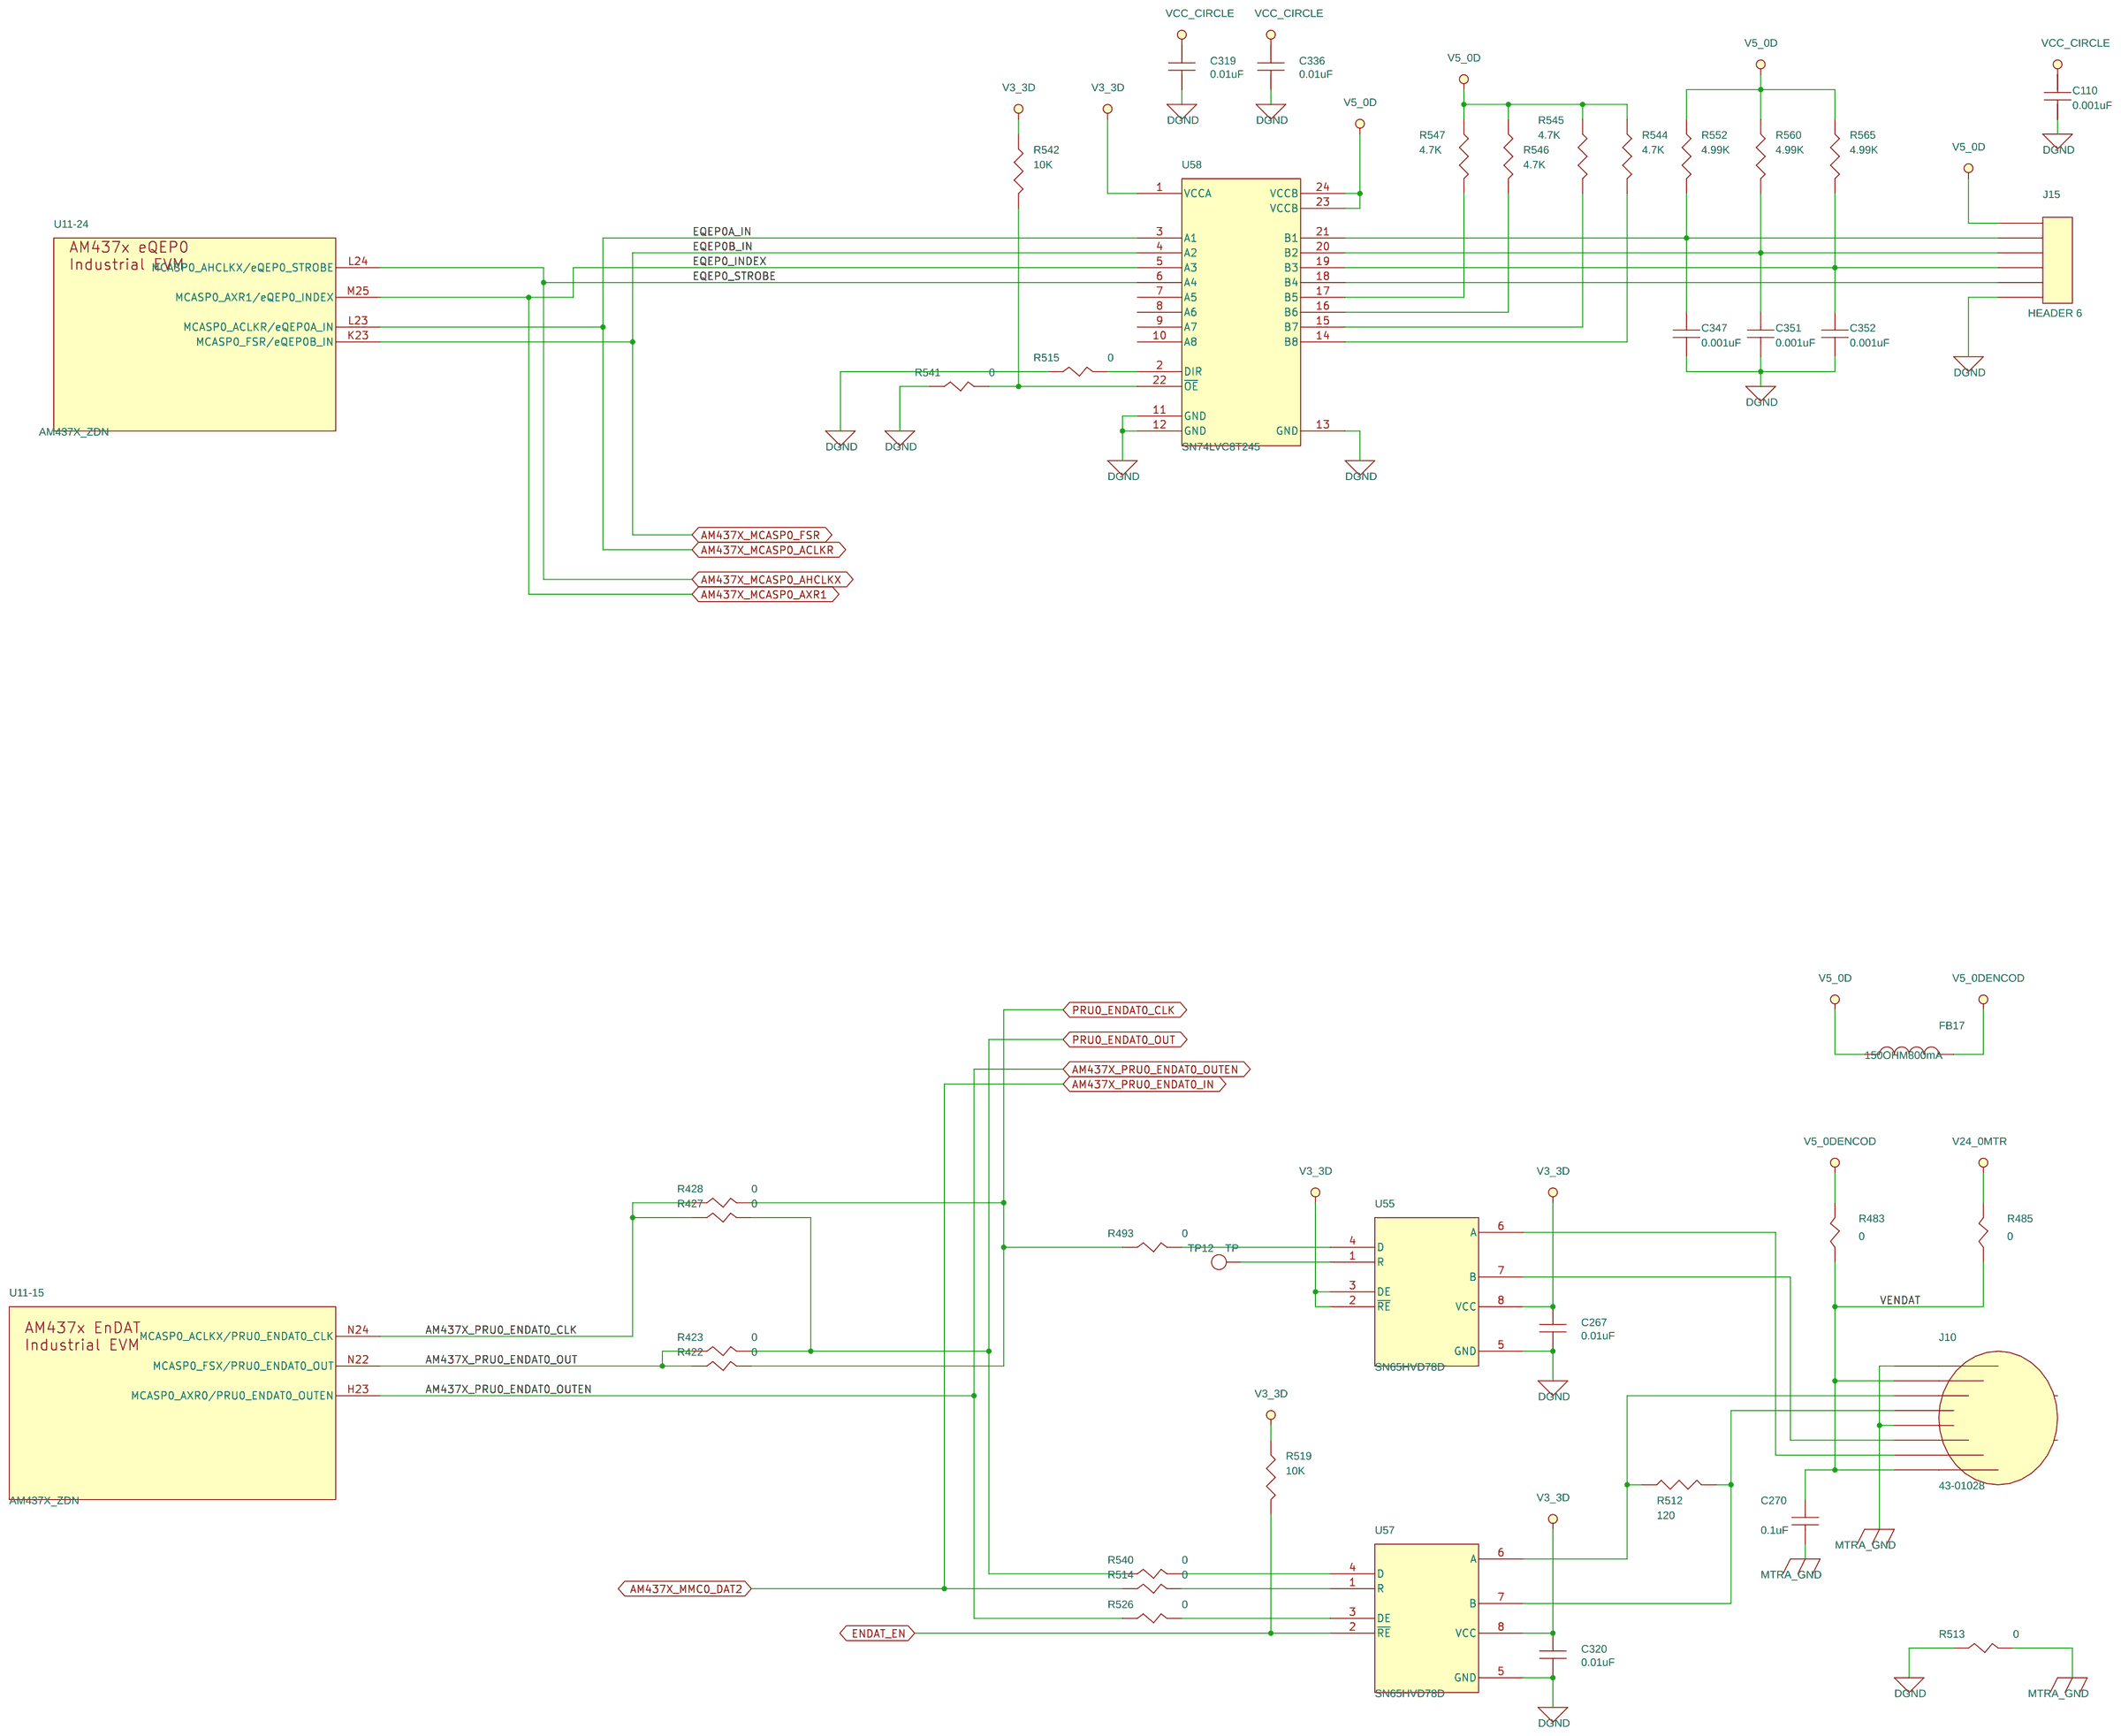
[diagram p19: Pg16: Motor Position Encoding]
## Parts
sheet Pg02: Processor subsystem
C35  24pF  [SM-7351-CAP-0402]
C36  24pF  [SM-7351-CAP-0402]
C281  0.01uF  [SM-7351-CAP-0402]
C287  1uF  [SM-7351-CAP-0402]
R69  10K  [SM-7351-RES-0402]
R75  10K  [SM-7351-RES-0402]
R82  1M  [SM-7351-RES-0402]
R86  0  [SM-7351-RES-0402]
R87  0  [SM-7351-RES-0402]
R90  0  [SM-7351-RES-0402]
R91  0  [SM-7351-RES-0402]
R92  0  [SM-7351-RES-0402]
R487  0  [SM-7351-RES-0402]
R498  100  [SM-7351-RES-0402]
R499  100  [SM-7351-RES-0402]
R566  0  [SM-7351-RES-0402]
SW2  B3SL  [SW_B3SL-1022P]
TP2  TP  [TH_TP_5002]
U54  SN74LVC1G07  [SC70-5-43M]
Y1  24MHz  [XTAL2X3-30M]
sheet Pg05: QSPI NOR Flash Memory
C63  0.01uF  [SM-7351-CAP-0402]
R128  0  [SM-7351-RES-0402]
R137  0  [SM-7351-RES-0402]
R144  0  [SM-7351-RES-0402]
R152  0  [SM-7351-RES-0402]
R449  0  [SM-7351-RES-0402]
R453  0  [SM-7351-RES-0402]
R457  0  [SM-7351-RES-0402]
R458  10K  [SM-7351-RES-0402]
U46  MX66L51235FMI  [soic_16pin_dw]
sheet Pg07: ICSS Ethernet 0
C33  0.01uF  [SM-7351-CAP-0402]
C34  0.01uF  [SM-7351-CAP-0402]
C37  0.01uF  [SM-7351-CAP-0402]
C38  0.1uF  [SM-7351-CAP-0402]
C137  4700pF  [SM-7351-CAP-0402]
C147  0.1uF  [SM-7351-CAP-0402]
C150  0.1uF  [SM-7351-CAP-0402]
C153  0.1uF  [SM-7351-CAP-0402]
C155  0.1uF  [SM-7351-CAP-0402]
C163  0.1uF  [SM-7351-CAP-0402]
C164  0.1uF  [SM-7351-CAP-0402]
C167  10uF  [SM-7351-CAP-0805]
C178  0.01uF  [SM-7351-CAP-0402]
C183  0.01uF  [SM-7351-CAP-0402]
J3  HEADER 5x2  [hdr2x5-330m]
J6  RJ-45 10_100Mb  [CNRJ45-1X1WLED]
R31  49.9  [SM-7351-RES-0402]
R43  49.9  [SM-7351-RES-0402]
R44  2.2K  [sm-7351-res-0402]
R46  2.2K  [sm-7351-res-0402]
R50  49.9  [SM-7351-RES-0402]
R51  2.2K  [sm-7351-res-0402]
R55  2.2K  [sm-7351-res-0402]
R56  49.9  [SM-7351-RES-0402]
R57  2.2K  [sm-7351-res-0402]
R59  0  [SM-7351-RES-0402]
R63  0  [SM-7351-RES-0402]
R65  0  [SM-7351-RES-0402]
R67  0  [SM-7351-RES-0402]
R76  0  [SM-7351-RES-0402]
R77  2.2K  [sm-7351-res-0402]
R78  0  [SM-7351-RES-0402]
R79  0  [SM-7351-RES-0402]
R157  0  [SM-7351-RES-0402]
R310  0  [SM-7351-RES-0402]
R337  0  [SM-7351-RES-0402]
R339  0  [SM-7351-RES-0402]
R344  0  [SM-7351-RES-0402]
R346  0  [SM-7351-RES-0603]
R348  0  [SM-7351-RES-0402]
R349  0  [SM-7351-RES-0402]
R351  0  [SM-7351-RES-0402]
R352  0  [SM-7351-RES-0402]
R362  4.87K  [SM-7351-RES-0402]
R377  0  [SM-7351-RES-0402]
R378  0  [SM-7351-RES-0402]
R380  0  [SM-7351-RES-0402]
R382  0  [SM-7351-RES-0402]
R384  0  [SM-7351-RES-0402]
R390  0  [SM-7351-RES-0402]
R391  0  [SM-7351-RES-0402]
R404  0  [SM-7351-RES-0402]
R405  0  [SM-7351-RES-0402]
R406  0  [SM-7351-RES-0402]
R408  0  [SM-7351-RES-0402]
R410  0  [SM-7351-RES-0402]
R411  0  [SM-7351-RES-0402]
R412  10K  [SM-7351-RES-0402]
R416  0  [SM-7351-RES-0402]
R417  0  [SM-7351-RES-0402]
R434  0  [SM-7351-RES-0402]
R459  0  [SM-7351-RES-0402]
TP3  TP1mm  [tp_smd1mmcircle]
U7  TLK105L  [qfn5x5-32-39m]
U9  SN74LV244A  [TSSOP4X6-20]
U39  SN74LV244A  [TSSOP4X6-20]
U43  SN74LVC1G08  [sm-so-sc70-5]
sheet Pg10: SDMMC0 Interface
C115  4.7uF  [SM-7351-CAP-0603]
C116  0.1uF  [SM-7351-CAP-0402]
J19  SCHA5B0200  [SD-MICRO-SCHA5B0300]
R84  0  [SM-7351-RES-0402]
R158  0  [SM-7351-RES-0402]
R161  0  [SM-7351-RES-0402]
R167  0  [SM-7351-RES-0402]
R174  0  [SM-7351-RES-0402]
R177  0  [SM-7351-RES-0402]
R179  0  [SM-7351-RES-0402]
R231  10K  [SM-7351-RES-0402]
R236  10K  [SM-7351-RES-0402]
R244  10K  [SM-7351-RES-0402]
R266  10K  [SM-7351-RES-0402]
R267  10K  [SM-7351-RES-0402]
R548  470K  [SM-7351-RES-0402]
U27  TPD6E001  [U_10_RSE]
U59  TPD2E001  [U_5_DRL]
sheet Pg16: Motor Position Encoding
C110  0.001uF  [SM-7351-CAP-0402]
C267  0.01uF  [SM-7351-CAP-0402]
C270  0.1uF  [SM-7351-CAP-0402]
C319  0.01uF  [SM-7351-CAP-0402]
C320  0.01uF  [SM-7351-CAP-0402]
C336  0.01uF  [SM-7351-CAP-0402]
C347  0.001uF  [SM-7351-CAP-0402]
C351  0.001uF  [SM-7351-CAP-0402]
C352  0.001uF  [SM-7351-CAP-0402]
FB17  150OHM800mA  [sm-7351-ind-0805]
J10  43-01028  [CN43-01028]
J15  HEADER 6  [hdrtsw1x6-330m]
R422  0  [SM-7351-RES-0603]
R423  0  [SM-7351-RES-0603]
R427  0  [SM-7351-RES-0603]
R428  0  [SM-7351-RES-0603]
R483  0  [SM-7351-RES-0603]
R485  0  [SM-7351-RES-0603]
R493  0  [SM-7351-RES-0603]
R512  120  [SM-7351-RES-0402]
R513  0  [SM-7351-RES-0603]
R514  0  [SM-7351-RES-0603]
R515  0  [SM-7351-RES-0402]
R519  10K  [SM-7351-RES-0402]
R526  0  [SM-7351-RES-0603]
R540  0  [SM-7351-RES-0603]
R541  0  [SM-7351-RES-0402]
R542  10K  [SM-7351-RES-0402]
R544  4.7K  [SM-7351-RES-0402]
R545  4.7K  [SM-7351-RES-0402]
R546  4.7K  [SM-7351-RES-0402]
R547  4.7K  [SM-7351-RES-0402]
R552  4.99K  [SM-7351-RES-0402]
R560  4.99K  [SM-7351-RES-0402]
R565  4.99K  [SM-7351-RES-0402]
TP12  TP  [TH_TP_5002]
U55  SN65HVD78D  [soic_8]
U57  SN65HVD78D  [soic_8]
U58  SN74LVC8T245  [TSSOP8X4-24-47M]
sheet Pg19: Expansion Connector
C176  100pF25V10%  [SM-7351-CAP-0402]
C177  100pF25V10%  [SM-7351-CAP-0402]
C262  1uF  [SM-7351-CAP-0603]
J16  Header_30x2_Female  [HDR2X30-2mm-177m]
R73  0  [SM-7351-RES-0402]
R74  0  [SM-7351-RES-0402]
R238  0  [SM-7351-RES-0402]
R239  0  [SM-7351-RES-0402]
R240  0  [SM-7351-RES-0402]
R241  0  [SM-7351-RES-0402]
R242  0  [SM-7351-RES-0402]
R243  0  [SM-7351-RES-0402]
R245  0  [SM-7351-RES-0402]
R246  0  [SM-7351-RES-0402]
R247  0  [SM-7351-RES-0402]
R248  0  [SM-7351-RES-0402]
R249  0  [SM-7351-RES-0402]
R250  0  [SM-7351-RES-0402]
R251  0  [SM-7351-RES-0402]
R252  0  [SM-7351-RES-0402]
R253  0  [SM-7351-RES-0402]
R254  0  [SM-7351-RES-0402]
R255  0  [SM-7351-RES-0402]
R256  0  [SM-7351-RES-0402]
R257  0  [SM-7351-RES-0402]
R258  0  [SM-7351-RES-0402]
R259  0  [SM-7351-RES-0402]
R260  0  [SM-7351-RES-0402]
R261  0  [SM-7351-RES-0402]
R262  0  [SM-7351-RES-0402]
R263  0  [SM-7351-RES-0402]
R264  0  [SM-7351-RES-0402]
R265  0  [SM-7351-RES-0402]
R383  0  [SM-7351-RES-0402]
R385  0  [SM-7351-RES-0402]
R386  33  [SM-7351-RES-0402]
R387  33  [SM-7351-RES-0402]
R388  0  [SM-7351-RES-0402]
R465  0  [SM-7351-RES-0402]
R468  0  [SM-7351-RES-0402]
R471  0  [SM-7351-RES-0402]
R472  10K  [SM-7351-RES-0402]
R477  0  [SM-7351-RES-0402]
R478  0  [SM-7351-RES-0402]
R567  0  [SM-7351-RES-0402]
R568  0  [SM-7351-RES-0402]
R569  0  [SM-7351-RES-0402]
R570  0  [SM-7351-RES-0402]
SW1  B3SL  [SW_B3SL-1022P]
U11  AM437X_ZDN  [AM437X_ZDN]  (sections -1,-10,-11,-12,-13,-14,-15,-16,-17,-18,-19,-2,-20,-21,-22,-23,-24,-25,-3,-4,-5,-6,-7,-8,-9)

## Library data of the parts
C35 C36 = 1C_24pFCapacitor50V5%SMD0402
C33 C34 C37 C63 C178 C183 C267 C281 C319 C320 C336 = 1C_0.01uFCapacitor16V10%0402
C287 = 1C_1uFCapacitor10V10%0402
R69 R75 R231 R236 R244 R266 R267 R412 R458 R472 R519 R542 = 1R_10KOhmResistor1_16W0402
R82 = 1MOhmResistor1_16W0402
R59 R63 R65 R67 R73 R74 R76 R78 R79 R84 R86 R87 R90-R92 R128 R137 R144 R152 R157 R158 R161 R167 R174 R177 R179 R238-R243 R245-R265 R310 R337 R339 R344 R348 R349 R351 R352 R377 R378 R380 R382-R385 R388 R390 R391 R404-R406 R408 R410 R411 R416 R417 R434 R449 R453 R457 R459 R465 R468 R471 R477 R478 R487 R515 R541 R566-R570 = 1R_ZeroOhmResistor1_16W0402
R498 R499 = 1R_100ohm1_16W1%SMD0402
SW1 SW2 = 2W_Switch_Pushbuttonsmd
TP2 TP12 = 2H_TestPointThroughHole
U54 = 1A_SN74LVC1G07
Y1 = 1Y_Crystal24MHzSCM
U46 = 1A_MX66L51235FMI
C38 C116 C147 C150 C153 C155 C163 C164 = 1C_0.1uFCapacitor16V10%0402
C137 = 1C_4700pFCapacitor50V10%0402
C167 = 1C_10uFCapacitor16V10%0805
J3 = 2H_Header5x2
J6 = 2J_ConnectorRJ45_10_100MbAMDIX
R31 R43 R50 R56 = 1R_49.9OhmResistor1_16W0402
R44 R46 R51 R55 R57 R77 = 1R_2.2KOhmResistor1_16W0402
R346 R422 R423 R427 R428 R483 R485 R493 R513 R514 R526 R540 = 1R_ZeroOhmResistor1_16W0603
R362 = 1R_4.87Kohm1_16W1%smd0402
TP3 = 2H_Testpoint_SMD1mmCircle
U7 = 1A_TLK105L
U9 U39 = 1A_SN74LV244APWRG3
U43 = SN74LVC1G08DCKT_SC70
C115 = 1C_4.7uFCapacitor16V10%0603
J19 = 2C_Conn_microSD_8
R548 = 470Kohm1_16W1%SMD0402
U27 = 1A_TPD6E001RSE
U59 = 1A_TPD2E001DRL
C110 C347 C351 C352 = 1C_0.001uFCapacitor50V5%0402
C270 = 1C_0.1uFCapacitor50V10%0402
FB17 = 1L_FerBead_180ohm200mA
J10 = 2C_Conn_M12_8pin_female
J15 = 2H_Header_6x1
R512 = 1R_120ohm1_16W1%smd0402
R544-R547 = 1R_4.7KOhmResistor1_16W0402
R552 R560 R565 = 1R_4.99KOhmResistor1_16W0402
U55 U57 = 1A_SN65HVD78
U58 = 1A_SN74LVC8T245
C176 C177 = 1C_100pFCapacitor25V10%0402
C262 = 1C_1uFCapacitor50V10%0603
J16 = 2H_Header30x2_female_2mm
R386 R387 = 1R_33ohmResistor1_16W5%0402
U11 = am437x_ZDN_Industrial_EVM

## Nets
AGNDFRAME_PRUETH0: C137.2 J6.SHLD1 J6.SHLD2
DGND: C33.2 C34.2 C37.2 C38.2 C63.2 C110.2 C115.2 C116.2 C137.1 C147.2 C150.2 C153.2 C155.2 C163.2 C164.2 C167.2 C176.2 C177.2 C178.2 C183.2 C262.2 C267.2 C281.2 C287.2 C319.2 C320.2 C336.2 C347.2 C351.2 C352.2 J3.10 J6.8 J15.6 J16.22 J16.39 J16.40 J16.59 J16.60 J19.6(VSS) J19.9(GND) J19.11(GND3) J19.12(GND4) J19.13(GND5) J19.14(GND6) J19.15(GND7) J19.16(GND8) R44.1(P1) R46.1(P1) R51.1(P1) R55.1(P1) R57.1(P1) R362.1(P1) R513.2(P2) R515.2(P2) R541.2(P2) R566.2(P2) R567.1(P1) R568.1(P1) R569.1(P1) R570.1(P1) SW1.3 SW1.4 SW2.1 SW2.2 U7.TPAD U9.10(GND) U27.5(GND) U39.10(GND) U43.3(GND) U46.10(GND) U54.3(GND) U55.5(GND) U57.5(GND) U58.11(GND) U58.12(GND) U58.13(GND) U59.4(GND) ; also on sheet 1 2 3 4 5 6 8 9 10 11 12 13 14
GND_OSC0: C35.2 C36.2 R566.1(P1) U11.B24(VSS_OSC)
V3_3D: C34.1 C37.1 C63.1 C115.1 C116.1 C147.1 C150.1 C178.1 C183.1 C267.1 C319.1 C320.1 J16.1 J19.4(VDD) R31.1(P1) R43.1(P1) R50.1(P1) R56.1(P1) R69.2(P2) R75.2(P2) R77.2(P2) R87.2(P2) R231.2(P2) R236.2(P2) R244.2(P2) R266.2(P2) R267.2(P2) R310.2(P2) R346.1(P1) R380.2(P2) R411.2(P2) R412.2(P2) R458.2(P2) R472.2(P2) R519.2(P2) R542.2(P2) R548.2(P2) U7.21(VDD33_IO) U9.20(VCC) U27.10(VCC) U39.20(VCC) U43.5(VCC) U46.2(VCC) U55.2(~{RE}) U55.3(DE) U55.8(VCC) U57.8(VCC) U58.1(VCCA) U59.1(VCC) ; also on sheet 2 3 4 5 6 8 9 10 11 12 13 14
V3_3D_PRUETH0JCK: C153.1 C155.1 J6.3 J6.4 R380.1(P1)
V3_3DREG: C281.1 U54.5(VCC) ; also on sheet 11
V5_0D: C110.1 C336.1 FB17.1 J15.1 J16.2 R544.2(P2) R545.2(P2) R546.2(P2) R547.2(P2) R552.2(P2) R560.2(P2) R565.2(P2) U58.23(VCCB) U58.24(VCCB) ; also on sheet 1 11 12
V5_0DENCOD: FB17.2 R483.1(P1)
V24_0MTR: R485.1(P1) ; also on sheet 1 10
AM437X_CAM0_DATA0: R264.2(P2) ; also on sheet 2
AM437X_CAM0_DATA1: R253.2(P2) ; also on sheet 2 10
AM437X_CAM0_DATA6: R247.2(P2) ; also on sheet 2
AM437X_CAM1_DATA2: U11.AD21(CAM1_DATA2) ; also on sheet 3
AM437X_CAM1_DATA3: R258.2(P2) U11.AE22(CAM1_DATA3)
AM437X_CAM1_DATA5: R255.2(P2) U11.AE23(CAM1_DATA5)
AM437X_CAM1_DATA6: R417.2(P2) U11.AD23(CAM1_DATA6) ; also on sheet 14
AM437X_CAM1_DATA7: R254.2(P2) U11.AE24(CAM1_DATA7)
AM437X_CAM1_DATA8: R265.2(P2) ; also on sheet 10
AM437X_CAM1_WEN: U11.AB25(CAM1_WEN) ; also on sheet 3
AM437X_DCAN0_RX: C176.1 R386.1 U11.L22(UART1_RTSN/DCAN0_RX)
AM437X_DCAN0_TX: R387.1 U11.K22(UART1_CTSN/DCAN0_TX)
AM437X_eHRPWM0_SYNCI: J16.6 U11.P25(SPI4_SCLK/eHRPWM0_SYNCI)
AM437X_eHRPWM0_SYNCO: J16.10 U11.D11(GPMC_AD11/eHRPWM0_SYNCO)
AM437X_eHRPWM0B: J16.4 ; also on sheet 10
AM437X_eHRPWM1B: J16.12 ; also on sheet 10
AM437X_eHRPWM2A: J16.14 U11.B10(GPMC_AD8/eHRPWM2A)
AM437X_eHRPWM2B: J16.16 U11.A10(GPMC_AD9/eHRPWM2B)
AM437X_eHRPWM012_TRPZONE: J16.8 R73.2(P2) R74.2(P2) R383.2(P2)
AM437x_HDQ: R243.1(P1) ; also on sheet 10
AM437X_LCD_AC_BIAS_EN: R259.2(P2) U11.A24(LCD_AC_BIAS_EN) ; also on sheet 3 6
AM437X_LCD_DATA6: J16.49 R406.1(P1) U11.C20(LCD_D6)
AM437X_LCD_DATA7: R408.1(P1) U11.E19(LCD_D7)
AM437X_LCD_HSYNC: R260.2(P2) U11.A23(LCD_HSYNC) ; also on sheet 3 6
AM437X_LCD_PCLK: U11.A22(LCD_PCLK) ; also on sheet 3
AM437X_LCD_VSYNC: U11.B23(LCD_VSYNC) ; also on sheet 3 6
AM437X_MCASP0_ACLKR: R251.1(P1) U11.L23(MCASP0_ACLKR/eQEP0A_IN) U58.3(A1)
AM437X_MCASP0_AHCLKR: R252.1(P1) U11.M24(MCASP0_AHCLKR)
AM437X_MCASP0_AHCLKX: R240.1(P1) U11.L24(MCASP0_AHCLKX/eQEP0_STROBE) U58.6(A4)
AM437X_MCASP0_AXR1: R242.1(P1) U11.M25(MCASP0_AXR1/eQEP0_INDEX) U58.5(A3)
AM437X_MCASP0_FSR: R250.1(P1) U11.K23(MCASP0_FSR/eQEP0B_IN) U58.4(A2)
AM437X_MMC0_CLK: R179.2(P2) U11.D1(MMC0_CLK/MMC0_CLK)
AM437X_MMC0_CMD: R177.2(P2) U11.D2(MMC0_CMD/MMC0_CMD)
AM437X_MMC0_DAT0: R174.2(P2) R238.1(P1) U11.C1(MMC0_DAT0/MMC0_DAT0)
AM437X_MMC0_DAT1: R167.2(P2) R249.1(P1) U11.C2(MMC0_DAT1/MMC0_DAT1)
AM437X_MMC0_DAT2: J16.37 R161.2(P2) R514.2(P2) U11.B2(MMC0_DAT2/MMC0_DAT2)
AM437X_MMC0_DAT3: R158.2(P2) R239.1(P1) U11.B1(MMC0_DAT3/MMC0_DAT3)
AM437X_MMC0_SDCD: R84.2(P2) U11.R25(SPI0_CS1/MMC0_SDCD)
AM437X_OSC0_IN: R92.1(P1) U11.C25(OSC0_IN)
AM437X_OSC0_OUT: R91.1(P1) U11.B25(OSC0_OUT)
AM437X_PROFI_RXD: J16.47 U11.K21(UART1_RXD)
AM437X_PROFI_TXD: J16.45 U11.L21(UART1_TXD)
AM437X_PRU0_ENDAT0_CLK: R427.2(P2) R428.2(P2) U11.N24(MCASP0_ACLKX/PRU0_ENDAT0_CLK)
AM437X_PRU0_ENDAT0_OUT: R422.2(P2) R423.2(P2) U11.N22(MCASP0_FSX/PRU0_ENDAT0_OUT)
AM437X_PRU0_ENDAT0_OUTEN: J16.35 R526.2(P2) U11.H23(MCASP0_AXR0/PRU0_ENDAT0_OUTEN)
AM437X_PRUETH0_COL: R351.2(P2) U11.D25(PRINT_NSTROBE/PR1_MII0_COL)
AM437X_PRUETH0_CRS: R65.2(P2) U11.G20(PRINT_MNA/PR1_MII0_CRS)
AM437X_PRUETH0_MRCLK: R76.2(P2) U11.C17(LCD_D14/PR1_MII0_MR_CLK) U39.16(1Y2)
AM437X_PRUETH0_RXD0: R349.2(P2) U11.B18(LCD_D11/PR1_MII0_RXD0) U39.9(2Y1)
AM437X_PRUETH0_RXD1: R344.2(P2) U11.A18(LCD_D10/PR1_MII0_RXD1) U39.7(2Y2)
AM437X_PRUETH0_RXD2: R339.2(P2) U11.B19(LCD_D9/PR1_MII0_RXD2) U39.5(2Y3)
AM437X_PRUETH0_RXD3: R337.2(P2) U11.A19(LCD_D8/PR1_MII0_RXD3) U39.3(2Y4)
AM437X_PRUETH0_RXDV: R63.2(P2) R67.2(P2) U11.D17(LCD_D15/PR1_MII0_RXDV) U39.18(1Y1)
AM437X_PRUETH0_RXER: R59.2(P2) U11.D19(LCD_D13/PR1_MII0_RXER) U39.14(1Y3)
AM437X_PRUETH0_RXLINK: R434.2(P2) U11.C19(LCD_D12/PR1_MII0_RXLINK) U39.12(1Y4)
AM437X_PRUETH0_TXCLK: R410.2(P2) U9.3(2Y4) U11.B22(LCD_D0/PR1_MII0_MT_CLK)
AM437X_PRUETH0_TXD0: R391.2(P2) U9.14(1Y3) U11.B20(LCD_D5/PR1_MII0_TXD0)
AM437X_PRUETH0_TXD1: R378.2(P2) U9.12(1Y4) U11.A20(LCD_D4/PR1_MII0_TXD1)
AM437X_PRUETH0_TXD2: R377.2(P2) U9.9(2Y1) U11.C21(LCD_D3/PR1_MII0_TXD2)
AM437X_PRUETH0_TXD3: R390.2(P2) U9.7(2Y2) U11.B21(LCD_D2/PR1_MII0_TXD3)
AM437X_PRUETH0_TXEN: R404.2(P2) R405.2(P2) U9.5(2Y3) U11.A21(LCD_D1/PR1_MII0_TXEN)
AM437X_PRUETH1_MRCLK: R465.2(P2) ; also on sheet 14
AM437X_PRUETH1_RXDV: R459.1(P1) ; also on sheet 14
AM437X_PRUETH1_TXCLK: R241.2(P2) ; also on sheet 14
AM437X_PRUETH1_TXD0: R471.2(P2) ; also on sheet 14
AM437X_PRUETH1_TXD1: R468.2(P2) ; also on sheet 14
AM437X_PRUETH1_TXEN: R157.1(P1) ; also on sheet 14
AM437X_PRUETH_MDCLK: R79.2(P2) ; also on sheet 14
AM437X_PRUETH_MDDATA: R78.2(P2) ; also on sheet 14
AM437X_QSPI_CLK: R128.2(P2) U11.B12(GPMC_CSN3/QSPI_CLK)
AM437X_QSPI_CSn: R144.2(P2) U11.A8(GPMC_CSN0/QSPI_CSn)
AM437X_QSPI_D0: R137.2(P2) U11.A9(GPMC_ADVN_ALE/QSPI_D0)
AM437X_QSPI_D1: R449.2(P2) U11.E10(GPMC_OEN_REN/QSPI_D1)
AM437X_QSPI_D2: R457.2(P2) U11.D10(GPMC_WEN/QSPI_D2)
AM437X_QSPI_D3: R453.2(P2) U11.C10(GPMC_BE0N_CLE/QSPI_D3)
AM437X_SD_CLKOUT: R263.2(P2) U11.AD25(CAM1_HSYNC/SD_DATA_IN0)
AM437X_SD_DATA_IN1: R262.2(P2) U11.AE21(CAM1_PCLK/SD_DATA_IN1)
AM437X_SPI0_CS0n: J16.30 R384.2(P2) U11.T20(SPI0_CS0)
AM437X_SPI0_D1: J16.28 R382.2(P2) U11.T21(SPI0_D1)
AM437X_SPI0_SCLK: R385.1(P1) U11.P23(SPI0_SCLK)
AM437X_UART0_TXD: R261.2(P2) ; also on sheet 5
CAM_MTR_EN: U11.A2(GPMC_WAIT0) ; also on sheet 2
CAN0_RXDF: R248.2(P2) R386.2
CAN0_RXDF_PR1_EDC_LATCH0_IN: J16.41 R247.1(P1) R248.1(P1)
CAN0_TXDF: C177.1 R246.2(P2) R387.2
CAN0_TXDF_PR1_EDC_LATCH1_IN: J16.43 R245.1(P1) R246.1(P1)
eHRPWM3_SYNCO: J16.23 R253.1(P1)
ENDAT_EN: R388.2(P2) R519.1(P1) U57.2(~{RE})
eQEP1_INDEX: J16.51 R241.1(P1)
eQEP1_STROBE: J16.53 R465.1(P1)
eQEP1A_IN: J16.57 R468.1(P1)
eQEP1B_IN: J16.55 R471.1(P1)
eQEP2_INDEX: J16.42 U11.B11(GPMC_AD14/eQEP2_INDEX)
eQEP2_STROBE: J16.44 U11.A11(GPMC_AD15/eQEP2_STROBE)
eQEP2A_IN: J16.46 U11.E11(GPMC_AD12/eQEP2A_IN)
eQEP2B_IN: J16.48 U11.C11(GPMC_AD13/eQEP2B_IN)
HDQ: J16.50 R243.2(P2)
IND_I2C_SCL: J16.27 ; also on sheet 12
IND_I2C_SDA: J16.29 ; also on sheet 12
MMC_CD: J19.10(CD) R84.1(P1) R548.1(P1) U59.3(IO1)
MMC_CLK: J19.5(CLOCK) R179.1(P1) U27.1(IO1)
MMC_CMD: J19.3(CMD) R177.1(P1) R244.1(P1) U27.7(IO5)
MMC_D0: J19.7(DAT0) R174.1(P1) R267.1(P1) U27.2(IO2)
MMC_D1: J19.8(DAT1) R167.1(P1) R266.1(P1) U27.3(IO3)
MMC_D2: J19.1(DAT2) R161.1(P1) R236.1(P1) U27.6(IO4)
MMC_D3: J19.2(CD/DAT3) R158.1(P1) R231.1(P1) U27.8(IO6)
MTR_FAULT: R245.2(P2) ; also on sheet 10
MTRA_GND: C270.2 J10.1 J10.5 R513.1(P1)
OSC0_IN: C36.1 R82.2(P2) R92.2(P2) Y1.3
OSC0_OUT: C35.1 R82.1(P1) R91.2(P2) Y1.1
PORZ_RELEASE: R487.1(P1) ; also on sheet 11
PORZn: R75.1(P1) R90.2(P2) R416.2(P2) R487.2(P2) U54.2(A) ; also on sheet 4
PR1_EDC_SYNC0_OUT: J16.18 ; also on sheet 5
PR1_EDC_SYNC1_OUT: R256.1(P1) ; also on sheet 5
PR1_EDIO_DATA6: J3.6 U11.B9(GPMC_CSN1/PR1_EDIO_DATA6)
PR1_EDIO_DATA7: J3.8 U11.F10(GPMC_CSN2/PR1_EDIO_DATA7)
PRU0_ENDAT0_CLK: J16.31 R422.1(P1) R428.1(P1) R493.2(P2)
PRU0_ENDAT0_OUT: J16.33 R423.1(P1) R427.1(P1) R540.2(P2)
PRU0_ENDAT1_CLK: J16.32 R252.2(P2)
PRU0_ENDAT1_IN: J16.38 R249.2(P2)
PRU0_ENDAT1_OUT: J16.34 R251.2(P2)
PRU0_ENDAT1_OUTEN: J16.36 R250.2(P2)
PRU0_ENDAT2_CLK: J16.52 R242.2(P2)
PRU0_ENDAT2_IN: J16.58 R238.2(P2)
PRU0_ENDAT2_OUT: J16.54 R240.2(P2)
PRU0_ENDAT2_OUTEN: J16.56 R239.2(P2)
PRUETH0_25MHzCLK: U7.23(XI) ; also on sheet 13
PRUETH0_COL: R57.2(P2) R351.1(P1) R352.2(P2) R434.1(P1) U7.29(COL)
PRUETH0_CRS: R65.1(P1) U7.27(CRS)
PRUETH0_INT: TP3.1 U7.8(PWRDNn/INTn)
PRUETH0_LINKLED: R77.1(P1) R348.2(P2) U7.17(LED_LINK)
PRUETH0_MDC: R79.1(P1) U7.20(MDC)
PRUETH0_MDIO: R78.1(P1) U7.19(MDIO)
PRUETH0_RESETn: U7.18(RESET_N) U43.4(Y)
PRUETH0_RXCLK: R76.1(P1) U7.25(RX_CLK)
PRUETH0_RXD0: R55.2(P2) R349.1(P1) U7.30(RXD_0)
PRUETH0_RXD1: R51.2(P2) R344.1(P1) U7.31(RXD_1)
PRUETH0_RXD2: R46.2(P2) R339.1(P1) U7.32(RXD_2)
PRUETH0_RXD3: R44.2(P2) R337.1(P1) U7.1(RXD_3)
PRUETH0_RXDV: R67.1(P1) U7.26(RX_DV)
PRUETH0_RXERR: R59.1(P1) U7.28(RX_ERR)
PRUETH0_TXCLK: R410.1(P1) U7.2(TX_CLK)
PRUETH0_TXD0: R391.1(P1) U7.4(TXD_0)
PRUETH0_TXD1: R378.1(P1) U7.5(TXD_1)
PRUETH0_TXD2: R377.1(P1) U7.6(TXD_2)
PRUETH0_TXD3: R390.1(P1) U7.7(TXD_3)
PRUETH0_TXEN: R405.1(P1) U7.3(TX_EN)
PRUETHER0_RDN: J6.2 R31.2(P2) U7.9(RD-)
PRUETHER0_RDP: J6.1 R43.2(P2) U7.10(RD+)
PRUETHER0_TDN: J6.6 R50.2(P2) U7.11(TD-)
PRUETHER0_TDP: J6.5 R56.2(P2) U7.12(TD+)
RT_MII0_RXDV: J3.3 R63.1(P1)
RT_MII0_TXEN: J3.1 R404.1(P1)
RT_MII1_RXDV: J3.4 R459.2(P2)
RT_MII1_TXEN: J3.2 R157.2(P2)
RT_MII_EDIO_DATA0: J3.5 R382.1(P1)
RT_MII_EDIO_DATA1: J3.7 R384.1(P1)
SD0_CLKIN: J16.3 R265.1(P1)
SD_CLKIN: J16.5 R264.1(P1)
SD_DATA_IN0_SD_CLKOUT: J16.7 R263.1(P1)
SD_DATA_IN1: J16.9 R262.1(P1)
SD_DATA_IN2: J16.11 R261.1(P1)
SD_DATA_IN3: J16.13 R260.1(P1)
SD_DATA_IN4: J16.15 R259.1(P1)
SD_DATA_IN5_PR1_EDC_LATCH0_IN: J16.17 R258.1(P1)
SD_DATA_IN6: J16.19 R255.1(P1)
SD_DATA_IN7: J16.21 R254.1(P1)
SPI0_DIN: J16.26 U11.T22(SPI0_D0)
SPI0_SCLK: J16.24 R385.2(P2)
SPIMEM_CLK: R128.1(P1) U46.16(SCLK)
SPIMEM_CS: R144.1(P1) U46.7(~{CS})
SPIMEM_D0: R137.1(P1) U46.15(SI/SIO0)
SPIMEM_D1: R449.1(P1) U46.8(SO/SIO1)
SPIMEM_D2: R457.1(P1) R458.1(P1) U46.9(~{WP}/SIO2)
SPIMEM_D3: R453.1(P1) U46.1(DNU/SIO3)
SYNCI: R257.1(P1) U11.R24(SPI4_D0)
SYS_RESETn: J16.25 R152.2(P2) R499.1(P1) U43.2(B) ; also on sheet 6 13 14
SYS_WARMRESETn: C287.1 R69.1(P1) R86.2(P2) R498.1(P1) R499.2(P2) U54.4(Y) ; also on sheet 5
SYSBOOT0: U9.17(2A4) ; also on sheet 6
SYSBOOT1: U9.15(2A3) ; also on sheet 6
SYSBOOT2: U9.13(2A2) ; also on sheet 6
SYSBOOT3: U9.11(2A1) ; also on sheet 6
SYSBOOT4: U9.8(1A4) ; also on sheet 6
SYSBOOT5: U9.6(1A3) ; also on sheet 6
SYSBOOT6: U9.4(1A2) ; also on sheet 6
SYSBOOT7: U9.2(1A1) ; also on sheet 6
SYSBOOT8: U39.17(2A4) ; also on sheet 6
SYSBOOT9: U39.15(2A3) ; also on sheet 6
SYSBOOT10: U39.13(2A2) ; also on sheet 6
SYSBOOT11: U39.11(2A1) ; also on sheet 6
SYSBOOT12: U39.8(1A4) ; also on sheet 6
SYSBOOT13: U39.6(1A3) ; also on sheet 6
SYSBOOT14: U39.4(1A2) ; also on sheet 6
SYSBOOT15: U39.2(1A1) ; also on sheet 6
VADD33_PRUETH0: C33.1 R346.2(P2) U7.14(AVDD33)
VENDAT: C270.1 J10.2 J10.8 R483.2(P2) R485.2(P2)
N10692191: R498.2(P2) SW2.3 SW2.4
N11290828: R87.1(P1) U11.G25(NMIn)
N11290910: R86.1(P1) U11.G22(RESETIN_OUTn)
N11291034: R90.1(P1) U11.Y23(PORZn)
N12220066: C38.1 C163.1 C164.1 C167.1 U7.13(PFBIN1) U7.15(PFBOUT) U7.24(PFBIN2)
N12591797: TP2.1 U11.H20(CLKREQ)
N12825337: J10.7 U55.6(A)
N12825341: J10.6 U55.7(B)
N12825345: R493.1(P1) U55.4(D)
N12825349: TP12.1 U55.1(R)
N12825453: J10.4 R512.1(P1) U57.7(B)
N12825465: J10.3 R512.2(P2) U57.6(A)
N12825469: R514.1(P1) U57.1(R)
N12825473: R540.1(P1) U57.4(D)
N12825749: R526.1(P1) U57.3(DE)
N16169613: R546.1(P1) U58.16(B6)
N16169629: J15.5 U58.18(B4)
N16169633: R547.1(P1) U58.17(B5)
N16169657: C347.1 J15.2 R552.1(P1) U58.21(B1)
N16169661: C351.1 J15.3 R560.1(P1) U58.20(B2)
N16169665: C352.1 J15.4 R565.1(P1) U58.19(B3)
N16818596: J6.9 R411.1(P1)
N16818719: R412.1(P1) R417.1(P1) U43.1(A)
N16819128: R362.2(P2) U7.16(RBIAS)
N16880569: R416.1(P1) U9.1(1OE#) U9.19(2OE#) U39.1(1OE#) U39.19(2OE#)
N17047964: R515.1(P1) U58.2(DIR)
N17047991: R541.1(P1) R542.1(P1) U58.22(~{OE})
N17048274: R544.1(P1) U58.14(B8)
N17048276: R545.1(P1) U58.15(B7)
N17074741: J6.10 R352.1(P1)
N17080008: R406.2(P2) U9.16(1Y2)
N17080011: R408.2(P2) U9.18(1Y1)
N17144335: R152.1(P1) U46.3(~{RESET})
N17863265: J6.11 R310.1(P1)
N17863276: J6.12 R348.1(P1)
N18003575: J16.20 R256.2(P2) R257.2(P2)
N18075381: R478.2(P2) U11.AC18(CAM0_FIELD)
N18075410: R472.1(P1) R477.1(P1) SW1.1 SW1.2
N18075448: C262.1 R477.2(P2) R478.1(P1)
N18075562: R388.1(P1) U11.E25(GPIO5_12)
N18075603: R383.1(P1) U11.P20(SPI2_D1)
N18075606: R74.1(P1) U11.T23(SPI2_CS0)
N18181630: R73.1(P1) U11.P24(SPI4_D1/eHRPWM0_TRIPZONE_I)
N18646501: R567.2(P2) U11.AE10(PMU_PORZ)
N18646504: R568.2(P2) U11.AE8(PMU_HIBZ)
N18646588: R569.2(P2) U11.AD10(RSV)
N18646760: R570.2(P2) U11.AD11(RSV)

Not connected (* = marked no-connect by the designer): J3 9; J6 7; U7 22(XO)*; U11 A5(GPMC_AD1) A6(GPMC_AD3) A7(GPMC_AD5) AA7(RSV) AA9(RSV) AA10(RSV) AA19(CAM0_DATA9) AB6(TAMPER_EVENT) AB7(RSV) AB9(RSV) AB10(RSV) AB19(CAM0_DATA8) AC5(RSV) AC6(RSV) AC7(RSV) AC9(RSV) AC10(RSV) AC12(RSV) AC24(CAM1_DATA9) AD1(TEMP_DIODE_P) AD2(TEMP_DIODE_N) AD7(PMIC_POWER_EN1) AD22(CAM1_DATA4) AE7(EXT_WAKEUP1) AE9(RSV) AE11(XI_32K) AE12(XO_32K) B5(GPMC_AD0) B6(GPMC_AD2) B7(GPMC_AD4) B8(GPMC_AD7) C8(GPMC_AD6) F24(GPIO5_9) F25(USB1_DRVVBUS) G21(USB0_DRVVBUS) G24(ECAP0_IN_PWM0_OUT) H19(RSV) T25(USB1_VBUS) U22(USB1_CE) U23(USB0_VBUS) U24(USB0_ID) U25(USB1_ID) V24(USB1_DP) V25(USB1_DM) W10(RSV) W22(USB0_CE) W24(USB0_DM) W25(USB0_DP) Y6(RSV) Y7(RSV) Y10(RSV); U27 4(NC1)* 9(NC2)*; U46 4(NC4) 5(NC5) 6(NC6) 11(NC11) 12(NC12) 13(NC13) 14(NC14); U54 1(NC)*; U58 7(A5) 8(A6) 9(A7) 10(A8); U59 2(NC)* 5(IO2); Y1 2(NC0)* 4(NC1)*

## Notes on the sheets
sheet 15
- Note: MDIO Address = 0x00
sheet 16
- SD/MMC0 Connector
sheet 17
- User Switch
- Expansion Connector
sheet 18
- Warm Reset Switch
